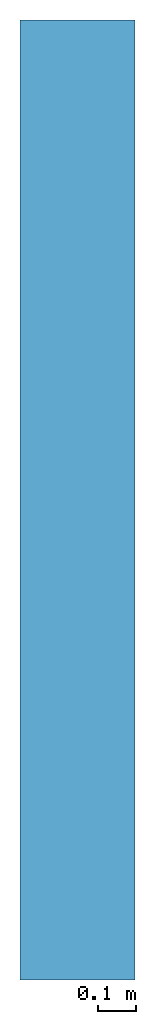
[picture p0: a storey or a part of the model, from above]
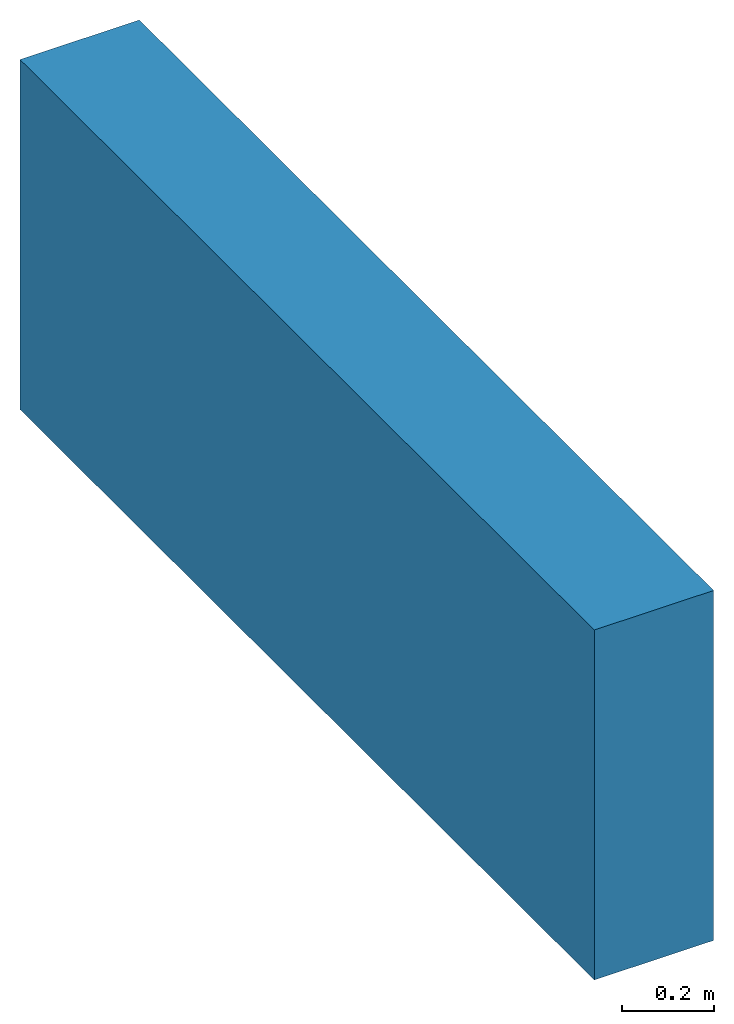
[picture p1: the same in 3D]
Properties of the parts of a building model (IFC2X3), part 1 of 4

# File
Description: ViewDefinition [CoordinationView]
File name: GM.TO-350-202.1 (EDITED).ifc (Edited by Naviate Simple BIM 2022 version 6)
Time: 2026-03-17T17:04:53+01:00
Written by: ODA SDAI 24.12
Made in: Autodesk Revit 25.4.20.11 (ENU) - IFC 25.4.0.27

# IfcProject, A181143
LongName: T2; Phase: Detaljprosjekt

# IfcSite (9)
Name | RefLatitude | RefLongitude | RefElevation (mm) | Reference latitude | Reference elevation | Reference longitude
ENGM | 33, 12, 51, 119999 | -97, -7, -51, -239999 | -4.85124e-10
 | 33, 12, 51, 119999 | -97, -7, -51, -239999 | 0
 | 33, 12, 51, 119999 | -97, -7, -51, -239999 | 0 | 33, 12, 51, 119999 | 0 | -97, -7, -51, -239999
4 x ENGM | 59, 54, 49, 759826 | 10, 44, 19, 467315 | 0 | 59, 54, 49, 759826 | 0 | 10, 44, 19, 467315 | MagiCAD Pset_Site - Name: ENGM
Gardermoen
Default | 59, 54, 49, 759826 | 10, 44, 19, 467315 | 0

# IfcBuilding (9)
Name
TS | LongName: TS; Pset_BuildingCommon - NumberOfStoreys: 16
2 x mc-building
4 x TS | MagiCAD Pset_Building - Building name: TS
TS
 | Pset_BuildingCommon - NumberOfStoreys: 13

# IfcBuildingStorey (15)
Name | In | Elevation (mm) | Name
Nivå E | mc-building | 207370
Nivå D | mc-building | 204000
Nivå F -0,7m | mc-building | 210200
Nivå F | mc-building | 210900
Nivå E | mc-building | 207370 | Nivå E
Nivå F | mc-building | 210900 | Nivå F
4 x Nivå F | TS | 210900 | Nivå F
2 x Nivå E | TS | 207370 | Nivå E
F | TS | 0
D | TS | 0
Nivå F - 0,7 m | TS | 210200 | Nivå F - 0,7 m

# IfcBuildingStorey: Level:8mm Head, Nivå F
LongName: Nivå F; Elevation: 210900 mm
Pset_ProductRequirements - Name: Nivå F; sets with these values: 2

# IfcBuildingStorey: Level:T2 - Kote (4)
In: TS
Name | LongName | Elevation (mm) | Pset_AirSideSystemInformation, Name | Pset_AirSideSystemInformation, sets with these values
Nivå E | Nivå E | 207370 | Nivå E | 2
Nivå F - 0,7 m | Nivå F - 0,7 m | 210200 | Nivå F - 0,7 m | 2
Nivå F | Nivå F | 210900 | Pset_ProductRequirements - Name: Nivå F; sets with these values: 2
Nivå G - 2,0m | Nivå G - 2,0m | 213700 | Nivå G - 2,0m | 2

# IfcBeam: B223 - Bjelke - HUP1:B223 - HUP 100 x 150 x 8 mm (8)
Type - PredefinedType: BEAM
Type - Pset_BeamCommon - LoadBearing: yes
Material: _NSW Stål
ePset_Simplebim - Assembly Level: Leaf
AVINOR - 08_Status: S4; 07_Fase: F90; 02_Prosjekt: A161568; 03_Ansvar: 182412; 04_Kontrakt: 182251; 06_Omrade: TS; 01_Lufthavnkode: ENGM
Pset_QuantityTakeOff - Reference: B223 - HUP 100 x 150 x 8 mm; sets with these values: 2
Pset_BeamCommon - IsExternal: no; Slope: 0 deg; Reference: B223 - HUP 100 x 150 x 8 mm
ePset_SimplebimBasicQuantities - Width (Simplebim): 100 mm; Height (Simplebim): 150 mm
ePset_LocationTool - Splitting: ORIGINAL
Name (B223 - Bjelke - HUP1:B223 - HUP 100 x 150 x 8 mm:...) | In | Span (mm) = Length (Simplebim) (mm) | Volume, net (Simplebim) (m3) | Weight, as steel (Simplebim) (kg) | Area, sides, net (Simplebim) (m2)
46579914 | Nivå F | 5590 | 0.020929 | 164.292 | 5.23973
46579916 | Nivå F | 5590 | 0.020929 | 164.292 | 5.23973
46579919 | Nivå F | 3808.67 | 0.0142596 | 111.938 | 3.5724
46579921 | Nivå F | 3808.67 | 0.0142596 | 111.938 | 3.5724
46580010 | Nivå F | 2480 | 0.00928512 | 72.8882 | 2.32877
46580027 | Nivå F | 3687.5 | 0.013806 | 108.377 | 3.45899
46580053 | Nivå G - 2,0m | 4445 | 0.0166421 | 130.64 | 4.16801
46580308 | Nivå G - 2,0m | 3687.5 | 0.013806 | 108.377 | 3.45899

# IfcBeam: DLB400*1500-800*700 (3)
In: F
Description: DLB400*1500-800*700
ePset_SimplebimBasicQuantities - Width (Simplebim): 400 mm; Height (Simplebim): 780 mm
Pset_BeamCommon - LoadBearing: no
ePset_Simplebim - Assembly Level: Leaf
ePset_LocationTool - Splitting: RESULT
AVINOR - 07_Fase: F90; 02_Prosjekt: T1; 03_Ansvar: FDV; 04_Kontrakt: FDV; 08_Status: S2; 06_Omrade: TS; 01_Lufthavnkode: ENGM
Tekla Common - Name: PREFABBJELKE; Bottom elevation: +209.180; Profile: DLB400*1500-800*700; Grade: C45/55; Top elevation: +210.680; Class: 130
Name | Area, sides, net (Simplebim) (m2) | Volume, net (Simplebim) (m3) | Length (Simplebim) (mm) | Weight, as steel (Simplebim) (kg) | Reference = Part mark | Assembly mark
PREFABBJELKE | 27.8 | 3.24111 | 11385 | 25442.7 | Concrete-4903(?) | PB-133(?)
PREFABBJELKE | 21.7946 | 2.50161 | 8970 | 19637.6 | Concrete-4901(?) | PB-131(?)
PREFABBJELKE | 2.29959 | 0.221519 | 710 | 1738.92 | Concrete-4901(?) | PB-131(?)

# IfcBuildingElementProxy (5)
ePset_Simplebim - Assembly Level: Leaf
ePset_LocationTool - Splitting: ORIGINAL
Name | In | Volume, net (Simplebim) (m3) | Area, largest surface, net (Simplebim) (m2) | Thickness (Simplebim) (mm) | Length (Simplebim) (mm) | Height (Simplebim) (mm)
hette 1100-2000-550_250x500 | Nivå F -0,7m | 1.50105 | 3 | 1500 | 2000 | 509.515 | Group: Mechanical +TU=360.032Avt 1; Mechanical +TU=360.032Avt 2
hette 1200-1200-400 ø315 2 | Nivå F -0,7m | 0.7216 | 1.44 | 1200 | 1200 | 510 | Group: +TQ=360.010 A
2 x MagiCAD_Sprinkler_Design_Area | Nivå F | 0.001 | 0.01 | 100 | 100 | 100 | Description: Sprinkler Design Area
Håndslukker | Nivå F | 0.0130382 | 0.261216 | 179.937 | 323.075 | 600.535

# IfcBuildingElementProxy: A234 - Gitter:A241 - Gitter 300 x 300_UK_2700_offset 51 (2)
In: Nivå F
Type - Material: <Unnamed>
ePset_Simplebim - Assembly Level: Leaf
Pset_QuantityTakeOff - Reference: A241 - Gitter 300 x 300_UK_2700_offset 51; sets with these values: 2
AVINOR - 08_Status: S4; 07_Fase: F90; 02_Prosjekt: A161568; 03_Ansvar: 182412; 04_Kontrakt: 182251; 06_Omrade: TS; 01_Lufthavnkode: ENGM
ePset_SimplebimBasicQuantities - Thickness (Simplebim): 300 mm; Height (Simplebim): 300 mm
ePset_LocationTool - Splitting: ORIGINAL
Name (A234 - Gitter:A241 - Gitter 300 x 300_UK_2700_offset 51:...) | Volume, net (Simplebim) (m3) | Length (Simplebim) (mm) | Area, largest surface, net (Simplebim) (m2)
46579913 | 0.5022 | 5580 | 1.674
46579918 | 0.352619 | 3917.99 | 1.1754

# IfcBuildingElementProxy: A275 - Pylon - venstrehengslet:Pylon med topp brakett, A275 - Pylon - venstrehengslet:Pylon med topp brakett:43108020
In: Nivå F
Type - Material: <Unnamed>
ePset_SimplebimBasicQuantities - Area, largest surface, net (Simplebim): 1.78713 m2; Volume, net (Simplebim): 0.0408924 m3; Thickness (Simplebim): 195 mm; Length (Simplebim): 752 mm; Height (Simplebim): 2500 mm
Pset_QuantityTakeOff - Reference: Pylon med topp brakett; sets with these values: 2
AVINOR - 08_Status: S1; 07_Fase: F50; 04_Kontrakt: 72587; 02_Prosjekt: 72101; 03_Ansvar: AE1; 06_Omrade: TS; 01_Lufthavnkode: ENGM
ePset_Simplebim - Assembly Level: Leaf
ePset_LocationTool - Splitting: ORIGINAL

# IfcBuildingElementProxy: ProvisionForVoid (3)
In: Nivå F
ePset_LocationTool - Splitting: ORIGINAL
ePset_SimplebimBasicQuantities - Height (Simplebim): 340 mm
ePset_Simplebim - Assembly Level: Leaf
Name | Volume, net (Simplebim) (m3) | Thickness (Simplebim) (mm) = Length (Simplebim) (mm) | Area, largest surface, net (Simplebim) (m2)
Round Vertical | 0.00170036 | 80 | 0.0853429
2 x Round Vertical | 0.000664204 | 50 | 0.0533393

# IfcColumn: A243 - Rullegardinskinner1:A243 - Portskinne Trav Val Innl (6)
Type - PredefinedType: COLUMN; Material: _NSW Stål
Type - Pset_ColumnCommon - LoadBearing: yes
ePset_LocationTool - Splitting: ORIGINAL
ePset_SimplebimBasicQuantities - Width (Simplebim): 60 mm; Depth (Simplebim): 100 mm
ePset_Simplebim - Assembly Level: Leaf
AVINOR - 08_Status: S4; 07_Fase: F90; 02_Prosjekt: A161568; 03_Ansvar: 182412; 04_Kontrakt: 182251; 06_Omrade: TS; 01_Lufthavnkode: ENGM
Pset_ColumnCommon - IsExternal: no; Reference: A243 - Portskinne Trav Val Innl
Pset_QuantityTakeOff - Reference: A243 - Portskinne Trav Val Innl; sets with these values: 2
Name (A243 - Rullegardinskinner1:A243 - Portskinne Trav Val Innl:...) | In | Volume, net (Simplebim) (m3) | Weight, as steel (Simplebim) (kg) | Area, sides, net (Simplebim) (m2) | Height (Simplebim) (mm)
46579901 | Nivå F | 0.0027552 | 21.6283 | 1.7584 | 2800
46579901 | Nivå G - 2,0m | 0.0001968 | 1.54488 | 0.1256 | 200
46579903 | Nivå F | 0.0025092 | 19.6972 | 1.6014 | 2550
46579905 | Nivå F | 0.0025092 | 19.6972 | 1.6014 | 2550
46579907 | Nivå F | 0.0027552 | 21.6283 | 1.7584 | 2800
46579907 | Nivå G - 2,0m | 0.0001968 | 1.54488 | 0.1256 | 200

# IfcColumn: B222 - HUP (Oppsveiset)1:B222 - HUP oppsveiset - 100 x 100 x 8 mm (2)
Type - PredefinedType: COLUMN; Material: _NSW Stål
Type - Pset_ColumnCommon - LoadBearing: yes
Pset_ColumnCommon - IsExternal: no; Reference: B222 - HUP oppsveiset - 100 x 100 x 8 mm
Pset_QuantityTakeOff - Reference: B222 - HUP oppsveiset - 100 x 100 x 8 mm; sets with these values: 2
ePset_SimplebimBasicQuantities - Width (Simplebim): 100 mm; Depth (Simplebim): 100 mm
ePset_Simplebim - Assembly Level: Leaf
AVINOR - 08_Status: S4; 07_Fase: F90; 02_Prosjekt: A161568; 03_Ansvar: 182412; 04_Kontrakt: 182251; 06_Omrade: TS; 01_Lufthavnkode: ENGM
ePset_LocationTool - Splitting: ORIGINAL
Name (B222 - HUP (Oppsveiset)1:B222 - HUP oppsveiset - 100 x 100 x 8 mm:...) | In | Volume, net (Simplebim) (m3) | Area, sides, net (Simplebim) (m2) | Height (Simplebim) (mm) | Weight, as steel (Simplebim) (kg)
46580008 | Nivå F | 0.0164864 | 4.1216 | 2800 | 129.418
46580008 | Nivå G - 2,0m | 0.0011776 | 0.2944 | 200 | 9.24416

# IfcColumn: B222 - HUP (Oppsveiset)1:B222 - HUP oppsveiset - 150 x 150 x 6 mm 2 (6)
Type - PredefinedType: COLUMN; Material: _NSW Stål
Type - Pset_ColumnCommon - LoadBearing: yes
Pset_ColumnCommon - IsExternal: no; Reference: B222 - HUP oppsveiset - 150 x 150 x 6 mm 2
Pset_QuantityTakeOff - Reference: B222 - HUP oppsveiset - 150 x 150 x 6 mm 2; sets with these values: 2
ePset_Simplebim - Assembly Level: Leaf
ePset_SimplebimBasicQuantities - Width (Simplebim): 150 mm; Depth (Simplebim): 150 mm
AVINOR - 08_Status: S4; 07_Fase: F90; 02_Prosjekt: A161568; 03_Ansvar: 182412; 04_Kontrakt: 182251; 06_Omrade: TS; 01_Lufthavnkode: ENGM
ePset_LocationTool - Splitting: ORIGINAL
Name (B222 - HUP (Oppsveiset)1:B222 - HUP oppsveiset - 150 x 150 x 6 mm 2:...) | In | Weight, as steel (Simplebim) (kg) | Area, sides, net (Simplebim) (m2) | Volume, net (Simplebim) (m3) | Height (Simplebim) (mm)
46579899 | Nivå F | 151.926 | 6.4512 | 0.0193536 | 2800
46579899 | Nivå G - 2,0m | 10.8518 | 0.4608 | 0.0013824 | 200
46579909 | Nivå F | 151.926 | 6.4512 | 0.0193536 | 2800
46579909 | Nivå G - 2,0m | 10.8518 | 0.4608 | 0.0013824 | 200
46579942 | Nivå F | 151.926 | 6.4512 | 0.0193536 | 2800
46579942 | Nivå G - 2,0m | 10.8518 | 0.4608 | 0.0013824 | 200

# IfcCovering (29)
PredefinedType: INSULATION
ePset_Simplebim - Assembly Level: Leaf
ePset_LocationTool - Splitting: ORIGINAL
Name | In | Description | Area, largest surface, net (Simplebim) (m2) | Volume, net (Simplebim) (m3) | Width (Simplebim) (mm) | Height (Simplebim) (mm) | Length (Simplebim) (mm)
EI30-30 | Nivå D | EI30 Brannisolasjon 30 mm | 0.7788 | 0.067968 | 360 | 660 | 1180
B=EI60 80 | Nivå D | EI60 Brannisolasjon 80mm | 0.3496 | 0.036708 | 105 | 460 | 760
EI30-30 | Nivå D | EI30 Brannisolasjon 30 mm | 0.2376 | 0.013068 | 55 | 360 | 660
EI30-30 | Nivå D | EI30 Brannisolasjon 30 mm | 0.26273 | 0.0212628 | 360 | 305.5 | 860
B=EI60 80 | Nivå D | EI60 Brannisolasjon 80mm | 0.4416 | 0.048576 | 460 | 110 | 960
EI30-30 | Nivå D | EI30 Brannisolasjon 30 mm | 0.3096 | 0.0266553 | 360 | 86.096 | 860
EI30-30 | Nivå D | EI30 Brannisolasjon 30 mm | 1.25672 | 0.101706 | 360 | 860 | 1461.3
EI30-30 | Nivå F -0,7m | EI30 Brannisolasjon 30 mm | 0.13639 | 0.0113856 | 296.5 | 240 | 460
EI30-30 | Nivå F -0,7m | EI30 Brannisolasjon 30 mm | 0.202078 | 0.0168691 | 439.3 | 240 | 460
EI30-30 | Nivå F -0,7m | EI30 Brannisolasjon 30 mm | 0.1104 | 0.009505 | 86.096 | 240 | 460
EI30-30 | Nivå F -0,7m | EI30 Brannisolasjon 30 mm | 0.5911 | 0.049344 | 460 | 240 | 1285
3 x EI30-30 | Nivå F -0,7m | EI30 Brannisolasjon 30 mm | 0.379852 | 0.0291658 | 405 | 310 | 405
EI30-30 | Nivå F -0,7m | EI30 Brannisolasjon 30 mm | 0.266022 | 0.00718091 | 310 | 310 | 273.5
EI30-30 | Nivå F -0,7m | EI30 Brannisolasjon 30 mm | 0.873739 | 0.0235854 | 310 | 310 | 898.3
EI30-30 | Nivå F -0,7m | EI30 Brannisolasjon 30 mm | 0.0277208 | 0.000748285 | 310 | 310 | 28.5
EI30-30 | Nivå F -0,7m | EI30 Brannisolasjon 30 mm | 0.0978494 | 0.00264131 | 310 | 100.6 | 310
B=EI60 80 | Nivå F -0,7m | EI60 Brannisolasjon 80mm | 0.340618 | 0.0346938 | 410 | 265 | 410
EI30-30 | Nivå F -0,7m | EI30 Brannisolasjon 30 mm | 0.995418 | 0.02687 | 310 | 310 | 1023.4
EI30-30 | Nivå F -0,7m | EI30 Brannisolasjon 30 mm | 0.126342 | 0.00968982 | 202.5 | 310 | 322.728
EI30-30 | Nivå F -0,7m | EI30 Brannisolasjon 30 mm | 0.343348 | 0.00926823 | 310 | 310 | 353
EI30-30 | Nivå F -0,7m | EI30 Brannisolasjon 30 mm | 0.109619 | 0.00295901 | 310 | 310 | 112.7
B=EI60 80 | Nivå F -0,7m | EI60 Brannisolasjon 80mm | 0.13092 | 0.00720061 | 410 | 410 | 55
EI30-30 | Nivå F -0,7m | EI30 Brannisolasjon 30 mm | 0.137954 | 0.0115162 | 299.9 | 240 | 460
EI30-30 | Nivå F -0,7m | EI30 Brannisolasjon 30 mm | 0.0746175 | 0.00232031 | 31.096 | 310 | 310
2 x EI30-30 | Nivå F -0,7m | EI30 Brannisolasjon 30 mm | 0.110414 | 0.0231983 | 341.972 | 240 | 466.958
EI30-30 | Nivå F -0,7m | EI30 Brannisolasjon 30 mm | 0.1104 | 0.006745 | 61.096 | 240 | 460

# IfcCovering: Compound Ceiling:A255 - HI-G03, Compound Ceiling:A255 - HI-G03:46580038
In: Nivå F
Type - PredefinedType: CEILING
Type - Pset_CoveringCommon - TotalThickness: 30 mm
AVINOR - 08_Status: S4; 07_Fase: F90; 02_Prosjekt: A161568; 03_Ansvar: 182412; 04_Kontrakt: 182251; 06_Omrade: TS; 01_Lufthavnkode: ENGM
ePset_SimplebimBasicQuantities - Volume, net (Simplebim): 3.30073 m3; Area, largest surface, net (Simplebim): 110.024 m2; Height (Simplebim): 30 mm; Width (Simplebim): 7139 mm; Length (Simplebim): 15575 mm
ePset_Simplebim - Assembly Level: Leaf
ePset_LocationTool - Splitting: RESULT
Pset_CoveringCommon - Reference: A255 - HI-G03; sets with these values: 2

# IfcCovering: Compound Ceiling:A255 - eksisterende finerte himlingsplater (4)
In: Nivå F
Type - PredefinedType: CEILING
Type - Pset_CoveringCommon - TotalThickness: 30 mm
ePset_LocationTool - Splitting: RESULT
ePset_Simplebim - Assembly Level: Leaf
ePset_SimplebimBasicQuantities - Height (Simplebim): 30 mm
Pset_CoveringCommon - Reference: A255 - eksisterende finerte himlingsplater; sets with these values: 2
AVINOR - 08_Status: S4; 07_Fase: F90; 03_Ansvar: FDV; 06_Omrade: TS; 01_Lufthavnkode: ENGM
Name (Compound Ceiling:A255 - eksisterende finerte himlingsplater:...) | Area, largest surface, net (Simplebim) (m2) | Width (Simplebim) (mm) | Length (Simplebim) (mm) | Volume, net (Simplebim) (m3)
30392710 | 16.5644 | 1093 | 15155 | 0.496933
30394236 | 4.96815 | 330 | 15055 | 0.149045
30394383 | 4.96815 | 330 | 15055 | 0.149045
30394414 | 13.8062 | 911 | 15155 | 0.414186

# IfcCovering: Compound Ceiling:A255 - eksisterende himling perfo. metall paneler 200, Compound Ceiling:A255 - eksisterende himling perfo. metall paneler 200:30393361
In: Nivå F
Type - PredefinedType: CEILING
Type - Pset_CoveringCommon - TotalThickness: 30 mm
ePset_LocationTool - Splitting: RESULT
ePset_Simplebim - Assembly Level: Leaf
Pset_QuantityTakeOff - Reference: A255 - eksisterende himling perfo. metall paneler 200; sets with these values: 2
ePset_SimplebimBasicQuantities - Area, largest surface, net (Simplebim): 6.64992 m2; Height (Simplebim): 30 mm; Width (Simplebim): 1270 mm; Length (Simplebim): 5235 mm; Volume, net (Simplebim): 0.199501 m3
AVINOR - 08_Status: S4; 07_Fase: F90; 03_Ansvar: FDV; 06_Omrade: TS; 01_Lufthavnkode: ENGM

# IfcCurtainWall: Curtain Wall:A242 - IGV - Glass - 10 mm (2)
In: Nivå F
AVINOR - 08_Status: S4; 07_Fase: F90; 03_Ansvar: 182412; 02_Prosjekt: A173790; 06_Omrade: TS; 01_Lufthavnkode: ENGM
ePset_SimplebimBasicQuantities - Height: 2500 mm
Pset_QuantityTakeOff - Reference: A242 - IGV - Glass - 10 mm
Pset_CurtainWallCommon - IsExternal: no; Reference: A242 - IGV - Glass - 10 mm
ePset_Simplebim - Assembly Level: Topmost
Name (Curtain Wall:A242 - IGV - Glass - 10 mm:...) | 05_ID-nummer | Volume, net (Simplebim) (m3) | Width (mm) | Length (mm)
47507136 | +TS=243.001-IG0058 | 0.136829 | 100 | 3950
47507151 | +TS=243.001-IG0059 | 0.157984 | 105 | 4325

# IfcCurtainWall: Curtain Wall:A242 - IGV - Glass - 20mm (2)
In: Nivå F
Pset_QuantityTakeOff - Reference: A242 - IGV - Glass - 20mm
ePset_SimplebimBasicQuantities - Width: 20 mm; Height: 440 mm
ePset_Simplebim - Assembly Level: Topmost
Pset_CurtainWallCommon - IsExternal: no; Reference: A242 - IGV - Glass - 20mm
AVINOR - 03_Ansvar: FDV
Name (Curtain Wall:A242 - IGV - Glass - 20mm:...) | Volume, net (Simplebim) (m3) | Length (mm)
46514074 | 0.0076472 | 869
46514077 | 0.0170192 | 1934

# IfcCurtainWall: Curtain Wall:A242 - IGV 50 x 60mm (Glass 10mm) (2)
In: Nivå F
Pset_CurtainWallCommon - IsExternal: no; Reference: A242 - IGV 50 x 60mm (Glass 10mm)
AVINOR - 07_Fase: F90; 06_Omrade: TS; 01_Lufthavnkode: ENGM
Pset_QuantityTakeOff - Reference: A242 - IGV 50 x 60mm (Glass 10mm)
ePset_Simplebim - Assembly Level: Topmost
ePset_SimplebimBasicQuantities - Length: 1274.01 mm; Volume, net (Simplebim): 0.0839612 m3; Width: 100 mm; Height: 2890 mm
Name (Curtain Wall:A242 - IGV 50 x 60mm (Glass 10mm):...) | 03_Ansvar | 08_Status
30360349 | FDV | S2
46579949 | 182412 | S4 | AVINOR - 02_Prosjekt: A161568; 04_Kontrakt: 182251

# IfcCurtainWall: Curtain Wall:A245 - BIM av T1 - IMK 20mm - Offset 30mm (2)
In: Nivå F
ePset_SimplebimBasicQuantities - Width: 110 mm; Height: 4490 mm
Pset_QuantityTakeOff - Reference: A245 - BIM av T1 - IMK 20mm - Offset 30mm
AVINOR - 07_Fase: F90; 03_Ansvar: FDV; 08_Status: S2; 06_Omrade: TS; 01_Lufthavnkode: ENGM
Pset_CurtainWallCommon - Reference: A245 - BIM av T1 - IMK 20mm - Offset 30mm; IsExternal: no
ePset_Simplebim - Assembly Level: Topmost
Name (Curtain Wall:A245 - BIM av T1 - IMK 20mm - Offset 30mm:...) | Volume, net (Simplebim) (m3) | Length (mm)
30365162 | 0.745048 | 8299.79
30365222 | 0.286525 | 3500.46

# IfcCurtainWall: Curtain Wall:A245 - IMK (Innvendig Metall Kledning) 20mm - Offset 30mm, Curtain Wall:A245 - IMK (Innvendig Metall Kledning) 20mm - Offset 30mm:40491772
In: Nivå F
Pset_CurtainWallCommon - IsExternal: no; Reference: A245 - IMK (Innvendig Metall Kledning) 20mm - Offset 30mm
Pset_QuantityTakeOff - Reference: A245 - IMK (Innvendig Metall Kledning) 20mm - Offset 30mm
ePset_SimplebimBasicQuantities - Volume, net (Simplebim): 0.234757 m3; Height: 2240 mm; Length: 6591.02 mm; Width: 195.091 mm
ePset_Simplebim - Assembly Level: Topmost
AVINOR - 07_Fase: F90; 08_Status: S1; 03_Ansvar: FDV; 06_Omrade: TS; 01_Lufthavnkode: ENGM

# IfcCurtainWall: Curtain Wall:A245 - IMK - Metal Kledning (5)
In: Nivå F
Pset_QuantityTakeOff - Reference: A245 - IMK - Metal Kledning
AVINOR - 08_Status: S4; 07_Fase: F90; 02_Prosjekt: A161568; 03_Ansvar: 182412; 04_Kontrakt: 182251; 06_Omrade: TS; 01_Lufthavnkode: ENGM
ePset_SimplebimBasicQuantities - Width: 20 mm
Pset_CurtainWallCommon - IsExternal: no; Reference: A245 - IMK - Metal Kledning
ePset_Simplebim - Assembly Level: Topmost
Name (Curtain Wall:A245 - IMK - Metal Kledning:...) | Volume, net (Simplebim) (m3) | Height (mm) | Length (mm)
46579930 | 0.0962 | 500 | 9620
46579940 | 0.00924 | 2310 | 200
46580012 | 0.0434658 | 490 | 4435.28
46580016 | 0.0419 | 500 | 4190
46580018 | 0.038122 | 490 | 3890

# IfcCurtainWall: Curtain Wall:A245 - IMK - Metal Kledning 3mm (12)
In: Nivå F
Pset_CurtainWallCommon - IsExternal: no; Reference: A245 - IMK - Metal Kledning 3mm
AVINOR - 08_Status: S4; 07_Fase: F90; 02_Prosjekt: A161568; 03_Ansvar: 182412; 04_Kontrakt: 182251; 06_Omrade: TS; 01_Lufthavnkode: ENGM
ePset_Simplebim - Assembly Level: Topmost
ePset_SimplebimBasicQuantities - Width: 3 mm
Pset_QuantityTakeOff - Reference: A245 - IMK - Metal Kledning 3mm
Name (Curtain Wall:A245 - IMK - Metal Kledning 3mm:...) | Volume, net (Simplebim) (m3) | Length (mm) | Height (mm)
46580055 | 0.0051678 | 1914 | 900
46580112 | 0.0013125 | 175 | 2500
46580250 | 0.0013125 | 175 | 2500
46580254 | 0.0013125 | 175 | 2500
46580258 | 0.0013125 | 175 | 2500
46580260 | 0.0013125 | 175 | 2500
46580262 | 0.0013125 | 175 | 2500
46580316 | 0.0013125 | 175 | 2500
46580318 | 0.0013125 | 175 | 2500
46580322 | 0.0013125 | 175 | 2500
46580324 | 0.0013125 | 175 | 2500
46580328 | 0.0013125 | 175 | 2500

# IfcCurtainWall: Curtain Wall:A245 - IMK - Metal Kledning KL-S01 (4)
In: Nivå F
AVINOR - 08_Status: S4; 07_Fase: F90; 09_Arbeidspakke: SELV ARBEIDER; 01_Lufthavnkode: ENGM
ePset_SimplebimBasicQuantities - Width: 10 mm; Height: 100 mm
Pset_QuantityTakeOff - Reference: A245 - IMK - Metal Kledning KL-S01
ePset_Simplebim - Assembly Level: Topmost
Pset_CurtainWallCommon - IsExternal: no; Reference: A245 - IMK - Metal Kledning KL-S01
Name (Curtain Wall:A245 - IMK - Metal Kledning KL-S01:...) | Length (mm) | Volume, net (Simplebim) (m3)
67054707 | 673 | 0.000673
67054709 | 120 | 0.00012
67054711 | 673 | 0.000673
67072278 | 3575.42 | 0.00357542

# IfcCurtainWall: Curtain Wall:KL - K05 Spilevegg 40x20 WHS (15)
In: Nivå F
Pset_QuantityTakeOff - Reference: KL - K05 Spilevegg 40x20 WHS
AVINOR - 08_Status: S4; 07_Fase: F90; 03_Ansvar: 188110; 02_Prosjekt: 10004394; 06_Omrade: TS; 09_Arbeidspakke: SELV ARBEIDER; 01_Lufthavnkode: ENGM
Pset_CurtainWallCommon - Reference: KL - K05 Spilevegg 40x20 WHS; IsExternal: no
ePset_Simplebim - Assembly Level: Topmost
ePset_SimplebimBasicQuantities - Width: 32 mm
Name (Curtain Wall:KL - K05 Spilevegg 40x20 WHS:...) | Volume, net (Simplebim) (m3) | Length (mm) | Height (mm)
66815049 | 0.0587328 | 840 | 2760
66815982 | 0.0205504 | 3120 | 260
66821902 | 0.0377568 | 540 | 2760
66823302 | 0.007728 | 100 | 2760
66824036 | 0.0461472 | 660 | 2760
66835721 | 0.0106704 | 1620 | 260
66838884 | 0.0461472 | 652.5 | 2760
66839107 | 0.0461472 | 650 | 2760
66864434 | 0.0461472 | 660 | 2760
66864448 | 0.0370944 | 520 | 2760
66866073 | 0.0335616 | 480 | 2760
66866487 | 0.007728 | 100 | 2760
66866842 | 0.0335616 | 480 | 2760
66867979 | 0.0341152 | 1191.67 | 2760
66872022 | 0.007728 | 100 | 2760

# IfcDistributionControlElement: Brann Spjeld 2 (4)
In: Nivå F
Type - Description: BrannSpjeld
Classification: XN1.31 Not defined (NS3420); Group: Brannspjeld
ePset_LocationTool - Splitting: ORIGINAL
ePset_Simplebim - Assembly Level: Leaf
MagiCAD Pset_Device - User code: -DI; Circuit order no: <unnamed>; System code: 542-DI; Length [mm]: 0 mm; Width [mm]: 0 mm; Height [mm]: 0 mm; Manufacturer: General; National code: XN1.31

# IfcDistributionControlElement: Brannalarm Multikriteriedetektor OT Blue
In: Nivå F
Type - Description: Brannalarm Multikriteriedetektor OT Blue
MagiCAD Pset_Device - System code: 542; User code: -TY; Length [mm]: 0 mm; Width [mm]: 0 mm; Height [mm]: 0 mm; Installation Code: 2
ePset_Simplebim - Assembly Level: Leaf
ePset_LocationTool - Splitting: ORIGINAL
Group: Brannalarm

# IfcDistributionControlElement: FIRE-FAD-FIRE-DUMMY
In: Nivå F
Type - Description: Brannalarm Dørholdemagnet
Classification: XJ4.1 Not defined (NS3420); Group: Brannalarm
ePset_LocationTool - Splitting: ORIGINAL
MagiCAD Pset_Device - System code: 542; Product code: Fire-Dummy-FD; P1: -QZ; Circuit order no: <unnamed>; Length [mm]: 0 mm; Manufacturer: Generic; Width [mm]: 10 mm; Height [mm]: 10 mm; National code: XJ4.1
ePset_Simplebim - Assembly Level: Leaf

# IfcDistributionControlElement: Nødåpner (2)
In: Nivå F
Type - Description: Nødåpner KAC
ePset_LocationTool - Splitting: ORIGINAL
ePset_Simplebim - Assembly Level: Leaf
AVINOR - 08_Status: S4; 07_Fase: F90; 05_ID-nummer: +TS=277.063-IK0101; 04_Kontrakt: 188899; 02_Prosjekt: 10003733; 03_Ansvar: 187259; 01_Lufthavnkode: ENGM
MagiCAD Pset_Device - System code: 543; User code: -IK; IP_Code: IP20; P1: -XS; Length [mm]: 0 mm; Width [mm]: 0 mm; Height [mm]: 0 mm; Manufacturer: General
Pset_ElectricalDeviceCommon - IP_Code: IP20
Group: Adgangskontroll, Innbruddsalarm

# IfcDistributionControlElement: SECURITY ALARM 3 (2)
In: Nivå F
Type - Description: Kortleser med tastatur
Pset_ElectricalDeviceCommon - IP_Code: IP44
ePset_Simplebim - Assembly Level: Leaf
MagiCAD Pset_Device - System code: 543; Product code: Security alarm 3; P1: -QP; Length [mm]: 0 mm; Manufacturer: General; Width [mm]: 25 mm; Height [mm]: 140 mm; IP_Code: IP44
ePset_LocationTool - Splitting: ORIGINAL
AVINOR - 03_Ansvar: T20100; 04_Kontrakt: 72561; 02_Prosjekt: 72101; 01_Lufthavnkode: ENGM
Group: Adgangskontroll, Innbruddsalarm
Name | 05_ID-nummer
SECURITY ALARM 3 | +TS=543.060-QP0021
SECURITY ALARM 3 | +TS=543.063-QP0012

# IfcDistributionControlElement: Standard (18)
In: Nivå F
Type - Description: Brannalarm Røykdetektor
MagiCAD Pset_Device - Length [mm]: 0 mm; Width [mm]: 0 mm; Height [mm]: 0 mm
ePset_LocationTool - Splitting: ORIGINAL
ePset_Simplebim - Assembly Level: Leaf
Name | Classification | System code | User code | Host | National code | MagiCAD Pset_Device, IP_Code = Pset_ElectricalDeviceCommon, IP_Code | P1 | Installation Code | Circuit order no | Manufacturer | Group
8 x Standard | XJ1.1115 Not defined (NS3420) | 542 | -TY | +TS=542.003 | XJ1.1115 | IP20 | -RY | 2 | 1 | General | Brannalarm
2 x Standard | XJ1.1199 Not defined (NS3420) | 542 | -TV | +TS=542.003 | XJ1.1199 | IP44 | -TV | 2 | 1 | General | Description: Brannalarm Manuell melder
Standard | XJ1.1115 Not defined (NS3420) | 542 | -TY |  | XJ1.1115 | IP20 | -RY | 2 |  | General | Brannalarm
Standard |  | 542 | -TY | +TS=542.003 |  |  |  | 2 | 1 |  | Brannalarm | Description: Brannalarm Røykdetektor over himling
Standard | XJ1.1117 Not defined (NS3420) | 542 | -TW |  | XJ1.1117 |  | -RY | 2 |  | General | Brannalarm | Description: Brannalarm Varmedetektor
Standard | XJ1.1115 Not defined (NS3420) | 542 | -TY |  | XJ1.1115 |  | -TY | 2 |  | General | Brannalarm | Description: Brannalarm Multikriteriedetektor
Standard |  | 542 | -TY |  |  |  |  | 2 |  |  | Brannalarm | Description: Brannalarm Røykdetektor over himling
Standard |  | 542 |  |  |  |  | -OS | 2 |  |  | Brannalarm | Description: Brannalarm Parallell lampe
Standard | XJ4.1 Not defined (NS3420) |  |  |  | XJ4.1 | IP54 | -QZ |  | <unnamed> | General | Description: Brannalarm Dørholdemagnet
Standard | XJ4.1 Not defined (NS3420) |  |  |  | XJ4.1 | IP54 | -QZ |  |  | General | Description: Brannalarm Dørholdemagnet

# IfcDistributionPort (46)
Description: Flow; FlowDirection: SOURCEANDSINK
ePset_Simplebim - Assembly Level: Leaf
Name
Port_12930314_1
3 x Port_17435364_1
3 x Port_12930327_1
3 x Port_17504446_1
2 x Port_12930333_1
2 x Port_17435365_1
2 x Port_14258463_1
2 x Port_17435373_1
2 x Port_18742834_1
3 x Port_17504448_1
2 x Port_17435366_1
2 x Port_17435375_1
2 x Port_17435367_1
Port_17504449_1
3 x Port_18741943_1
3 x Port_18645512_1
Port_22217789_1
Port_23095620_1
2 x Port_24785312_1
2 x Port_24806115_1
3 x Port_24789200_1
Port_24797950_1

# IfcDoor: A20 - Slagdør - Dobbel ulik - Glassfelt:A233 - DI_SSG - 1290 x 2090 mm, A20 - Slagdør - Dobbel ulik - Glassfelt:A233 - DI_SSG - 1290 x 2090 mm:47507117
In: Nivå F
Type - OperationType: DOUBLE_DOOR_SINGLE_SWING; ParameterTakesPrecedence: no; Sizeable: no; Material: _NSW Stål, Glass(Avinor), _NSW Stål - rustfritt
Type - IfcDoorPanelProperties - PanelOperation: SWINGING
OverallHeight: 2110 mm; OverallWidth: 1310 mm
ePset_Simplebim - Assembly Level: Leaf
Pset_QuantityTakeOff - Reference: A233 - DI_SSG - 1290 x 2090 mm
ePset_LocationTool - Splitting: ORIGINAL
AVINOR - 08_Status: S4; 07_Fase: F90; 05_ID-nummer: +TS=243.001-IP0196; 03_Ansvar: 182412; 02_Prosjekt: A173790; 06_Omrade: TS; 01_Lufthavnkode: ENGM
Pset_DoorCommon - IsExternal: no; Reference: A233 - DI_SSG - 1290 x 2090 mm
ePset_SimplebimBasicQuantities - Area (Simplebim): 2.6961 m2; Height, opening (Simplebim): 2110 mm; Area, opening (Simplebim): 2.7641 m2; Width (Simplebim): 1290 mm; Width, opening (Simplebim): 1310 mm; Height (Simplebim): 2090 mm; Length, frame (Simplebim): 5470 mm

# IfcDoor: A20 - Slagdør - Enkel2:A243 - DI_LTO - 0890 x 2090 mm, A20 - Slagdør - Enkel2:A243 - DI_LTO - 0890 x 2090 mm:47507115
In: Nivå F
Type - OperationType: SINGLE_SWING_RIGHT; ParameterTakesPrecedence: no; Sizeable: no; Material: N_Door - Handle, _NSW Stål - rustfritt, _NSW Dør - karm, hvit, N_Door - Threshold, N_Door - Panel
Type - IfcDoorPanelProperties - PanelOperation: SWINGING
OverallHeight: 2110 mm; OverallWidth: 910 mm
ePset_LocationTool - Splitting: ORIGINAL
AVINOR - 05_ID-nummer: TS=243.001-IP0198; 08_Status: S4; 07_Fase: F90; 03_Ansvar: 182412; 02_Prosjekt: A173790; 06_Omrade: TS; 01_Lufthavnkode: ENGM
ePset_Simplebim - Assembly Level: Leaf
Pset_QuantityTakeOff - Reference: A243 - DI_LTO - 0890 x 2090 mm
Pset_DoorCommon - Reference: A243 - DI_LTO - 0890 x 2090 mm; IsExternal: no
ePset_SimplebimBasicQuantities - Height, opening (Simplebim): 2110 mm; Area, opening (Simplebim): 1.9201 m2; Area (Simplebim): 1.8601 m2; Width, opening (Simplebim): 910 mm; Width (Simplebim): 890 mm; Height (Simplebim): 2090 mm; Length, frame (Simplebim): 5070 mm

# IfcDoor: A20 - Slagdør - Enkel2:A243 - DI_LTO - 0990 x 2090 mm, A20 - Slagdør - Enkel2:A243 - DI_LTO - 0990 x 2090 mm:67393519
In: Nivå F
Type - OperationType: SINGLE_SWING_RIGHT; ParameterTakesPrecedence: no; Sizeable: no; Material: N_Door - Handle, _NSW Stål - rustfritt, _NSW Dør - karm, hvit, N_Door - Threshold, N_Door - Panel
Type - IfcDoorPanelProperties - PanelOperation: SWINGING
OverallHeight: 2110 mm; OverallWidth: 1010 mm
Pset_DoorCommon - Reference: A243 - DI_LTO - 0990 x 2090 mm; IsExternal: no
ePset_Simplebim - Assembly Level: Leaf
AVINOR - 08_Status: S4; 07_Fase: F90; 03_Ansvar: 05.214; 02_Prosjekt: A173790; 06_Omrade: TS; 01_Lufthavnkode: ENGM
ePset_SimplebimBasicQuantities - Height, opening (Simplebim): 2110 mm; Area (Simplebim): 2.0691 m2; Width (Simplebim): 990 mm; Width, opening (Simplebim): 1010 mm; Height (Simplebim): 2090 mm; Length, frame (Simplebim): 5170 mm; Area, opening (Simplebim): 2.1311 m2
ePset_LocationTool - Splitting: ORIGINAL
Pset_QuantityTakeOff - Reference: A243 - DI_LTO - 0990 x 2090 mm

# IfcDoor: A20 - Slagdør - Enkel3:A243 - DI_LTO - 0690 x 2240 mm, A20 - Slagdør - Enkel3:A243 - DI_LTO - 0690 x 2240 mm:40491763
In: Nivå F
Type - OperationType: SINGLE_SWING_RIGHT; ParameterTakesPrecedence: no; Sizeable: no; Material: N_Door - Handle, _NSW Stål - rustfritt, _NSW Dør - karm, hvit, N_Door - Threshold, N_Door - Panel
Type - IfcDoorPanelProperties - PanelOperation: SWINGING
OverallHeight: 2260 mm; OverallWidth: 710 mm
Pset_DoorCommon - IsExternal: no; Reference: A243 - DI_LTO - 0690 x 2240 mm
ePset_SimplebimBasicQuantities - Height, opening (Simplebim): 2260 mm; Area (Simplebim): 1.5456 m2; Area, opening (Simplebim): 1.6046 m2; Width, opening (Simplebim): 710 mm; Width (Simplebim): 690 mm; Height (Simplebim): 2240 mm; Length, frame (Simplebim): 5170 mm
ePset_Simplebim - Assembly Level: Leaf
Pset_QuantityTakeOff - Reference: A243 - DI_LTO - 0690 x 2240 mm
AVINOR - 07_Fase: F90; 03_Ansvar: FDV; 08_Status: S2; 06_Omrade: TS; 01_Lufthavnkode: ENGM
ePset_LocationTool - Splitting: ORIGINAL

# IfcDoor: A20 - Slagdør - Enkel:A243 - DI_LTO - 0590 x 0590 mm, A20 - Slagdør - Enkel:A243 - DI_LTO - 0590 x 0590 mm:67391519
In: Nivå F
Type - OperationType: SINGLE_SWING_RIGHT; ParameterTakesPrecedence: no; Sizeable: no; Material: N_Door - Handle, _NSW Stål - rustfritt, _NSW Dør - karm, hvit, N_Door - Threshold, N_Door - Panel
Type - IfcDoorPanelProperties - PanelOperation: SWINGING
OverallHeight: 610 mm; OverallWidth: 610 mm
ePset_LocationTool - Splitting: ORIGINAL
Pset_DoorCommon - Reference: A243 - DI_LTO - 0590 x 0590 mm; IsExternal: no
AVINOR - 08_Status: S4; 07_Fase: F90; 03_Ansvar: 188110; 02_Prosjekt: 10004394; 05_ID-nummer: +TS=243.001-IM2783; 06_Omrade: TS; 01_Lufthavnkode: ENGM
ePset_SimplebimBasicQuantities - Width (Simplebim): 590 mm; Height (Simplebim): 1015 mm; Length, frame (Simplebim): 2620 mm; Area (Simplebim): 0.59885 m2
Pset_QuantityTakeOff - Reference: A243 - DI_LTO - 0590 x 0590 mm
ePset_Simplebim - Assembly Level: Leaf

# IfcDoor: A20 - Slagdør - Enkel:A243 - DI_LTO - 0990 x 2090mm (3)
In: Nivå F
Type - OperationType: SINGLE_SWING_RIGHT; ParameterTakesPrecedence: no; Sizeable: no; Material: N_Door - Handle, _NSW Stål - rustfritt, _NSW Dør - karm, hvit, N_Door - Threshold, N_Door - Panel
Type - IfcDoorPanelProperties - PanelOperation: SWINGING
OverallHeight: 2110 mm; OverallWidth: 1010 mm
AVINOR - 08_Status: S4; 07_Fase: F90; 03_Ansvar: 188110; 02_Prosjekt: 10004394; 06_Omrade: TS; 01_Lufthavnkode: ENGM
ePset_LocationTool - Splitting: ORIGINAL
Pset_DoorCommon - Reference: A243 - DI_LTO - 0990 x 2090mm; IsExternal: no
ePset_Simplebim - Assembly Level: Leaf
ePset_SimplebimBasicQuantities - Height, opening (Simplebim): 2110 mm; Area (Simplebim): 2.0691 m2; Width (Simplebim): 990 mm; Width, opening (Simplebim): 1010 mm; Height (Simplebim): 2090 mm; Length, frame (Simplebim): 5170 mm; Area, opening (Simplebim): 2.1311 m2
Pset_QuantityTakeOff - Reference: A243 - DI_LTO - 0990 x 2090mm
Name (A20 - Slagdør - Enkel:A243 - DI_LTO - 0990 x 2090mm:...) | CQFireRequirement | 04_Kontrakt | 05_ID-nummer
66805201 | EI30 | 187110 | +TS=243.001-IO2801
66805203 | EI30 | 187110 | +TS=243.001-IO2800
66860376

# IfcDoor: A20 - Slagdør - Enkel:A243 - DI_LTO - 0990 x 2240 mm, A20 - Slagdør - Enkel:A243 - DI_LTO - 0990 x 2240 mm:46514059
In: Nivå F
Type - OperationType: SINGLE_SWING_RIGHT; ParameterTakesPrecedence: no; Sizeable: no; Material: N_Door - Handle, _NSW Stål - rustfritt, _NSW Dør - karm, hvit, N_Door - Threshold, N_Door - Panel
Type - IfcDoorPanelProperties - PanelOperation: SWINGING
OverallHeight: 2260 mm; OverallWidth: 1010 mm
Pset_DoorCommon - Reference: A243 - DI_LTO - 0990 x 2240 mm; IsExternal: no
ePset_LocationTool - Splitting: ORIGINAL
ePset_SimplebimBasicQuantities - Area, opening (Simplebim): 2.2826 m2; Height, opening (Simplebim): 2260 mm; Width (Simplebim): 990 mm; Width, opening (Simplebim): 1010 mm; Height (Simplebim): 2240 mm; Length, frame (Simplebim): 5470 mm; Area (Simplebim): 2.2176 m2
AVINOR - 08_Status: S4; 07_Fase: F90; 06_Omrade: TS; 03_Ansvar: OSL; 05_ID-nummer: +TS=243.001-IP0309; 01_Lufthavnkode: ENGM; 02_Prosjekt: AO205066
Pset_QuantityTakeOff - Reference: A243 - DI_LTO - 0990 x 2240 mm
ePset_Simplebim - Assembly Level: Leaf

# IfcDoor: A20 - Slagdør - Enkel:A243 - DI_LTO - 1190 x 2085mm, A20 - Slagdør - Enkel:A243 - DI_LTO - 1190 x 2085mm:67079654
In: Nivå F
Type - OperationType: SINGLE_SWING_RIGHT; ParameterTakesPrecedence: no; Sizeable: no; Material: N_Door - Handle, _NSW Stål - rustfritt, _NSW Dør - karm, hvit, N_Door - Threshold, N_Door - Panel
Type - IfcDoorPanelProperties - PanelOperation: SWINGING
OverallHeight: 2105 mm; OverallWidth: 1210 mm
ePset_Simplebim - Assembly Level: Leaf
ePset_LocationTool - Splitting: ORIGINAL
ePset_SimplebimBasicQuantities - Width (Simplebim): 1190 mm; Height (Simplebim): 2085 mm; Length, frame (Simplebim): 5360 mm; Area (Simplebim): 2.48115 m2
Pset_QuantityTakeOff - Reference: A243 - DI_LTO - 1190 x 2085mm
AVINOR - 08_Status: S4; 07_Fase: F90; 04_Kontrakt: 187110; 03_Ansvar: 188110; 02_Prosjekt: 10004394; 05_ID-nummer: +TS=243.001-IO2802; 06_Omrade: TS; 01_Lufthavnkode: ENGM
Pset_DoorCommon - Reference: A243 - DI_LTO - 1190 x 2085mm; IsExternal: no

# IfcDoor: A20 - Slagdør - Enkel:A243 - DI_SSO - 0890 x 2240 mm, A20 - Slagdør - Enkel:A243 - DI_SSO - 0890 x 2240 mm:3924681
In: Nivå F
Type - OperationType: SINGLE_SWING_RIGHT; ParameterTakesPrecedence: no; Sizeable: no; Material: N_Door - Handle, _NSW Stål - rustfritt, _NSW Stål, N_Door - Threshold, N_Door - Panel
Type - IfcDoorPanelProperties - PanelOperation: SWINGING
OverallHeight: 2260 mm; OverallWidth: 910 mm
ePset_SimplebimBasicQuantities - Height, opening (Simplebim): 2260 mm; Area, opening (Simplebim): 2.0566 m2; Area (Simplebim): 1.9936 m2; Width, opening (Simplebim): 910 mm; Width (Simplebim): 890 mm; Height (Simplebim): 2240 mm; Length, frame (Simplebim): 5370 mm
ePset_LocationTool - Splitting: ORIGINAL
Identity Data - CQFireRequirement: EI 60Sa
Pset_QuantityTakeOff - Reference: A243 - DI_SSO - 0890 x 2240 mm
ePset_Simplebim - Assembly Level: Leaf
AVINOR - 07_Fase: F90; 03_Ansvar: FDV; 08_Status: S2; 06_Omrade: TS; 01_Lufthavnkode: ENGM
Pset_DoorCommon - Reference: A243 - DI_SSO - 0890 x 2240 mm; IsExternal: no

# IfcElectricalCircuit, Bæresystem generelt
Description: 410

# IfcFlowController: ABC-CU-LT 400 400 Belimo 24V
In: Nivå F
Type - Description: Rectangular fire damper with actuator. Classification EI60S-EI120S. Installation in wall, floor & remote from wall. Close installation possible. Dimensions 200x100 - 800x600. VVS AMA QJC.2.; PredefinedType: FIREDAMPER
ePset_LocationTool - Splitting: ORIGINAL
ePset_Simplebim - Assembly Level: Leaf
Group: +TQ=360.010 T

# IfcFlowController: FDT/R-300-800
In: Nivå D
Type - Description: Fire damper for Rectangular and Circular Ducts; PredefinedType: FIREDAMPER
ePset_LocationTool - Splitting: ORIGINAL
ePset_Simplebim - Assembly Level: Leaf
Group: +TQ=360.010 A

# IfcFlowController: IGNIS-C-EI30-250
In: Nivå F -0,7m
Type - Description: CIRCULAR FIRE DAMPER CLASS EI30; PredefinedType: FIREDAMPER
ePset_LocationTool - Splitting: ORIGINAL
ePset_Simplebim - Assembly Level: Leaf
Group: +TQ=360.010 A

# IfcFlowController: IGNIS-C-EI60-200
In: Nivå F -0,7m
Type - Description: CIRCULAR FIRE DAMPER CLASS EI60; PredefinedType: FIREDAMPER
ePset_LocationTool - Splitting: ORIGINAL
ePset_Simplebim - Assembly Level: Leaf
Group: +TQ=360.010 T

# IfcFlowController: IRIS-031 (4)
In: Nivå F
Type - Description: Balancing damper; PredefinedType: BALANCINGDAMPER
Classification: VE5.142012 Not defined (NS3420); Group: +TQ=360.010 T
ePset_LocationTool - Splitting: ORIGINAL
ePset_Simplebim - Assembly Level: Leaf

# IfcFlowController: IRIS-250 (2)
Type - Description: Balancing damper; PredefinedType: BALANCINGDAMPER
ePset_LocationTool - Splitting: ORIGINAL
ePset_Simplebim - Assembly Level: Leaf
Name | In | Group
IRIS-250 | Nivå F -0,7m | +TQ=360.010 A
IRIS-250 | Nivå F | +TQ=360.010 T

# IfcFlowController: IRIS-315 (2)
In: Nivå F
Type - PredefinedType: BALANCINGDAMPER
ePset_Simplebim - Assembly Level: Leaf
ePset_LocationTool - Splitting: ORIGINAL
Group: +TQ=360.010 T

# IfcFlowController: REGO-T-300-800
In: Nivå D
Type - Description: Damper; PredefinedType: BALANCINGDAMPER
Classification: VE5.142012 Not defined (NS3420); Group: +TQ=360.010 A
ePset_Simplebim - Assembly Level: Leaf
ePset_LocationTool - Splitting: ORIGINAL

# IfcFlowController: Åpneknapp (3)
In: Nivå F
Type - Description: Åpneknapp trykknapp
AVINOR - 03_Ansvar: T20100; 04_Kontrakt: 72561; 02_Prosjekt: 72101; 01_Lufthavnkode: ENGM
ePset_Simplebim - Assembly Level: Leaf
ePset_LocationTool - Splitting: ORIGINAL
Group: Adgangskontroll, Innbruddsalarm
Name | 05_ID-nummer
Åpneknapp | +TS=543.060-QGXXX
Åpneknapp | +TS=543.063-QG0012
Åpneknapp | +TS=543.060-QG0021

# IfcFlowFitting: 10mm Radius (6)
In: Nivå F
Type - PredefinedType: TEE
ePset_LocationTool - Splitting: ORIGINAL
MagiCAD Pset_Cabletray - Width [mm]: 0 mm; Height [mm]: 0 mm; Length [mm]: 0 mm
ePset_Simplebim - Assembly Level: Leaf
Name | System code | Group
2 x 10mm Radius | 4111 | Bæresystem for elkraft
10mm Radius | 5111 | Bæresytem for tele- og automasjon
3 x 10mm Radius | 410 | Bæresystem generelt

# IfcFlowFitting: LEPR (20)
Type - PredefinedType: OBSTRUCTION
ePset_Simplebim - Assembly Level: Leaf
ePset_LocationTool - Splitting: ORIGINAL
Name | In | Group
LEPR | Nivå E | +TQ=360.010 A
2 x LEPR | Nivå E | 36= Tilluft 48
2 x LEPR | Nivå E | 36= Tilluft 363
2 x LEPR | Nivå E | 36= Tilluft 405
2 x LEPR | Nivå E | 36= Tilluft 406
2 x LEPR | Nivå E | 36= Tilluft 407
2 x LEPR | Nivå E | 36= Tilluft 408
2 x LEPR | Nivå E | 36= Tilluft 410
2 x LEPR | Nivå E | 36= Tilluft 411
2 x LEPR | Nivå F | +TQ=360.010 T
LEPR | Nivå F | +TQ=360.020 T

# IfcFlowFitting: Lindab TCPU
In: Nivå F
Type - PredefinedType: JUNCTION
ePset_LocationTool - Splitting: ORIGINAL
ePset_Simplebim - Assembly Level: Leaf
Group: +TS=652.001 2

# IfcFlowFitting: NedføringsStaver 300mm
In: Nivå F
ePset_Simplebim - Assembly Level: Leaf
ePset_LocationTool - Splitting: ORIGINAL
Group: Bæresystem generelt

# IfcFlowFitting: Standard (6)
In: Nivå F
Type - PredefinedType: BEND
ePset_Simplebim - Assembly Level: Leaf
ePset_LocationTool - Splitting: ORIGINAL
MagiCAD Pset_Cabletray - System code: 410; Width [mm]: 0 mm; Height [mm]: 0 mm; Length [mm]: 0 mm
Group: Bæresystem generelt

# IfcFlowFitting: Standard (2)
In: Nivå F
Type - PredefinedType: REDUCER
ePset_Simplebim - Assembly Level: Leaf
MagiCAD Pset_Cabletray - System code: 410; Width [mm]: 0 mm; Height [mm]: 0 mm; Length [mm]: 0 mm
ePset_LocationTool - Splitting: ORIGINAL
Group: Bæresystem generelt

# IfcFlowFitting: Standard 10mm (11)
Type - PredefinedType: BEND
ePset_LocationTool - Splitting: ORIGINAL
MagiCAD Pset_Cabletray - Width [mm]: 0 mm; Height [mm]: 0 mm; Length [mm]: 0 mm
ePset_Simplebim - Assembly Level: Leaf
Name | In | System code | Group
Standard 10mm | Nivå E | 4111 | Bæresystem for elkraft
5 x Standard 10mm | Nivå F | 4119 | Bæresystem generelt
5 x Standard 10mm | Nivå F | 410 | Bæresystem generelt

# IfcFlowFitting: TCPU
In: Nivå F
Type - Description: Small Roundings; PredefinedType: JUNCTION
ePset_LocationTool - Splitting: ORIGINAL
ePset_Simplebim - Assembly Level: Leaf
Group: +TQ=360.010 T

# IfcFlowFitting: WA (2)
In: Nivå F -0,7m
Type - PredefinedType: BEND
ePset_LocationTool - Splitting: ORIGINAL
ePset_Simplebim - Assembly Level: Leaf
Group: +TQ=360.010 A

# IfcFlowFitting: magi_pipe_cu_elbow_short_001
In: Nivå F
Type - PredefinedType: BEND
MagiCAD Pset_Elbow - Insulation_thickness_mm: 0 mm; qv_SizingFlow_ls: 0 m3/s; pTot_SizingFlow_Pa: 0 Pa; dpTot_SizingFlow_Pa: 0 Pa; v_SizingFlow_ms: 0 m/s; ConnectionSize_mm: 0 mm
ePset_Simplebim - Assembly Level: Leaf
ePset_LocationTool - Splitting: ORIGINAL

# IfcFlowFitting: magi_pipe_fe_cross_centric_90_001
In: Nivå F
Type - PredefinedType: JUNCTION
MagiCAD Pset_XBranch - Insulation_thickness_mm: 0 mm; qv_SizingFlow_ls: 0 m3/s; pTot_SizingFlow_Pa: 0 Pa; dpTot_SizingFlow_Pa: 0 Pa; v_SizingFlow_ms: 0 m/s; ConnectionSize_mm: 0 mm
ePset_LocationTool - Splitting: ORIGINAL
ePset_Simplebim - Assembly Level: Leaf
Group: +TQ=332.001

# IfcFlowFitting: magi_pipe_fe_elbow_short_001 (115)
In: Nivå F
Type - PredefinedType: BEND
MagiCAD Pset_Elbow - Insulation_thickness_mm: 0 mm; qv_SizingFlow_ls: 0 m3/s; pTot_SizingFlow_Pa: 0 Pa; dpTot_SizingFlow_Pa: 0 Pa; v_SizingFlow_ms: 0 m/s; ConnectionSize_mm: 0 mm
ePset_LocationTool - Splitting: ORIGINAL
ePset_Simplebim - Assembly Level: Leaf
Name | Group
54 x magi_pipe_fe_elbow_short_001 | 33= Våt Kopi 1
56 x magi_pipe_fe_elbow_short_001 | +TQ=332.001
5 x magi_pipe_fe_elbow_short_001 | +TS=332.007 - 1 (1)

# IfcFlowFitting: magi_pipe_fe_reducer_centric_short_001 (5)
In: Nivå F
Type - PredefinedType: TRANSITION
MagiCAD Pset_Reduction - Insulation_thickness_mm: 0 mm; qv_SizingFlow_ls: 0 m3/s; pTot_SizingFlow_Pa: 0 Pa; dpTot_SizingFlow_Pa: 0 Pa; v_SizingFlow_ms: 0 m/s; ConnectionSize_mm: 0 mm
ePset_Simplebim - Assembly Level: Leaf
ePset_LocationTool - Splitting: ORIGINAL
Group: 33= Våt Kopi 1

# IfcFlowFitting: magi_pipe_fe_reducer_centric_short_NOR (76)
Type - PredefinedType: TRANSITION
MagiCAD Pset_Reduction - Insulation_thickness_mm: 0 mm; qv_SizingFlow_ls: 0 m3/s; pTot_SizingFlow_Pa: 0 Pa; dpTot_SizingFlow_Pa: 0 Pa; v_SizingFlow_ms: 0 m/s; ConnectionSize_mm: 0 mm
ePset_LocationTool - Splitting: ORIGINAL
ePset_Simplebim - Assembly Level: Leaf
Name | In | Group
magi_pipe_fe_reducer_centric_short_NOR | Nivå E | 33= Våt Kopi 32
17 x magi_pipe_fe_reducer_centric_short_NOR | Nivå E | +TS=332.007 - 1 (1)
26 x magi_pipe_fe_reducer_centric_short_NOR | Nivå F | 33= Våt Kopi 1
28 x magi_pipe_fe_reducer_centric_short_NOR | Nivå F | +TQ=332.001
4 x magi_pipe_fe_reducer_centric_short_NOR | Nivå F | +TS=332.007 - 1 (1)

# IfcFlowFitting: magi_pipe_fe_tee_centric_90_NOR (66)
In: Nivå F
Type - PredefinedType: JUNCTION
ePset_LocationTool - Splitting: ORIGINAL
MagiCAD Pset_TBranch - Insulation_thickness_mm: 0 mm; qv_SizingFlow_ls: 0 m3/s; pTot_SizingFlow_Pa: 0 Pa; dpTot_SizingFlow_Pa: 0 Pa; v_SizingFlow_ms: 0 m/s; ConnectionSize_mm: 0 mm
ePset_Simplebim - Assembly Level: Leaf
Name | Group
27 x magi_pipe_fe_tee_centric_90_NOR | 33= Våt Kopi 1
38 x magi_pipe_fe_tee_centric_90_NOR | +TQ=332.001
magi_pipe_fe_tee_centric_90_NOR | +TS=332.007 - 1 (1)

# IfcFlowFitting: magicirc_elbow_full_radius_001 (42)
Type - Description: Circular, smooth,R=D; PredefinedType: BEND
ePset_LocationTool - Splitting: ORIGINAL
ePset_Simplebim - Assembly Level: Leaf
Name | In | Group
2 x magicirc_elbow_full_radius_001 | Nivå E | +TQ=360.020 A
magicirc_elbow_full_radius_001 | Nivå E | +TQ=360.010 A
magicirc_elbow_full_radius_001 | Nivå F -0,7m | +TQ=360.010 T
4 x magicirc_elbow_full_radius_001 | Nivå F -0,7m | +TQ=360.010 A
10 x magicirc_elbow_full_radius_001 | Nivå F | +TQ=360.010 A
14 x magicirc_elbow_full_radius_001 | Nivå F | +TS=652.001 2
10 x magicirc_elbow_full_radius_001 | Nivå F | +TQ=360.010 T

# IfcFlowFitting: magicirc_elbow_short_001 (56)
Type - PredefinedType: BEND
ePset_Simplebim - Assembly Level: Leaf
ePset_LocationTool - Splitting: ORIGINAL
Name | In | Group
2 x magicirc_elbow_short_001 | Nivå F -0,7m | +TQ=360.010 T
52 x magicirc_elbow_short_001 | Nivå F | +TQ=360.010 T
2 x magicirc_elbow_short_001 | Nivå F | +TS=652.001 2

# IfcFlowFitting: magicirc_plug_001 (16)
In: Nivå F
Type - Description: Circular; PredefinedType: OBSTRUCTION
ePset_Simplebim - Assembly Level: Leaf
ePset_LocationTool - Splitting: ORIGINAL
Name | Group
magicirc_plug_001 | +TQ=360.020 A
12 x magicirc_plug_001 | +TQ=360.010 A
3 x magicirc_plug_001 | +TQ=360.010 T

# IfcFlowFitting: magicirc_reduction_001 (11)
In: Nivå F
Type - Description: Circular, concentric and eccentric, 60 deg (short); PredefinedType: TRANSITION
ePset_LocationTool - Splitting: ORIGINAL
ePset_Simplebim - Assembly Level: Leaf
Group: +TQ=360.010 T

# IfcFlowFitting: magicirc_tapoutlet_001 (42)
Type - Description: Rectangular/circular; PredefinedType: CONNECTOR
ePset_Simplebim - Assembly Level: Leaf
ePset_LocationTool - Splitting: ORIGINAL
Name | In | Group | Description
magicirc_tapoutlet_001 | Nivå E | +TQ=360.010 A
magicirc_tapoutlet_001 | Nivå F -0,7m | +TQ=360.010 T | Påstikk
magicirc_tapoutlet_001 | Nivå F -0,7m | +TQ=360.010 A | Påstikk
2 x magicirc_tapoutlet_001 | Nivå F | +TQ=360.020 A | Påstikk
13 x magicirc_tapoutlet_001 | Nivå F | +TQ=360.010 A | Påstikk
21 x magicirc_tapoutlet_001 | Nivå F | +TQ=360.010 T | Påstikk
2 x magicirc_tapoutlet_001 | Nivå F | +TS=652.001 2
magicirc_tapoutlet_001 | Nivå F | +TQ=360.010 T

# IfcFlowFitting: magicirc_tee_centric_90_001 (4)
In: Nivå F
Type - PredefinedType: JUNCTION
ePset_Simplebim - Assembly Level: Leaf
ePset_LocationTool - Splitting: ORIGINAL
Group: +TQ=360.010 T

# IfcFlowFitting: magirect_outlet1_001
In: Nivå F -0,7m
Type - PredefinedType: CONNECTOR
ePset_Simplebim - Assembly Level: Leaf
ePset_LocationTool - Splitting: ORIGINAL
Group: +TQ=360.010 A

# IfcFlowFitting: magirect_outlet1_001 2 (5)
Type - PredefinedType: CONNECTOR
ePset_Simplebim - Assembly Level: Leaf
ePset_LocationTool - Splitting: ORIGINAL
Name | In | Group
magirect_outlet1_001 2 | Nivå E | +TQ=360.010 T
2 x magirect_outlet1_001 2 | Nivå E | +TQ=360.020 T
magirect_outlet1_001 2 | Nivå D | +TQ=360.010 A
magirect_outlet1_001 2 | Nivå F -0,7m | +TQ=360.010 A

# IfcFlowFitting: magirect_plug1_001 (4)
Type - PredefinedType: OBSTRUCTION
ePset_Simplebim - Assembly Level: Leaf
ePset_LocationTool - Splitting: ORIGINAL
Name | In | Group
2 x magirect_plug1_001 | Nivå D | +TQ=360.010 A
magirect_plug1_001 | Nivå F -0,7m | Mechanical +TU=360.032Avt 1
magirect_plug1_001 | Nivå F -0,7m | Mechanical +TU=360.032Avt 2

# IfcFlowSegment: Conduit (6)
In: Nivå F
Type - PredefinedType: CONDUITSEGMENT
ePset_LocationTool - Splitting: RESULT
ePset_Simplebim - Assembly Level: Leaf
ePset_SimplebimBasicQuantities - Height (Simplebim): 124 mm; Width (Simplebim): 124 mm
Name | Length (Simplebim) (mm) | System code | Group
Conduit | 8649 | 4114 | Trekkerør for elkraft
Conduit | 8667 | 4114 | Trekkerør for elkraft
2 x Conduit | 8667 | 5113 | Trekkerør for tele- og automasjon
2 x Conduit | 8651 | 5113 | Trekkerør for tele- og automasjon

# IfcFlowSegment: KK001T - Spiro kanaler, Forsinket stål (42)
Type - Description: Spiro kanaler, Forsinket stål; PredefinedType: RIGIDSEGMENT
Classification: VB2.121212 Not defined (NS3420)
ePset_LocationTool - Splitting: ORIGINAL
ePset_Simplebim - Assembly Level: Leaf
Name | In | Height (Simplebim) (mm) | Width (Simplebim) (mm) | Length (Simplebim) (mm) | Group
2 x KK001T - Spiro kanaler, Forsinket stål | Nivå E | 125 | 125 | 3243 | +TQ=360.020 A
6 x KK001T - Spiro kanaler, Forsinket stål | Nivå E | 125 | 125 | 3173 | +TQ=360.010 A
KK001T - Spiro kanaler, Forsinket stål | Nivå F -0,7m | 250 | 250 | 274.3 | +TQ=360.010 A
KK001T - Spiro kanaler, Forsinket stål | Nivå F -0,7m | 250 | 250 | 898.3 | +TQ=360.010 A
KK001T - Spiro kanaler, Forsinket stål | Nivå F -0,7m | 250 | 250 | 27.7 | +TQ=360.010 A
KK001T - Spiro kanaler, Forsinket stål | Nivå F -0,7m | 100.6 | 250 | 250 | +TQ=360.010 A
KK001T - Spiro kanaler, Forsinket stål | Nivå F -0,7m | 250 | 250 | 1023.4 | +TQ=360.010 A
KK001T - Spiro kanaler, Forsinket stål | Nivå F -0,7m | 250 | 250 | 353 | +TQ=360.010 A
KK001T - Spiro kanaler, Forsinket stål | Nivå F -0,7m | 250 | 250 | 112.6 | +TQ=360.010 A
KK001T - Spiro kanaler, Forsinket stål | Nivå F | 125 | 125 | 475.2 | +TQ=360.020 A
KK001T - Spiro kanaler, Forsinket stål | Nivå F | 125 | 125 | 65 | +TQ=360.020 A
KK001T - Spiro kanaler, Forsinket stål | Nivå F | 60 | 125 | 125 | +TQ=360.020 A
2 x KK001T - Spiro kanaler, Forsinket stål | Nivå F | 125 | 125 | 323.1 | +TQ=360.010 A
10 x KK001T - Spiro kanaler, Forsinket stål | Nivå F | 125 | 125 | 52.8 | +TQ=360.010 A
KK001T - Spiro kanaler, Forsinket stål | Nivå F | 125 | 125 | 321.7 | +TQ=360.010 A
KK001T - Spiro kanaler, Forsinket stål | Nivå F | 125 | 125 | 448.2 | +TQ=360.010 A
KK001T - Spiro kanaler, Forsinket stål | Nivå F | 125 | 125 | 321.1 | +TQ=360.010 A
KK001T - Spiro kanaler, Forsinket stål | Nivå F | 125 | 125 | 325 | +TQ=360.010 A
3 x KK001T - Spiro kanaler, Forsinket stål | Nivå F | 125 | 125 | 323.7 | +TQ=360.010 A
KK001T - Spiro kanaler, Forsinket stål | Nivå F | 125 | 125 | 81.9 | +TQ=360.010 A
KK001T - Spiro kanaler, Forsinket stål | Nivå F | 60 | 125 | 125 | +TQ=360.010 A
KK001T - Spiro kanaler, Forsinket stål | Nivå F | 125 | 125 | 43.1 | +TQ=360.010 A
KK001T - Spiro kanaler, Forsinket stål | Nivå F | 125 | 125 | 1260 | +TQ=360.010 A
KK001T - Spiro kanaler, Forsinket stål | Nivå F | 125 | 125 | 331.1 | +TQ=360.010 A

# IfcFlowSegment: KK002T - Rektangulære, Forsinket stål (18)
Type - Description: Rektangulære, Forsinket stål; PredefinedType: RIGIDSEGMENT
Classification: VB2.111212 Not defined (NS3420)
ePset_Simplebim - Assembly Level: Leaf
Name | In | Width (Simplebim) (mm) | Height (Simplebim) (mm) | Length (Simplebim) (mm) | Splitting | Group
KK002T - Rektangulære, Forsinket stål | Nivå E | 250 | 620 | 1800 | ORIGINAL | 36= Tilluft 48
KK002T - Rektangulære, Forsinket stål | Nivå E | 250 | 620 | 1800 | ORIGINAL | 36= Tilluft 363
KK002T - Rektangulære, Forsinket stål | Nivå E | 250 | 620 | 1800 | ORIGINAL | 36= Tilluft 405
KK002T - Rektangulære, Forsinket stål | Nivå E | 250 | 620 | 1800 | ORIGINAL | 36= Tilluft 406
KK002T - Rektangulære, Forsinket stål | Nivå E | 250 | 620 | 1800 | ORIGINAL | 36= Tilluft 407
KK002T - Rektangulære, Forsinket stål | Nivå E | 250 | 620 | 1800 | ORIGINAL | 36= Tilluft 408
KK002T - Rektangulære, Forsinket stål | Nivå E | 250 | 620 | 1800 | ORIGINAL | 36= Tilluft 410
KK002T - Rektangulære, Forsinket stål | Nivå E | 250 | 620 | 1800 | ORIGINAL | 36= Tilluft 411
KK002T - Rektangulære, Forsinket stål | Nivå E | 70 | 270 | 3026.5 | ORIGINAL | +TQ=360.010 T
2 x KK002T - Rektangulære, Forsinket stål | Nivå E | 70 | 250 | 1313.5 | ORIGINAL | +TQ=360.020 T
KK002T - Rektangulære, Forsinket stål | Nivå F -0,7m | 400 | 180 | 439.3 | ORIGINAL | +TQ=360.010 A
KK002T - Rektangulære, Forsinket stål | Nivå F | 300 | 300 | 115 | ORIGINAL | +TQ=360.010 T
KK002T - Rektangulære, Forsinket stål | Nivå F | 600 | 400 | 10580.1 | ORIGINAL | +TQ=360.010 T
KK002T - Rektangulære, Forsinket stål | Nivå F | 125 | 600 | 900 | ORIGINAL | +TQ=360.020 T
KK002T - Rektangulære, Forsinket stål | Nivå F | 400 | 143.6 | 400 | ORIGINAL | +TQ=360.010 T
KK002T - Rektangulære, Forsinket stål | Nivå F | 400 | 150.2 | 400 | ORIGINAL | +TQ=360.010 T
KK002T - Rektangulære, Forsinket stål | Nivå E | 50 | 98 | 3371 | RESULT | +TQ=360.010 A

# IfcFlowSegment: KK002T - Spiro kanaler, Forsinket stål, korte bend (96)
Type - Description: Spiro kanaler, Forsinket stål; PredefinedType: RIGIDSEGMENT
Classification: VB2.121212 Not defined (NS3420); Group: +TQ=360.010 T
ePset_LocationTool - Splitting: ORIGINAL
ePset_Simplebim - Assembly Level: Leaf
Name | In | Length (Simplebim) (mm) | Height (Simplebim) (mm) | Width (Simplebim) (mm)
KK002T - Spiro kanaler, Forsinket stål, korte bend | Nivå F -0,7m | 390.1 | 200 | 200
KK002T - Spiro kanaler, Forsinket stål, korte bend | Nivå F -0,7m | 1008.9 | 200 | 200
KK002T - Spiro kanaler, Forsinket stål, korte bend | Nivå F -0,7m | 87.8 | 200 | 200
KK002T - Spiro kanaler, Forsinket stål, korte bend | Nivå F -0,7m | 136 | 200 | 200
13 x KK002T - Spiro kanaler, Forsinket stål, korte bend | Nivå F | 250 | 76 | 250
14 x KK002T - Spiro kanaler, Forsinket stål, korte bend | Nivå F | 215 | 250 | 250
4 x KK002T - Spiro kanaler, Forsinket stål, korte bend | Nivå F | 1334.8 | 250 | 250
3 x KK002T - Spiro kanaler, Forsinket stål, korte bend | Nivå F | 1337.6 | 250 | 250
3 x KK002T - Spiro kanaler, Forsinket stål, korte bend | Nivå F | 1894.5 | 250 | 250
4 x KK002T - Spiro kanaler, Forsinket stål, korte bend | Nivå F | 1811 | 315 | 315
4 x KK002T - Spiro kanaler, Forsinket stål, korte bend | Nivå F | 74.5 | 315 | 315
2 x KK002T - Spiro kanaler, Forsinket stål, korte bend | Nivå F | 156 | 315 | 315
KK002T - Spiro kanaler, Forsinket stål, korte bend | Nivå F | 1367.9 | 250 | 250
2 x KK002T - Spiro kanaler, Forsinket stål, korte bend | Nivå F | 315 | 201 | 315
2 x KK002T - Spiro kanaler, Forsinket stål, korte bend | Nivå F | 1480 | 250 | 250
KK002T - Spiro kanaler, Forsinket stål, korte bend | Nivå F | 750 | 250 | 250
2 x KK002T - Spiro kanaler, Forsinket stål, korte bend | Nivå F | 2002.9 | 250 | 250
2 x KK002T - Spiro kanaler, Forsinket stål, korte bend | Nivå F | 793.6 | 250 | 250
KK002T - Spiro kanaler, Forsinket stål, korte bend | Nivå F | 1338.9 | 250 | 250
KK002T - Spiro kanaler, Forsinket stål, korte bend | Nivå F | 2001.2 | 250 | 250
KK002T - Spiro kanaler, Forsinket stål, korte bend | Nivå F | 2535 | 125 | 125
KK002T - Spiro kanaler, Forsinket stål, korte bend | Nivå F | 445 | 125 | 125
KK002T - Spiro kanaler, Forsinket stål, korte bend | Nivå F | 1435 | 125 | 125
KK002T - Spiro kanaler, Forsinket stål, korte bend | Nivå F | 443.5 | 125 | 125
KK002T - Spiro kanaler, Forsinket stål, korte bend | Nivå F | 505.2 | 125 | 125
KK002T - Spiro kanaler, Forsinket stål, korte bend | Nivå F | 485 | 200 | 200
4 x KK002T - Spiro kanaler, Forsinket stål, korte bend | Nivå F | 373.9 | 200 | 200
KK002T - Spiro kanaler, Forsinket stål, korte bend | Nivå F | 3165.4 | 250 | 250
KK002T - Spiro kanaler, Forsinket stål, korte bend | Nivå F | 961.3 | 200 | 200
KK002T - Spiro kanaler, Forsinket stål, korte bend | Nivå F | 519.2 | 200 | 200
KK002T - Spiro kanaler, Forsinket stål, korte bend | Nivå F | 352.9 | 200 | 200
KK002T - Spiro kanaler, Forsinket stål, korte bend | Nivå F | 893.6 | 200 | 200
KK002T - Spiro kanaler, Forsinket stål, korte bend | Nivå F | 91.3 | 200 | 200
KK002T - Spiro kanaler, Forsinket stål, korte bend | Nivå F | 161.7 | 200 | 200
4 x KK002T - Spiro kanaler, Forsinket stål, korte bend | Nivå F | 178.1 | 200 | 200
KK002T - Spiro kanaler, Forsinket stål, korte bend | Nivå F | 3220 | 250 | 250
3 x KK002T - Spiro kanaler, Forsinket stål, korte bend | Nivå F | 92.8 | 200 | 200
KK002T - Spiro kanaler, Forsinket stål, korte bend | Nivå F | 777.6 | 200 | 200
KK002T - Spiro kanaler, Forsinket stål, korte bend | Nivå F | 2057 | 200 | 200
KK002T - Spiro kanaler, Forsinket stål, korte bend | Nivå F | 1435.7 | 315 | 315
KK002T - Spiro kanaler, Forsinket stål, korte bend | Nivå F | 263.4 | 200 | 200
KK002T - Spiro kanaler, Forsinket stål, korte bend | Nivå F | 919.7 | 315 | 315
KK002T - Spiro kanaler, Forsinket stål, korte bend | Nivå F | 845.6 | 200 | 200
KK002T - Spiro kanaler, Forsinket stål, korte bend | Nivå F | 1289.1 | 250 | 250
KK002T - Spiro kanaler, Forsinket stål, korte bend | Nivå F | 550 | 250 | 250

# IfcFlowSegment: Kabelbane (23)
In: Nivå F
Type - PredefinedType: CABLETRAYSEGMENT
ePset_SimplebimBasicQuantities - Height (Simplebim): 50 mm; Width (Simplebim): 350 mm
ePset_Simplebim - Assembly Level: Leaf
MagiCAD Pset_Cabletray - System code: 410
Group: Bæresystem generelt
Name | Length (Simplebim) (mm) | Splitting | NominalLength (mm) = Length [mm] (mm) | NominalHeight (mm) = Height [mm] (mm) | NominalWidth (mm) = Width [mm] (mm)
Kabelbane | 1625.79 | ORIGINAL | 1625.79 | 50 | 350
2 x Kabelbane | 2614.56 | ORIGINAL | 2614.56 | 50 | 350
Kabelbane | 2622.38 | ORIGINAL | 2622.38 | 50 | 350
Kabelbane | 2620 | ORIGINAL | 2620 | 50 | 350
Kabelbane | 2608.97 | ORIGINAL | 2608.97 | 50 | 350
Kabelbane | 2592.86 | ORIGINAL | 2592.86 | 50 | 350
2 x Kabelbane | 11584.7 | ORIGINAL | 11584.7 | 50 | 350
Kabelbane | 1600 | ORIGINAL | 1600 | 50 | 350
Kabelbane | 2155 | ORIGINAL | 2155 | 50 | 350
Kabelbane | 2179.54 | ORIGINAL | 2179.54 | 50 | 350
Kabelbane | 12784 | RESULT
3 x Kabelbane | 12750 | RESULT
Kabelbane | 12749 | RESULT
2 x Kabelbane | 2636 | RESULT
2 x Kabelbane | 774 | RESULT
Kabelbane | 14761 | RESULT
Kabelbane | 2484 | RESULT

# IfcFlowSegment: Kabelbro (37)
Type - PredefinedType: CABLELADDERSEGMENT
ePset_Simplebim - Assembly Level: Leaf
Name | In | Splitting | NominalLength (mm) = Length [mm] (mm) | NominalHeight (mm) = Height [mm] (mm) | NominalWidth (mm) = Width [mm] (mm) | Length (Simplebim) (mm) | Height (Simplebim) (mm) | Width (Simplebim) (mm) | System code | Group
Kabelbro | Nivå F | ORIGINAL | 8199.26 | 60 | 300 | 8199.26 | 60 | 300 | 4111 | Bæresystem for elkraft
Kabelbro | Nivå F | ORIGINAL | 8321.04 | 60 | 300 | 8321.04 | 60 | 300 | 4111 | Bæresystem for elkraft
Kabelbro | Nivå F | ORIGINAL | 1472.8 | 60 | 600 | 1472.8 | 60 | 600 | 4111 | Bæresystem for elkraft
Kabelbro | Nivå F | ORIGINAL | 2580.25 | 60 | 600 | 2580.25 | 60 | 600 | 5111 | Bæresytem for tele- og automasjon
Kabelbro | Nivå F | ORIGINAL | 36.171 | 60 | 600 | 600 | 60 | 36.1709 | 5111 | Bæresytem for tele- og automasjon
Kabelbro | Nivå F | ORIGINAL | 2461.4 | 60 | 600 | 2461.4 | 60 | 600 | 4111 | Bæresystem for elkraft
Kabelbro | Nivå F | ORIGINAL | 2260 | 60 | 300 | 2260 | 60 | 300 | 410 | Bæresystem for elkraft
Kabelbro | Nivå F | ORIGINAL | 4923.27 | 60 | 400 | 4923.27 | 60 | 400 | 410 | Bæresystem generelt
Kabelbro | Nivå F | ORIGINAL | 8429.43 | 60 | 300 | 8429.43 | 60 | 300 | 410 | Bæresystem generelt
Kabelbro | Nivå F | ORIGINAL | 236.706 | 60 | 400 | 400 | 60 | 236.706 | 410 | Bæresystem generelt
Kabelbro | Nivå F | ORIGINAL | 1917.28 | 60 | 400 | 1917.28 | 60 | 400 | 410 | Bæresystem generelt
4 x Kabelbro | Nivå F | ORIGINAL | 236.706 | 60 | 300 | 300 | 60 | 236.706 | 410 | Bæresystem generelt
Kabelbro | Nivå F | ORIGINAL | 1451.42 | 60 | 300 | 1451.42 | 60 | 300 | 410 | Bæresystem generelt
Kabelbro | Nivå F | ORIGINAL | 3174.79 | 60 | 300 | 3174.79 | 60 | 300 | 410 | Bæresystem generelt
Kabelbro | Nivå F | ORIGINAL | 4989 | 60 | 300 | 4989 | 60 | 300 | 410 | Bæresystem for elkraft
Kabelbro | Nivå F | ORIGINAL | 1849.43 | 60 | 300 | 1849.43 | 60 | 300 | 410 | Bæresystem generelt
Kabelbro | Nivå F | ORIGINAL | 1138 | 60 | 300 | 1138 | 60 | 300 | 410 | Bæresystem generelt
Kabelbro | Nivå F | ORIGINAL | 4438.35 | 60 | 300 | 4438.35 | 60 | 300 | 410 | Bæresystem generelt
Kabelbro | Nivå F | ORIGINAL | 3869 | 60 | 300 | 3869 | 60 | 300 | 410 | Bæresystem for elkraft
Kabelbro | Nivå F | ORIGINAL | 1469 | 60 | 300 | 1469 | 60 | 300 | 410 | Bæresystem generelt
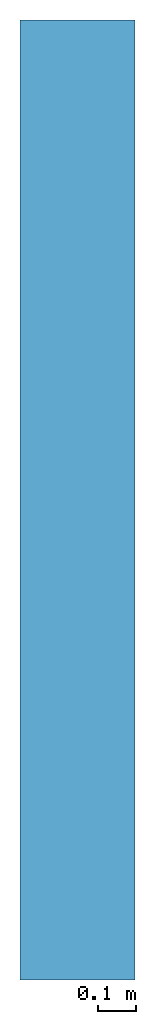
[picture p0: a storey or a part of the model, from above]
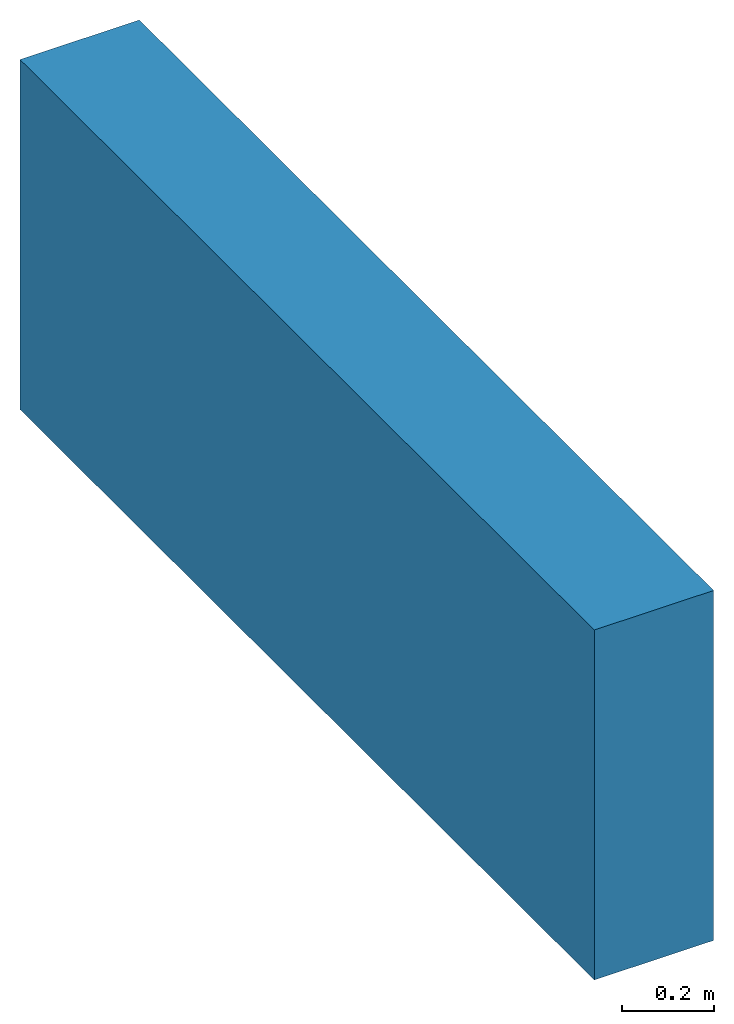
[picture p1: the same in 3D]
Properties of the parts of a building model (IFC2X3), part 2 of 4

# IfcFlowSegment: Kabelbro (37)
Name | In | Splitting | NominalLength (mm) = Length [mm] (mm) | NominalHeight (mm) = Height [mm] (mm) | NominalWidth (mm) = Width [mm] (mm) | Length (Simplebim) (mm) | Height (Simplebim) (mm) | Width (Simplebim) (mm) | System code | Group
Kabelbro | Nivå F | ORIGINAL | 2077.95 | 60 | 300 | 2077.95 | 60 | 300 | 410 | Bæresystem generelt
Kabelbro | Nivå F | ORIGINAL | 5106.79 | 60 | 300 | 5106.79 | 60 | 300 | 410 | Bæresystem generelt
Kabelbro | Nivå F | ORIGINAL | 338.095 | 60 | 300 | 338.095 | 60 | 300 | 410 | Bæresystem generelt
Kabelbro | Nivå F | ORIGINAL | 351.454 | 60 | 300 | 351.454 | 60 | 300 | 410 | Bæresystem generelt
Kabelbro | Nivå F | ORIGINAL | 455.431 | 60 | 300 | 455.431 | 60 | 300 | 410 | Bæresystem generelt
Kabelbro | Nivå F | ORIGINAL | 695.144 | 60 | 400 | 695.144 | 60 | 400 | 4110 | Bæresystem generelt
Kabelbro | Nivå F | ORIGINAL | 767.165 | 60 | 400 | 767.165 | 60 | 400 | 410 | Bæresystem generelt
Kabelbro | Nivå F | ORIGINAL | 1780 | 100 | 400 | 1780 | 400 | 100 | 410 | Bæresystem generelt
Kabelbro | Nivå F - 0,7 m | ORIGINAL | 1320 | 60 | 400 | 1320 | 400 | 60 | 4110 | Bæresystem generelt
Kabelbro | Nivå E | RESULT |  |  |  | 600 | 365 | 60 | 4111 | Bæresystem for elkraft
Kabelbro | Nivå F | RESULT |  |  |  | 6837 | 60 | 300 | 4111 | Bæresystem for elkraft
Kabelbro | Nivå F | RESULT |  |  |  | 14504 | 60 | 300 | 410 | Bæresystem generelt
2 x Kabelbro | Nivå F | RESULT |  |  |  | 732 | 60 | 300 | 4111 | Bæresystem for elkraft

# IfcFlowSegment: Rectangular duct (8)
Type - Description: Rectangular duct; PredefinedType: RIGIDSEGMENT
ePset_Simplebim - Assembly Level: Leaf
Name | In | Splitting | Length (Simplebim) (mm) | Width (Simplebim) (mm) | Height (Simplebim) (mm) | Group
Rectangular duct | Nivå D | ORIGINAL | 884.7 | 300 | 800 | +TQ=360.010 A
Rectangular duct | Nivå D | ORIGINAL | 1180 | 300 | 600 | +TQ=360.010 A
Rectangular duct | Nivå D | ORIGINAL | 800 | 300 | 305.5 | +TQ=360.010 A
Rectangular duct | Nivå D | ORIGINAL | 1461.3 | 300 | 800 | +TQ=360.010 A
Rectangular duct | Nivå F -0,7m | ORIGINAL | 400 | 296.5 | 180 | +TQ=360.010 A
Rectangular duct | Nivå F -0,7m | ORIGINAL | 1285 | 400 | 180 | +TQ=360.010 A
Rectangular duct | Nivå F -0,7m | ORIGINAL | 400 | 299.9 | 180 | +TQ=360.010 A
Rectangular duct | Nivå F | RESULT | 1394 | 1000 | 400 | +TQ=360.010 T

# IfcFlowSegment: Rektangulær kanal (2)
In: Nivå F -0,7m
Type - Description: Rektangulær kanal, forsinket stål; PredefinedType: RIGIDSEGMENT
ePset_SimplebimBasicQuantities - Width (Simplebim): 250 mm; Length (Simplebim): 500 mm
ePset_Simplebim - Assembly Level: Leaf
ePset_LocationTool - Splitting: ORIGINAL
Name | Height (Simplebim) (mm) | Group
Rektangulær kanal | 240 | Mechanical +TU=360.032Avt 1
Rektangulær kanal | 260 | Mechanical +TU=360.032Avt 2

# IfcFlowSegment: SSt (6)
In: Nivå F
Type - PredefinedType: RIGIDSEGMENT
MagiCAD Pset_Pipe - SystemType: 33 Brannslokking våt; SystemClass: Fire Protection Wet; SystemName: 33= Våt Kopi 1; Material: Rustfritt stål - systemrør; Insulation_thickness_mm: 0 mm; qv_SizingFlow_ls: 0 m3/s; User Code: SSt
MagiCAD Pset_Water - dpTot_SizingFlow_kPa: 0 Pa; pTot_SizingFlow_kPa: 0 Pa; v_SizingFlow_ms: 0 m/s
MagiCAD Pset_Heating - v_SizingFlow_ms: 0 m/s; pTot_SizingFlow_kPa: 0 Pa; dpTot_SizingFlow_kPa: 0 Pa
ePset_Simplebim - Assembly Level: Leaf
ePset_LocationTool - Splitting: ORIGINAL
Group: 33= Våt Kopi 1
Name | ConnectionSize_mm (mm) = Height (Simplebim) (mm) = Width (Simplebim) (mm) | Length_mm (mm) | Length (Simplebim) (mm)
SSt | 54 | 1918 | 1918
SSt | 28 | 365.017 | 365
2 x SSt | 28 | 352.517 | 352.5
SSt | 54 | 1944 | 1944
SSt | 54 | 488 | 488

# IfcFlowSegment: Sirkulær kanal (39)
Type - Description: Sirkulær kanal, forsinket stål; PredefinedType: RIGIDSEGMENT
ePset_Simplebim - Assembly Level: Leaf
Name | In | Height (Simplebim) (mm) | Width (Simplebim) (mm) | Length (Simplebim) (mm) | Splitting | Group
Sirkulær kanal | Nivå E | 125 | 125 | 3173 | ORIGINAL | +TQ=360.010 A
Sirkulær kanal | Nivå E | 125 | 125 | 3192.5 | ORIGINAL | +TQ=360.010 A
Sirkulær kanal | Nivå F -0,7m | 200 | 200 | 140 | ORIGINAL | +TQ=360.010 T
Sirkulær kanal | Nivå F | 50 | 50 | 113 | ORIGINAL | +TS=652.001 2
Sirkulær kanal | Nivå F | 50 | 50 | 1408.6 | ORIGINAL | +TS=652.001 2
Sirkulær kanal | Nivå F | 50 | 50 | 125 | ORIGINAL | +TS=652.001 2
Sirkulær kanal | Nivå F | 50 | 50 | 160 | ORIGINAL | +TS=652.001 2
Sirkulær kanal | Nivå F | 50 | 50 | 213.6 | ORIGINAL | +TS=652.001 2
Sirkulær kanal | Nivå F | 50 | 50 | 558.6 | ORIGINAL | +TS=652.001 2
Sirkulær kanal | Nivå F | 50 | 50 | 175.4 | ORIGINAL | +TS=652.001 2
Sirkulær kanal | Nivå F | 50 | 50 | 90 | ORIGINAL | +TS=652.001 2
Sirkulær kanal | Nivå F | 50 | 50 | 325.9 | ORIGINAL | +TS=652.001 2
Sirkulær kanal | Nivå F | 50 | 50 | 36.4 | ORIGINAL | +TS=652.001 2
Sirkulær kanal | Nivå F | 50 | 50 | 9309.3 | ORIGINAL | +TS=652.001 2
Sirkulær kanal | Nivå F | 50 | 50 | 8755.7 | ORIGINAL | +TS=652.001 2
Sirkulær kanal | Nivå F | 50 | 50 | 114.8 | ORIGINAL | +TS=652.001 2
Sirkulær kanal | Nivå F | 400 | 400 | 3626.8 | ORIGINAL | +TQ=360.010 T
Sirkulær kanal | Nivå F | 315 | 315 | 341 | ORIGINAL | +TQ=360.010 T
Sirkulær kanal | Nivå F | 315 | 315 | 3102.2 | ORIGINAL | +TQ=360.010 T
Sirkulær kanal | Nivå F | 315 | 315 | 393.9 | ORIGINAL | +TQ=360.010 T
Sirkulær kanal | Nivå F | 315 | 315 | 183.5 | ORIGINAL | +TQ=360.010 T
Sirkulær kanal | Nivå F | 315 | 315 | 1630.1 | ORIGINAL | +TQ=360.010 T
Sirkulær kanal | Nivå F | 315 | 315 | 760.1 | ORIGINAL | +TQ=360.010 T
Sirkulær kanal | Nivå F | 315 | 315 | 470 | ORIGINAL | +TQ=360.010 T
Sirkulær kanal | Nivå F | 315 | 315 | 98 | ORIGINAL | +TQ=360.010 T
Sirkulær kanal | Nivå F | 315 | 315 | 862.5 | ORIGINAL | +TQ=360.010 T
Sirkulær kanal | Nivå F | 315 | 315 | 182.9 | ORIGINAL | +TQ=360.010 T
Sirkulær kanal | Nivå F | 315 | 315 | 497.1 | ORIGINAL | +TQ=360.010 T
Sirkulær kanal | Nivå F | 315 | 315 | 130.6 | ORIGINAL | +TQ=360.010 T
Sirkulær kanal | Nivå F | 315 | 315 | 396.2 | ORIGINAL | +TQ=360.010 T
Sirkulær kanal | Nivå F | 315 | 315 | 50 | ORIGINAL | +TQ=360.010 T
Sirkulær kanal | Nivå F | 315 | 315 | 14.5 | ORIGINAL | +TQ=360.010 T
Sirkulær kanal | Nivå F | 50 | 50 | 1735 | RESULT | +TS=652.001 2
Sirkulær kanal | Nivå F | 45 | 50 | 1410 | RESULT | +TS=652.001 2
Sirkulær kanal | Nivå F | 50 | 50 | 1595 | RESULT | +TS=652.001 2
4 x Sirkulær kanal | Nivå E | 124 | 124 | 3038 | RESULT | +TQ=360.010 A

# IfcFlowSegment: Stålrør normaltykke (269)
Type - PredefinedType: RIGIDSEGMENT
Classification: UB3.144613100 Not defined (NS3420)
ePset_Simplebim - Assembly Level: Leaf
MagiCAD Pset_Pipe - SystemClass: Fire Protection Wet; NationalCode: UB3.144613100; Product variable 1: DN; User Code: DN; Material: Stålrør normaltykke
Name | In | MagiCAD Pset_Water, dpTot_SizingFlow_kPa (Pa) = MagiCAD Pset_Water, pTot_SizingFlow_kPa (Pa) = MagiCAD Pset_Water, v_SizingFlow_ms (m/s) = MagiCAD Pset_Heating, pTot_SizingFlow_kPa (Pa) = MagiCAD Pset_Heating, dpTot_SizingFlow_kPa (Pa) = Insulation_thickness_mm (mm) = qv_SizingFlow_ls (m3/s) | MagiCAD Pset_Heating, v_SizingFlow_ms (m/s) | Width (Simplebim) (mm) | Height (Simplebim) (mm) | Length (Simplebim) (mm) | SystemType | SystemName = Group | ConnectionSize_mm (mm) | Length_mm (mm) | Splitting
Stålrør normaltykke | Nivå F | 0 | 0 | 60.2 | 60.2 | 2271.6 | 33 Brannslokking våt | 33= Våt Kopi 1 | 50 | 2271.64 | ORIGINAL
Stålrør normaltykke | Nivå F | 0 | 0 | 60.2 | 60.2 | 75.5 | 33 Brannslokking våt | 33= Våt Kopi 1 | 50 | 76.118 | ORIGINAL
Stålrør normaltykke | Nivå F | 0 | 0 | 76 | 76 | 1585.7 | 33 Brannslokking våt | 33= Våt Kopi 1 | 65 | 1585.67 | ORIGINAL
Stålrør normaltykke | Nivå F | 0 | 0 | 76 | 76 | 13.4 | 33 Brannslokking våt | 33= Våt Kopi 1 | 65 | 12.755 | ORIGINAL
Stålrør normaltykke | Nivå F | 0 | 0 | 60.2 | 60.2 | 7.1 | 33 Brannslokking våt | 33= Våt Kopi 1 | 50 | 6.977 | ORIGINAL
Stålrør normaltykke | Nivå F | 0 | 0 | 76 | 76 | 1061.2 | 33 Brannslokking våt | 33= Våt Kopi 1 | 65 | 1061.23 | ORIGINAL
Stålrør normaltykke | Nivå F | 0 | 0 | 60.2 | 4.4 | 60.2 | 33 Brannslokking våt | 33= Våt Kopi 1 | 50 | 4.355 | ORIGINAL
Stålrør normaltykke | Nivå F | 0 | 0 | 76 | 76 | 1359.7 | SPRINKEL | +TQ=332.001 | 65 | 1359.74 | ORIGINAL
Stålrør normaltykke | Nivå F | 0 | 0 | 60.2 | 60.2 | 63.1 | SPRINKEL | +TQ=332.001 | 50 | 63.1 | ORIGINAL
Stålrør normaltykke | Nivå F | 0 | 0 | 76 | 76 | 1796.3 | SPRINKEL | +TQ=332.001 | 65 | 1796.28 | ORIGINAL
Stålrør normaltykke | Nivå F | 0 | 0 | 76 | 76 | 6.1 | SPRINKEL | +TQ=332.001 | 65 | 6.382 | ORIGINAL
Stålrør normaltykke | Nivå F | 0 | 0 | 76 | 76 | 49.6 | SPRINKEL | +TQ=332.001 | 65 | 50.011 | ORIGINAL
Stålrør normaltykke | Nivå F | 0 | 0 | 76 | 76 | 4472.2 | SPRINKEL | +TQ=332.001 | 65 | 4472.19 | ORIGINAL
Stålrør normaltykke | Nivå F | 0 | 0 | 76 | 76 | 2535.1 | SPRINKEL | +TQ=332.001 | 65 | 2535.11 | ORIGINAL
Stålrør normaltykke | Nivå F | 0 | 0 | 76 | 76 | 269.8 | SPRINKEL | +TQ=332.001 | 65 | 270.266 | ORIGINAL
Stålrør normaltykke | Nivå F | 0 | 0 | 33.8 | 33.8 | 455.8 | SPRINKEL | +TQ=332.001 | 25 | 455.6 | ORIGINAL
Stålrør normaltykke | Nivå F | 0 | 0 | 42.4 | 42.4 | 555.1 | SPRINKEL | +TQ=332.001 | 32 | 555.259 | ORIGINAL
Stålrør normaltykke | Nivå F | 0 | 0 | 48.2 | 48.2 | 1128.7 | SPRINKEL | +TQ=332.001 | 40 | 1128.74 | ORIGINAL
Stålrør normaltykke | Nivå F | 0 | 0 | 76 | 76 | 1781.5 | SPRINKEL | +TQ=332.001 | 65 | 1781.5 | ORIGINAL
Stålrør normaltykke | Nivå F | 0 | 0 | 33.8 | 33.8 | 1011.7 | SPRINKEL | +TQ=332.001 | 25 | 1012.4 | ORIGINAL
Stålrør normaltykke | Nivå F | 0 | 0 | 76 | 76 | 859.3 | SPRINKEL | +TQ=332.001 | 65 | 859.123 | ORIGINAL
3 x Stålrør normaltykke | Nivå F | 0 | 0 | 33.8 | 33.8 | 2335.1 | SPRINKEL | +TQ=332.001 | 25 | 2335.14 | ORIGINAL
8 x Stålrør normaltykke | Nivå F | 0 | 0 | 33.8 | 33.8 | 427.4 | SPRINKEL | +TQ=332.001 | 25 | 427.207 | ORIGINAL
8 x Stålrør normaltykke | Nivå F | 0 | 0 | 33.8 | 33.8 | 297.1 | SPRINKEL | +TQ=332.001 | 25 | 296.948 | ORIGINAL
Stålrør normaltykke | Nivå F | 0 | 0 | 76 | 76 | 1465.9 | SPRINKEL | +TQ=332.001 | 65 | 1465.94 | ORIGINAL
Stålrør normaltykke | Nivå F | 0 | 0 | 60.2 | 60.2 | 1129.9 | 33 Brannslokking våt | 33= Våt Kopi 1 | 50 | 1130.16 | ORIGINAL
Stålrør normaltykke | Nivå F | 0 | 0 | 76 | 76 | 2925.3 | SPRINKEL | +TQ=332.001 | 65 | 2925.3 | ORIGINAL
Stålrør normaltykke | Nivå F | 0 | 0 | 76 | 76 | 558.4 | 33 Brannslokking våt | 33= Våt Kopi 1 | 65 | 558.438 | ORIGINAL
2 x Stålrør normaltykke | Nivå F | 0 | 0 | 33.8 | 33.8 | 2927.4 | 33 Brannslokking våt | 33= Våt Kopi 1 | 25 | 2927.14 | ORIGINAL
Stålrør normaltykke | Nivå F | 0 | 0 | 60.2 | 60.2 | 819.9 | 33 Brannslokking våt | 33= Våt Kopi 1 | 50 | 819.884 | ORIGINAL
Stålrør normaltykke | Nivå F | 0 | 0 | 33.8 | 33.8 | 52.3 | 33 Brannslokking våt | 33= Våt Kopi 1 | 25 | 52.4 | ORIGINAL
Stålrør normaltykke | Nivå F | 0 | 0 | 33.8 | 33.8 | 435.6 | 33 Brannslokking våt | 33= Våt Kopi 1 | 25 | 436.24 | ORIGINAL
3 x Stålrør normaltykke | Nivå F | 0 | 0 | 33.8 | 33.8 | 1151.1 | 33 Brannslokking våt | 33= Våt Kopi 1 | 25 | 1151.05 | ORIGINAL
Stålrør normaltykke | Nivå F | 0 | 0 | 60.2 | 60.2 | 1330.9 | 33 Brannslokking våt | 33= Våt Kopi 1 | 50 | 1330.93 | ORIGINAL
Stålrør normaltykke | Nivå F | 0 | 0 | 33.8 | 33.8 | 325.4 | 33 Brannslokking våt | 33= Våt Kopi 1 | 25 | 324.848 | ORIGINAL
Stålrør normaltykke | Nivå F | 0 | 0 | 60.2 | 60.2 | 815.1 | 33 Brannslokking våt | 33= Våt Kopi 1 | 50 | 815.045 | ORIGINAL
Stålrør normaltykke | Nivå F | 0 | 0 | 33.8 | 33.8 | 712.5 | 33 Brannslokking våt | 33= Våt Kopi 1 | 25 | 712.4 | ORIGINAL
Stålrør normaltykke | Nivå F | 0 | 0 | 60.2 | 60.2 | 632.1 | 33 Brannslokking våt | 33= Våt Kopi 1 | 50 | 632.427 | ORIGINAL
Stålrør normaltykke | Nivå F | 0 | 0 | 33.8 | 33.8 | 432.4 | 33 Brannslokking våt | 33= Våt Kopi 1 | 25 | 432.045 | ORIGINAL
Stålrør normaltykke | Nivå F | 0 | 0 | 33.8 | 33.8 | 440 | 33 Brannslokking våt | 33= Våt Kopi 1 | 25 | 440.495 | ORIGINAL
Stålrør normaltykke | Nivå F | 0 | 0 | 33.8 | 33.8 | 1162.8 | 33 Brannslokking våt | 33= Våt Kopi 1 | 25 | 1162.55 | ORIGINAL
Stålrør normaltykke | Nivå F | 0 | 0 | 60.2 | 60.2 | 2732.4 | 33 Brannslokking våt | 33= Våt Kopi 1 | 50 | 2732.21 | ORIGINAL
Stålrør normaltykke | Nivå F | 0 | 0 | 33.8 | 33.8 | 131.4 | 33 Brannslokking våt | 33= Våt Kopi 1 | 25 | 131.083 | ORIGINAL
2 x Stålrør normaltykke | Nivå F | 0 | 0 | 76 | 76 | 817 | SPRINKEL | +TQ=332.001 | 65 | 816.96 | ORIGINAL
3 x Stålrør normaltykke | Nivå F | 0 | 0 | 33.8 | 33.8 | 141.7 | SPRINKEL | +TQ=332.001 | 25 | 142.4 | ORIGINAL
3 x Stålrør normaltykke | Nivå F | 0 | 0 | 33.8 | 33.8 | 151.4 | SPRINKEL | +TQ=332.001 | 25 | 150.85 | ORIGINAL
3 x Stålrør normaltykke | Nivå F | 0 | 0 | 33.8 | 33.8 | 682.6 | SPRINKEL | +TQ=332.001 | 25 | 682.591 | ORIGINAL
2 x Stålrør normaltykke | Nivå F | 0 | 0 | 76 | 76 | 2745.1 | SPRINKEL | +TQ=332.001 | 65 | 2745.07 | ORIGINAL
Stålrør normaltykke | Nivå F | 0 | 0 | 76 | 76 | 2334.6 | SPRINKEL | +TQ=332.001 | 65 | 2335.14 | ORIGINAL
2 x Stålrør normaltykke | Nivå F | 0 | 0 | 33.8 | 33.8 | 119.4 | SPRINKEL | +TQ=332.001 | 25 | 119.05 | ORIGINAL
Stålrør normaltykke | Nivå F | 0 | 0 | 76 | 76 | 682.6 | SPRINKEL | +TQ=332.001 | 65 | 682.591 | ORIGINAL
Stålrør normaltykke | Nivå F | 0 | 0 | 76 | 76 | 2547.3 | SPRINKEL | +TQ=332.001 | 65 | 2547.26 | ORIGINAL
Stålrør normaltykke | Nivå F | 0 | 0 | 76 | 76 | 793 | SPRINKEL | +TQ=332.001 | 65 | 792.788 | ORIGINAL
Stålrør normaltykke | Nivå F | 0 | 0 | 33.8 | 33.8 | 416.2 | SPRINKEL | +TQ=332.001 | 25 | 416.177 | ORIGINAL
Stålrør normaltykke | Nivå F | 0 | 0 | 76 | 76 | 2932.4 | SPRINKEL | +TQ=332.001 | 65 | 2932.4 | ORIGINAL
Stålrør normaltykke | Nivå F | 0 | 0 | 76 | 76 | 820.3 | SPRINKEL | +TQ=332.001 | 65 | 820.3 | ORIGINAL
Stålrør normaltykke | Nivå F | 0 | 0 | 33.8 | 33.8 | 297.1 | SPRINKEL | +TS=332.007 - 1 (1) | 25 | 296.948 | ORIGINAL
Stålrør normaltykke | Nivå F | 0 | 0 | 33.8 | 33.8 | 934.7 | SPRINKEL | +TS=332.007 - 1 (1) | 25 | 934.837 | ORIGINAL
7 x Stålrør normaltykke | Nivå F | 0 | 0 | 33.8 | 33.8 | 512.4 | 33 Brannslokking våt | 33= Våt Kopi 1 | 25 | 511.948 | ORIGINAL
2 x Stålrør normaltykke | Nivå F | 0 | 0 | 33.8 | 33.8 | 507.4 | SPRINKEL | +TQ=332.001 | 25 | 506.948 | ORIGINAL
Stålrør normaltykke | Nivå F | 0 | 0 | 33.8 | 33.8 | 252.4 | SPRINKEL | +TS=332.007 - 1 (1) | 25 | 252.4 | ORIGINAL
Stålrør normaltykke | Nivå F | 0 | 0 | 33.8 | 33.8 | 260.8 | SPRINKEL | +TS=332.007 - 1 (1) | 25 | 261.071 | ORIGINAL
Stålrør normaltykke | Nivå F | 0 | 0 | 33.8 | 33.8 | 926.3 | SPRINKEL | +TS=332.007 - 1 (1) | 25 | 925.708 | ORIGINAL
Stålrør normaltykke | Nivå F | 0 | 0 | 33.8 | 33.8 | 428.5 | SPRINKEL | +TQ=332.001 | 25 | 428.231 | ORIGINAL
Stålrør normaltykke | Nivå F | 0 | 0 | 42.4 | 42.4 | 556.2 | SPRINKEL | +TQ=332.001 | 32 | 556.202 | ORIGINAL
Stålrør normaltykke | Nivå F | 0 | 0 | 33.8 | 33.8 | 422.7 | SPRINKEL | +TQ=332.001 | 25 | 422.981 | ORIGINAL
Stålrør normaltykke | Nivå F | 0 | 0 | 42.4 | 42.4 | 555.1 | SPRINKEL | +TQ=332.001 | 32 | 555.13 | ORIGINAL
Stålrør normaltykke | Nivå F | 0 | 0 | 33.8 | 33.8 | 406.9 | SPRINKEL | +TQ=332.001 | 25 | 407.1 | ORIGINAL
Stålrør normaltykke | Nivå F | 0 | 0 | 33.8 | 33.8 | 587.2 | SPRINKEL | +TQ=332.001 | 25 | 586.948 | ORIGINAL
Stålrør normaltykke | Nivå F | 0 | 0 | 76 | 76 | 406.8 | SPRINKEL | +TQ=332.001 | 65 | 406.803 | ORIGINAL
Stålrør normaltykke | Nivå F | 0 | 0 | 33.8 | 33.8 | 134 | SPRINKEL | +TS=332.007 - 1 (1) | 25 | 133.95 | ORIGINAL
3 x Stålrør normaltykke | Nivå F | 0 | 0 | 33.8 | 33.8 | 507.4 | SPRINKEL | +TQ=332.001 | 25 | 506.848 | ORIGINAL
Stålrør normaltykke | Nivå F | 0 | 0 | 33.8 | 33.8 | 267.3 | SPRINKEL | +TQ=332.001 | 25 | 266.848 | ORIGINAL
2 x Stålrør normaltykke | Nivå F | 0 | 0 | 33.8 | 33.8 | 137.4 | SPRINKEL | +TS=332.007 - 1 (1) | 25 | 136.998 | ORIGINAL
Stålrør normaltykke | Nivå F | 0 | 0 | 42.4 | 42.4 | 1829.1 | 33 Brannslokking våt | 33= Våt Kopi 1 | 32 | 1829.08 | ORIGINAL
Stålrør normaltykke | Nivå F | 0 | 0 | 60.2 | 60.2 | 347.8 | 33 Brannslokking våt | 33= Våt Kopi 1 | 50 | 347.829 | ORIGINAL
Stålrør normaltykke | Nivå F | 0 | 0 | 33.8 | 33.8 | 332.4 | 33 Brannslokking våt | 33= Våt Kopi 1 | 25 | 332.4 | ORIGINAL
Stålrør normaltykke | Nivå F | 0 | 0 | 33.8 | 33.8 | 1157.6 | 33 Brannslokking våt | 33= Våt Kopi 1 | 25 | 1158.06 | ORIGINAL
Stålrør normaltykke | Nivå F | 0 | 0 | 60.2 | 60.2 | 811.6 | 33 Brannslokking våt | 33= Våt Kopi 1 | 50 | 812.027 | ORIGINAL
5 x Stålrør normaltykke | Nivå F | 0 | 0 | 33.8 | 33.8 | 507.4 | 33 Brannslokking våt | 33= Våt Kopi 1 | 25 | 506.948 | ORIGINAL
Stålrør normaltykke | Nivå F | 0 | 0 | 33.8 | 33.8 | 427.4 | 33 Brannslokking våt | 33= Våt Kopi 1 | 25 | 426.759 | ORIGINAL
Stålrør normaltykke | Nivå F | 0 | 0 | 33.8 | 33.8 | 2930.7 | 33 Brannslokking våt | 33= Våt Kopi 1 | 25 | 2931.37 | ORIGINAL
Stålrør normaltykke | Nivå F | 0 | 0 | 60.2 | 60.2 | 828.5 | 33 Brannslokking våt | 33= Våt Kopi 1 | 50 | 828.517 | ORIGINAL
Stålrør normaltykke | Nivå F | 0 | 0 | 33.8 | 33.8 | 3486.2 | 33 Brannslokking våt | 33= Våt Kopi 1 | 25 | 3486.22 | ORIGINAL
Stålrør normaltykke | Nivå F | 0 | 0 | 33.8 | 33.8 | 435.2 | 33 Brannslokking våt | 33= Våt Kopi 1 | 25 | 435.209 | ORIGINAL
Stålrør normaltykke | Nivå F | 0 | 0 | 42.4 | 42.4 | 235.3 | 33 Brannslokking våt | 33= Våt Kopi 1 | 32 | 234.773 | ORIGINAL
Stålrør normaltykke | Nivå F | 0 | 0 | 33.8 | 33.8 | 1686.1 | 33 Brannslokking våt | 33= Våt Kopi 1 | 25 | 1686.42 | ORIGINAL
2 x Stålrør normaltykke | Nivå F | 0 | 0 | 33.8 | 33.8 | 1686.1 | 33 Brannslokking våt | 33= Våt Kopi 1 | 25 | 1686.16 | ORIGINAL
Stålrør normaltykke | Nivå F | 0 | 0 | 60.2 | 60.2 | 1346.6 | 33 Brannslokking våt | 33= Våt Kopi 1 | 50 | 1346.6 | ORIGINAL
Stålrør normaltykke | Nivå F | 0 | 0 | 33.8 | 33.8 | 413.5 | SPRINKEL | +TQ=332.001 | 25 | 413.997 | ORIGINAL
Stålrør normaltykke | Nivå F | 0 | 0 | 76 | 76 | 1672.9 | 33 Brannslokking våt | 33= Våt Kopi 1 | 65 | 1672.92 | ORIGINAL
Stålrør normaltykke | Nivå F | 0 | 0 | 48.2 | 48.2 | 134.4 | SPRINKEL | +TQ=332.001 | 40 | 134.45 | ORIGINAL
Stålrør normaltykke | Nivå F | 0 | 0 | 76 | 76 | 2646.6 | SPRINKEL | +TQ=332.001 | 65 | 2647.27 | ORIGINAL
Stålrør normaltykke | Nivå F | 0 | 0 | 76 | 76 | 1838.4 | SPRINKEL | +TQ=332.001 | 65 | 1838.35 | ORIGINAL
Stålrør normaltykke | Nivå F | 0 | 0 | 76 | 76 | 324.7 | SPRINKEL | +TQ=332.001 | 65 | 324.787 | ORIGINAL
Stålrør normaltykke | Nivå F | 0 | 0 | 33.8 | 33.8 | 146.2 | SPRINKEL | +TQ=332.001 | 25 | 146.457 | ORIGINAL
Stålrør normaltykke | Nivå F | 0 | 0 | 76 | 76 | 1843.3 | SPRINKEL | +TQ=332.001 | 65 | 1843.34 | ORIGINAL
Stålrør normaltykke | Nivå F | 0 | 0 | 33.8 | 33.8 | 146.2 | SPRINKEL | +TQ=332.001 | 25 | 146.499 | ORIGINAL
Stålrør normaltykke | Nivå F | 0 | 0 | 76 | 76 | 1956 | SPRINKEL | +TQ=332.001 | 65 | 1955.97 | ORIGINAL
Stålrør normaltykke | Nivå F | 0 | 1.882 | 33.8 | 33.8 | 385.7 | SPRINKEL | +TQ=332.001 | 25 | 385.6 | ORIGINAL
4 x Stålrør normaltykke | Nivå F | 0 | 1.882 | 33.8 | 33.8 | 656 | SPRINKEL | +TQ=332.001 | 25 | 656.507 | ORIGINAL
Stålrør normaltykke | Nivå F | 0 | 1.869 | 33.8 | 33.8 | 391.1 | SPRINKEL | +TQ=332.001 | 25 | 390.6 | ORIGINAL
4 x Stålrør normaltykke | Nivå F | 0 | 1.869 | 33.8 | 33.8 | 2207.9 | SPRINKEL | +TQ=332.001 | 25 | 2208.29 | ORIGINAL
Stålrør normaltykke | Nivå F | 0 | 3.385 | 33.8 | 33.8 | 396.9 | SPRINKEL | +TQ=332.001 | 25 | 396.669 | ORIGINAL
Stålrør normaltykke | Nivå F | 0 | 3.385 | 33.8 | 33.8 | 545.9 | SPRINKEL | +TQ=332.001 | 25 | 546.095 | ORIGINAL
Stålrør normaltykke | Nivå F | 0 | 0 | 60.2 | 60.2 | 20 | 33 Brannslokking våt | 33= Våt Kopi 1 | 50 | 19.675 | ORIGINAL
Stålrør normaltykke | Nivå F | 0 | 0 | 60.2 | 60.2 | 1020.5 | 33 Brannslokking våt | 33= Våt Kopi 1 | 50 | 1019.6 | ORIGINAL
Stålrør normaltykke | Nivå F | 0 | 0 | 60.2 | 60.2 | 25.4 | 33 Brannslokking våt | 33= Våt Kopi 1 | 50 | 24.675 | ORIGINAL
Stålrør normaltykke | Nivå F | 0 | 0 | 60.2 | 60.2 | 102.4 | 33 Brannslokking våt | 33= Våt Kopi 1 | 50 | 101.618 | ORIGINAL
Stålrør normaltykke | Nivå F | 0 | 1.882 | 33.8 | 33.8 | 416.2 | SPRINKEL | +TQ=332.001 | 25 | 416.08 | ORIGINAL
Stålrør normaltykke | Nivå F | 0 | 1.869 | 33.8 | 33.8 | 420.8 | SPRINKEL | +TQ=332.001 | 25 | 421.08 | ORIGINAL
Stålrør normaltykke | Nivå F | 0 | 1.882 | 33.8 | 33.8 | 203.8 | SPRINKEL | +TQ=332.001 | 25 | 204.462 | ORIGINAL
Stålrør normaltykke | Nivå F | 0 | 1.869 | 33.8 | 33.8 | 209.5 | SPRINKEL | +TQ=332.001 | 25 | 209.462 | ORIGINAL
Stålrør normaltykke | Nivå F | 0 | 1.882 | 33.8 | 33.8 | 211.1 | SPRINKEL | +TQ=332.001 | 25 | 210.865 | ORIGINAL
Stålrør normaltykke | Nivå F | 0 | 1.869 | 33.8 | 33.8 | 215.8 | SPRINKEL | +TQ=332.001 | 25 | 215.865 | ORIGINAL
Stålrør normaltykke | Nivå F | 0 | 0 | 33.8 | 33.8 | 322.3 | SPRINKEL | +TQ=332.001 | 25 | 321.851 | ORIGINAL
Stålrør normaltykke | Nivå F | 0 | 0 | 33.8 | 33.8 | 363.5 | SPRINKEL | +TQ=332.001 | 25 | 364.181 | ORIGINAL
Stålrør normaltykke | Nivå F | 0 | 0 | 33.8 | 33.8 | 166.5 | SPRINKEL | +TQ=332.001 | 25 | 166.064 | ORIGINAL
Stålrør normaltykke | Nivå F | 0 | 0 | 33.8 | 33.8 | 178.6 | SPRINKEL | +TQ=332.001 | 25 | 178.917 | ORIGINAL
Stålrør normaltykke | Nivå F | 0 | 0 | 76 | 76 | 80.4 | SPRINKEL | +TQ=332.001 | 65 | 80 | ORIGINAL
Stålrør normaltykke | Nivå F | 0 | 0 | 76 | 76 | 22.2 | SPRINKEL | +TQ=332.001 | 65 | 22.151 | ORIGINAL
Stålrør normaltykke | Nivå F | 0 | 0 | 76 | 76 | 74 | SPRINKEL | +TQ=332.001 | 65 | 73.467 | ORIGINAL
Stålrør normaltykke | Nivå F | 0 | 0 | 76 | 76 | 203.3 | SPRINKEL | +TQ=332.001 | 65 | 203.252 | ORIGINAL
Stålrør normaltykke | Nivå F | 0 | 0 | 76 | 76 | 150.2 | SPRINKEL | +TQ=332.001 | 65 | 150.338 | ORIGINAL
Stålrør normaltykke | Nivå F | 0 | 0 | 76 | 76 | 940.9 | SPRINKEL | +TQ=332.001 | 65 | 940.624 | ORIGINAL
Stålrør normaltykke | Nivå F | 0 | 0 | 76 | 76 | 807.3 | SPRINKEL | +TQ=332.001 | 65 | 807.323 | ORIGINAL
10 x Stålrør normaltykke | Nivå F | 0 | 0 | 33.8 | 33.8 | 498.9 | SPRINKEL | +TQ=332.001 | 25 | 499.118 | ORIGINAL
5 x Stålrør normaltykke | Nivå F | 0 | 0 | 33.8 | 33.8 | 948.3 | SPRINKEL | +TQ=332.001 | 25 | 948.474 | ORIGINAL
5 x Stålrør normaltykke | Nivå F | 0 | 0 | 33.8 | 33.8 | 1915.8 | SPRINKEL | +TQ=332.001 | 25 | 1916.33 | ORIGINAL
Stålrør normaltykke | Nivå F | 0 | 0 | 33.8 | 33.8 | 152.1 | SPRINKEL | +TQ=332.001 | 25 | 152.183 | ORIGINAL
Stålrør normaltykke | Nivå F | 0 | 0 | 33.8 | 33.8 | 159 | SPRINKEL | +TQ=332.001 | 25 | 158.633 | ORIGINAL
Stålrør normaltykke | Nivå F | 0 | 0 | 33.8 | 33.8 | 138.8 | SPRINKEL | +TQ=332.001 | 25 | 138.683 | ORIGINAL
Stålrør normaltykke | Nivå F | 0 | 0 | 33.8 | 33.8 | 127.4 | SPRINKEL | +TQ=332.001 | 25 | 126.833 | ORIGINAL
Stålrør normaltykke | Nivå F | 0 | 0 | 33.8 | 33.8 | 66.1 | 33 Brannslokking våt | 33= Våt Kopi 1 | 25 | 66.375 | ORIGINAL
Stålrør normaltykke | Nivå F | 0 | 0 | 60.2 | 60.2 | 492.1 | 33 Brannslokking våt | 33= Våt Kopi 1 | 50 | 492 | ORIGINAL
Stålrør normaltykke | Nivå F | 0 | 0 | 33.8 | 33.8 | 150.5 | SPRINKEL | +TQ=332.001 | 25 | 150.183 | ORIGINAL
Stålrør normaltykke | Nivå F | 0 | 0 | 60.2 | 59.2 | 60.2 | 33 Brannslokking våt | 33= Våt Kopi 1 | 50 | 58.899 | ORIGINAL
Stålrør normaltykke | Nivå F | 0 | 0 | 42.4 | 42.4 | 3043.8 | 33 Brannslokking våt | 33= Våt Kopi 1 | 32 | 3043.81 | ORIGINAL
Stålrør normaltykke | Nivå F | 0 | 0 | 42.4 | 42.4 | 1983.8 | 33 Brannslokking våt | 33= Våt Kopi 1 | 32 | 1983.8 | ORIGINAL
3 x Stålrør normaltykke | Nivå F | 0 | 0 | 33.8 | 33.8 | 156.8 | 33 Brannslokking våt | 33= Våt Kopi 1 | 25 | 156.848 | ORIGINAL
Stålrør normaltykke | Nivå F | 0 | 0 | 33.8 | 33.8 | 159 | 33 Brannslokking våt | 33= Våt Kopi 1 | 25 | 158.848 | ORIGINAL
Stålrør normaltykke | Nivå F | 0 | 0 | 42.4 | 42.4 | 804.3 | 33 Brannslokking våt | 33= Våt Kopi 1 | 32 | 804.068 | ORIGINAL
Stålrør normaltykke | Nivå F | 0 | 0 | 60.2 | 60.2 | 133.6 | 33 Brannslokking våt | 33= Våt Kopi 1 | 50 | 134.52 | ORIGINAL
Stålrør normaltykke | Nivå F | 0 | 0 | 76 | 76 | 285.8 | 33 Brannslokking våt | 33= Våt Kopi 1 | 65 | 285.606 | ORIGINAL
Stålrør normaltykke | Nivå F | 0 | 0 | 48.2 | 48.2 | 72 | 33 Brannslokking våt | 33= Våt Kopi 1 | 40 | 72.5 | ORIGINAL
Stålrør normaltykke | Nivå F | 0 | 0 | 48.2 | 48.2 | 342.6 | 33 Brannslokking våt | 33= Våt Kopi 1 | 40 | 343.2 | ORIGINAL
Stålrør normaltykke | Nivå F | 0 | 0 | 48.2 | 48.2 | 298.8 | 33 Brannslokking våt | 33= Våt Kopi 1 | 40 | 298.843 | ORIGINAL
Stålrør normaltykke | Nivå F | 0 | 0 | 48.2 | 48.2 | 364.7 | 33 Brannslokking våt | 33= Våt Kopi 1 | 40 | 364.67 | ORIGINAL
Stålrør normaltykke | Nivå F | 0 | 0 | 33.8 | 33.8 | 110.7 | 33 Brannslokking våt | 33= Våt Kopi 1 | 25 | 111.191 | ORIGINAL
2 x Stålrør normaltykke | Nivå F | 0 | 0 | 33.8 | 33.8 | 267.3 | 33 Brannslokking våt | 33= Våt Kopi 1 | 25 | 266.981 | ORIGINAL
Stålrør normaltykke | Nivå F | 0 | 0 | 48.2 | 48.2 | 1976.5 | 33 Brannslokking våt | 33= Våt Kopi 1 | 40 | 1976.54 | ORIGINAL
Stålrør normaltykke | Nivå F | 0 | 0 | 33.8 | 33.8 | 288.8 | 33 Brannslokking våt | 33= Våt Kopi 1 | 25 | 289.381 | ORIGINAL
Stålrør normaltykke | Nivå F | 0 | 0 | 33.8 | 33.8 | 363.5 | 33 Brannslokking våt | 33= Våt Kopi 1 | 25 | 363.977 | ORIGINAL
Stålrør normaltykke | Nivå F | 0 | 0 | 33.8 | 33.8 | 700 | 33 Brannslokking våt | 33= Våt Kopi 1 | 25 | 700.242 | ORIGINAL
Stålrør normaltykke | Nivå F | 0 | 0 | 33.8 | 33.8 | 271.5 | 33 Brannslokking våt | 33= Våt Kopi 1 | 25 | 272.4 | ORIGINAL
Stålrør normaltykke | Nivå F | 0 | 0 | 33.8 | 33.8 | 3730.4 | 33 Brannslokking våt | 33= Våt Kopi 1 | 25 | 3729.9 | ORIGINAL
Stålrør normaltykke | Nivå F | 0 | 0 | 48.2 | 48.2 | 705.5 | 33 Brannslokking våt | 33= Våt Kopi 1 | 40 | 705.775 | ORIGINAL
Stålrør normaltykke | Nivå F | 0 | 0 | 33.8 | 33.8 | 1567.1 | 33 Brannslokking våt | 33= Våt Kopi 1 | 25 | 1567.4 | ORIGINAL
Stålrør normaltykke | Nivå F | 0 | 0 | 33.8 | 33.8 | 672.4 | 33 Brannslokking våt | 33= Våt Kopi 1 | 25 | 672.4 | ORIGINAL
Stålrør normaltykke | Nivå F | 0 | 0 | 33.8 | 33.8 | 186.3 | 33 Brannslokking våt | 33= Våt Kopi 1 | 25 | 185.53 | ORIGINAL
Stålrør normaltykke | Nivå F | 0 | 0 | 33.8 | 33.8 | 922.5 | 33 Brannslokking våt | 33= Våt Kopi 1 | 25 | 922.143 | ORIGINAL
Stålrør normaltykke | Nivå F | 0 | 0 | 33.8 | 33.8 | 93 | 33 Brannslokking våt | 33= Våt Kopi 1 | 25 | 92.813 | ORIGINAL
Stålrør normaltykke | Nivå F | 0 | 0 | 33.8 | 33.8 | 297.1 | 33 Brannslokking våt | 33= Våt Kopi 1 | 25 | 296.7 | ORIGINAL
Stålrør normaltykke | Nivå F | 0 | 0 | 33.8 | 33.8 | 1077.8 | 33 Brannslokking våt | 33= Våt Kopi 1 | 25 | 1078.09 | ORIGINAL
3 x Stålrør normaltykke | Nivå F | 0 | 0 | 33.8 | 25.8 | 33.8 | 33 Brannslokking våt | 33= Våt Kopi 1 | 25 | 26.483 | ORIGINAL
3 x Stålrør normaltykke | Nivå F | 0 | 0 | 33.8 | 17.3 | 33.8 | 33 Brannslokking våt | 33= Våt Kopi 1 | 25 | 16.981 | ORIGINAL
3 x Stålrør normaltykke | Nivå F | 0 | 0 | 21.4 | 6.9 | 21.4 | 33 Brannslokking våt | 33= Våt Kopi 1 | 15 | 6.867 | ORIGINAL
Stålrør normaltykke | Nivå F | 0 | 0 | 33.8 | 33.8 | 1079.9 | 33 Brannslokking våt | 33= Våt Kopi 1 | 25 | 1080.09 | ORIGINAL
Stålrør normaltykke | Nivå F | 0 | 0 | 33.8 | 33.8 | 189.3 | 33 Brannslokking våt | 33= Våt Kopi 1 | 25 | 189.219 | ORIGINAL
Stålrør normaltykke | Nivå F |  |  | 76 | 76 | 1642 | SPRINKEL | +TQ=332.001 |  |  | RESULT
17 x Stålrør normaltykke | Nivå E |  |  | 34 | 34 | 498 | SPRINKEL | +TS=332.007 - 1 (1) |  |  | RESULT
Stålrør normaltykke | Nivå F |  |  | 34 | 34 | 476 | SPRINKEL | +TQ=332.001 |  |  | RESULT
2 x Stålrør normaltykke | Nivå F |  |  | 42 | 42 | 406 | SPRINKEL | +TQ=332.001 |  |  | RESULT
Stålrør normaltykke | Nivå F |  |  | 42 | 42 | 405 | SPRINKEL | +TQ=332.001 |  |  | RESULT
Stålrør normaltykke | Nivå F |  |  | 34 | 34 | 1511 | SPRINKEL | +TS=332.007 - 1 (1) |  |  | RESULT
Stålrør normaltykke | Nivå F |  |  | 34 | 34 | 709 | SPRINKEL | +TS=332.007 - 1 (1) |  |  | RESULT
Stålrør normaltykke | Nivå F |  |  | 76 | 76 | 405 | SPRINKEL | +TQ=332.001 |  |  | RESULT

# IfcFlowSegment: Støvsuger (3)
In: Nivå F
Type - Description: støvsuger; PredefinedType: RIGIDSEGMENT
ePset_Simplebim - Assembly Level: Leaf
Group: +TS=652.001 2
Name | Length (Simplebim) (mm) | Height (Simplebim) (mm) = Width (Simplebim) (mm) | Splitting
Støvsuger | 7333.8 | 65 | ORIGINAL
2 x Støvsuger | 792 | 64 | RESULT

# IfcFlowTerminal (3)
In: Nivå F -0,7m
ePset_Simplebim - Assembly Level: Leaf
ePset_LocationTool - Splitting: ORIGINAL
Group: +TQ=360.010 A
Name
2 x MC_ConnectionNode_Return_Air_Rectangular
MC_ConnectionNode_Return_Air_Round

# IfcFlowTerminal: 315_Toalett_HC_montert på vegg:540 x 850, 315_Toalett_HC_montert på vegg:540 x 850:46513986
In: Nivå F
Type - Material: Porselen1
ePset_LocationTool - Splitting: ORIGINAL
Pset_QuantityTakeOff - Reference: 540 x 850; sets with these values: 2
ePset_Simplebim - Assembly Level: Leaf
AVINOR - 08_Status: S4; 07_Fase: F90; 06_Omrade: TS; 03_Ansvar: OSL; 01_Lufthavnkode: ENGM; 02_Prosjekt: AO205066

# IfcFlowTerminal: 540 x 850
In: Nivå F
MagiCAD Pset_DrainageDevices - ConnectionSize_mm: 0 mm
ePset_Simplebim - Assembly Level: Leaf
ePset_LocationTool - Splitting: ORIGINAL

# IfcFlowTerminal: 68DGR-STD-SKJULT I HIMLING (22)
In: Nivå F
Type - Description: Consealed sprinkler, STD, K=80
MagiCAD Pset_Sprinkler - Description: Consealed sprinkler, STD, K=80; Manufacturer: General; KFactor: 80; Nominal Release Temperature [°C]: 68
ePset_Simplebim - Assembly Level: Leaf
ePset_LocationTool - Splitting: ORIGINAL
Group: +TQ=332.001

# IfcFlowTerminal: 68DGR-STD-STÅENDE (20)
Type - Description: Spray, Upright installation, STD, K=80
ePset_LocationTool - Splitting: ORIGINAL
ePset_Simplebim - Assembly Level: Leaf
MagiCAD Pset_Sprinkler - Manufacturer: General; KFactor: 80; Nominal Release Temperature [°C]: 68; Description: Spray, Upright installation, STD, K=80
Name | In | Group
17 x 68DGR-STD-STÅENDE | Nivå E | +TS=332.007 - 1 (1)
3 x 68DGR-STD-STÅENDE | Nivå F | +TQ=332.001

# IfcFlowTerminal: A313 - HC Vask - 560 x 600 mm
In: Nivå F
MagiCAD Pset_DrainageDevices - ConnectionSize_mm: 0 mm
ePset_LocationTool - Splitting: ORIGINAL
ePset_Simplebim - Assembly Level: Leaf

# IfcFlowTerminal: A313 - HC Vask 3D:A313 - HC Vask - 560 x 600 mm, A313 - HC Vask 3D:A313 - HC Vask - 560 x 600 mm:46514054
In: Nivå F
Type - Material: NSW - white våtrom
Pset_QuantityTakeOff - Reference: A313 - HC Vask - 560 x 600 mm; sets with these values: 2
ePset_Simplebim - Assembly Level: Leaf
ePset_LocationTool - Splitting: ORIGINAL
AVINOR - 08_Status: S4; 07_Fase: F90; 06_Omrade: TS; 03_Ansvar: OSL; 01_Lufthavnkode: ENGM; 02_Prosjekt: AO205066

# IfcFlowTerminal: A313 - Vask - 560 x 600 mm
In: Nivå F
ePset_LocationTool - Splitting: ORIGINAL
MagiCAD Pset_DrainageDevices - ConnectionSize_mm: 0 mm
ePset_Simplebim - Assembly Level: Leaf

# IfcFlowTerminal: A313 - Vaskgruppe x1:A313 - Vaskgruppe - 800 x 600mm (2)
In: Nivå F
Type - Material: NSW - våtrom silver
ePset_LocationTool - Splitting: ORIGINAL
ePset_Simplebim - Assembly Level: Leaf
AVINOR - 07_Fase: F90; 08_Status: S2; 03_Ansvar: AV1; 02_Prosjekt: 72101; 06_Omrade: TS; 01_Lufthavnkode: ENGM
Pset_DistributionFlowElementCommon - Reference: A313 - Vaskgruppe - 800 x 600mm; sets with these values: 2
Name (A313 - Vaskgruppe x1:A313 - Vaskgruppe - 800 x 600mm:...)
40491835
40491837

# IfcFlowTerminal: A313 - WC vegghengt kompakt - 375 x 570 mm (2)
In: Nivå F
MagiCAD Pset_DrainageDevices - ConnectionSize_mm: 0 mm
ePset_Simplebim - Assembly Level: Leaf
ePset_LocationTool - Splitting: ORIGINAL

# IfcFlowTerminal: Armstøtte HWC 2 (2)
In: Nivå F
MagiCAD Pset_DrainageDevices - ConnectionSize_mm: 0 mm
ePset_LocationTool - Splitting: ORIGINAL
ePset_Simplebim - Assembly Level: Leaf

# IfcFlowTerminal: BLP-K115-141C-STD
In: Nivå F
Type - Description: Standard Response bulb thermal element, K=115
MagiCAD Pset_Sprinkler - KFactor: 115; Nominal Release Temperature [°C]: 141; Product code: BLP-K115-141C-STD; Description: Standard Response bulb thermal element, K=115; Manufacturer: Generic China
ePset_LocationTool - Splitting: ORIGINAL
ePset_Simplebim - Assembly Level: Leaf
Group: 33= Våt Kopi 1

# IfcFlowTerminal: BRTR-300-300
In: Nivå F
Type - Description: Wire mesh grilles, rectangular
ePset_LocationTool - Splitting: ORIGINAL
ePset_Simplebim - Assembly Level: Leaf
Group: +TQ=360.010 T

# IfcFlowTerminal: BRTR-400-400 (2)
In: Nivå F
Type - Description: Wire mesh grilles, rectangular
ePset_LocationTool - Splitting: ORIGINAL
ePset_Simplebim - Assembly Level: Leaf
Group: +TQ=360.010 T

# IfcFlowTerminal: BRTR-600-900
In: Nivå F
Type - Description: Wire mesh grilles, rectangular
ePset_Simplebim - Assembly Level: Leaf
ePset_LocationTool - Splitting: ORIGINAL
Group: +TQ=360.020 T

# IfcFlowTerminal: Data socket-2
In: Nivå F
Type - Description: Data uttak dobbel Vegg_TVO; PredefinedType: COMMUNICATIONSOUTLET
AVINOR - 08_Status: S4; 07_Fase: F90; 05_ID-nummer: +TQ=574.001-WD1118; 02_Prosjekt: A173790; 04_Kontrakt: A173790; 01_Lufthavnkode: ENGM
Pset_OutletTypeCommon - IsPluggableOutlet: yes
MagiCAD Pset_Device - IP_Code: IP20; System code: 574; Length [mm]: 0 mm; P2: 2; Manufacturer: General; Width [mm]: 22 mm; Height [mm]: 71 mm; P1: TVO; Product code: Data socket-2
ePset_Simplebim - Assembly Level: Leaf
ePset_LocationTool - Splitting: ORIGINAL
Pset_ElectricalDeviceCommon - IP_Code: IP20
Group: Spredenett

# IfcFlowTerminal: Datauttak dobbel Vegg - IKT (15)
In: Nivå F
Type - Description: Datauttak dobbel Vegg - IKT; PredefinedType: COMMUNICATIONSOUTLET
Pset_OutletTypeCommon - IsPluggableOutlet: yes
AVINOR - 08_Status: S4; 07_Fase: F90; 01_Lufthavnkode: ENGM
MagiCAD Pset_Device - System code: 574; User code: -WD; Length [mm]: 0 mm; Width [mm]: 0 mm; Height [mm]: 0 mm
ePset_LocationTool - Splitting: ORIGINAL
ePset_Simplebim - Assembly Level: Leaf
Name | 02_Prosjekt = 04_Kontrakt | 05_ID-nummer | Group
Datauttak dobbel Vegg - IKT | A173790 | +TQ=574.001-WD0729 | Spredenett | MagiCAD Pset_Device - O1: I KASSE
Datauttak dobbel Vegg - IKT | A173790 | +TQ=574.001-WD0727 | Spredenett | MagiCAD Pset_Device - O1: I KASSE
Datauttak dobbel Vegg - IKT | A173790 | +TQ=574.001-WD1116 | Spredenett
Datauttak dobbel Vegg - IKT | A173790 | +TQ=574.001-WD1114 | Spredenett
Datauttak dobbel Vegg - IKT | A173790 | +TQ=574.001-WD1121 | Spredenett
Datauttak dobbel Vegg - IKT | A173790 | +TQ=574.001-WD1132 | Spredenett | MagiCAD Pset_Device - O1: I KASSE
Datauttak dobbel Vegg - IKT | A173790 | +TQ=574.001-WD1129 | Spredenett | MagiCAD Pset_Device - O1: I KASSE
Datauttak dobbel Vegg - IKT | A173790 | +TQ=574.001-WD1123 | Spredenett
Datauttak dobbel Vegg - IKT | A173790 | +TQ=574.001-WD1125 | Spredenett
Datauttak dobbel Vegg - IKT | A173790 | +TQ=574.001-WD1127 | Spredenett
Datauttak dobbel Vegg - IKT |  | +TQ=574.001-WD0060 | -
Datauttak dobbel Vegg - IKT |  | +TQ=574.001-WD0059 | -
Datauttak dobbel Vegg - IKT |  | +TQ=574.001-WD0055 | -
Datauttak dobbel Vegg - IKT |  | +TQ=574.001-WD0050 | -
Datauttak dobbel Vegg - IKT |  | +TQ=574.001-WD1123 | Spredenett

# IfcFlowTerminal: Datauttak enkelt Vegg - IKT (6)
In: Nivå F
Type - Description: Datauttak enkelt Vegg - IKT; PredefinedType: COMMUNICATIONSOUTLET
ePset_LocationTool - Splitting: ORIGINAL
Pset_OutletTypeCommon - IsPluggableOutlet: yes
MagiCAD Pset_Device - System code: 574; User code: -WD; Length [mm]: 0 mm; Width [mm]: 0 mm; Height [mm]: 0 mm
ePset_Simplebim - Assembly Level: Leaf
AVINOR - 08_Status: S4; 07_Fase: F90; 01_Lufthavnkode: ENGM
Name | 05_ID-nummer | Group
Datauttak enkelt Vegg - IKT | +TQ=574.001-WD0733 | Spredenett | MagiCAD Pset_Device - O1: I KASSE; AVINOR - 02_Prosjekt: A173790; 04_Kontrakt: A173790
Datauttak enkelt Vegg - IKT |  | Spredenett | MagiCAD Pset_Device - O1: I KASSE; AVINOR - 02_Prosjekt: A173790; 04_Kontrakt: A173790
Datauttak enkelt Vegg - IKT | +TQ=574.001-WD0057 | -
Datauttak enkelt Vegg - IKT | +TQ=574.001-WD0052 | -
Datauttak enkelt Vegg - IKT | +TQ=574.001-WD0053 | -
Datauttak enkelt Vegg - IKT | +TQ=574.001-WD0054 | -

# IfcFlowTerminal: Gulvboks UZD370x370 H=100mm (37)
In: Nivå F
Type - Description: Gulvboks 35x35x165
MagiCAD Pset_Device - System code: 410; Length [mm]: 0 mm; Width [mm]: 0 mm; Height [mm]: 0 mm; Voltage: 0; Number of Poles: 1; Active Power: 0 W; Manufacturer: General; Power Factor: 1
Pset_ElectricalDeviceCommon - NominalVoltage: 0; ElectricalDeviceNominalPower: 0 W; NumberOfPoles: 1
ePset_Simplebim - Assembly Level: Leaf
ePset_LocationTool - Splitting: ORIGINAL
Group: Bæresystem generelt

# IfcFlowTerminal: Høyttaler innfelt (20)
Type - Description: Høyttaler innfelt
MagiCAD Pset_Device - User code: -RM; Length [mm]: 0 mm; Width [mm]: 0 mm; Height [mm]: 0 mm
ePset_Simplebim - Assembly Level: Leaf
ePset_LocationTool - Splitting: ORIGINAL
Name | In | 04_Kontrakt
7 x Høyttaler innfelt | Nivå F | FDV | AVINOR - 08_Status: S4; 07_Fase: F90; 05_ID-nummer: +TQ=555.XXX-RMXXXX; 02_Prosjekt: A181143; 01_Lufthavnkode: ENGM
2 x Høyttaler innfelt | Nivå F | 188962 | AVINOR - 08_Status: S4; 07_Fase: F90; 05_ID-nummer: +TQ=555.XXX-RMXXXX; 02_Prosjekt: A173802; 01_Lufthavnkode: ENGM; 03_Ansvar: 187259
11 x Høyttaler innfelt | Nivå E | FDV

# IfcFlowTerminal: IB7323 Markeringslys ensidig 32 meter leseavstand vegg:IB7323 Zumtobel Crossign 160 AB LED NDA, IB7323 Markeringslys ensidig 32 meter leseavstand vegg:IB7323 Zumtobel Crossign 160 AB LED NDA:17504448
In: Nivå F
Type - Material: Light Source Hvit, Light Source Grønn, <Unnamed>
Type - Pset_ManufacturerTypeInformation - Manufacturer: Zumtobel
ePset_Simplebim - Assembly Level: Leaf
AVINOR - 08_Status: S4; 07_Fase: F90; 05_ID-nummer: +TO=443.001-IB7323; 02_Prosjekt: A173790; 04_Kontrakt: A173790; 06_Omrade: TS; 01_Lufthavnkode: ENGM
Pset_QuantityTakeOff - Reference: IB7323 Zumtobel Crossign 160 AB LED NDA; sets with these values: 2
ePset_LocationTool - Splitting: ORIGINAL
Group: 7

# IfcFlowTerminal: IB7334 Markeringslys ensidig 30 meter leseavstand wire:IB7334 Zumtobel Puresign/Consign 150 ASI NDA (3)
In: Nivå F
Type - Material: Light Source Hvit, Light Source Grønn, <Unnamed>
Type - Pset_ManufacturerTypeInformation - Manufacturer: Zumtobel
ePset_LocationTool - Splitting: ORIGINAL
ePset_Simplebim - Assembly Level: Leaf
AVINOR - 05_ID-nummer: +TO=443.001-IB7334; 08_Status: S4; 07_Fase: F90; 06_Omrade: TS; 01_Lufthavnkode: ENGM
Pset_DistributionFlowElementCommon - Reference: IB7334 Zumtobel Puresign/Consign 150 ASI NDA; sets with these values: 2
Name (IB7334 Markeringslys ensidig 30 meter leseavstand wire:IB7334 Zumtobel Puresign/Consign 150 ASI NDA:...) | 02_Prosjekt | 04_Kontrakt | Group | 03_Ansvar
17504449 | A173790 | A173790 | 8
24797950 | 10004394 | 188899 | 7 | 187259
24806115 | 10004394 | 188899 | 7 | 187259

# IfcFlowTerminal: IB7404 Ledelys utenpåliggende:IB7404 Zumtobel Resclite C Antipanic AD NDA WH, IB7404 Ledelys utenpåliggende:IB7404 Zumtobel Resclite C Antipanic AD NDA WH:22217789
In: Nivå F
Type - Material: <Unnamed>
Type - Pset_ManufacturerTypeInformation - Manufacturer: ZUMTOBEL
ePset_LocationTool - Splitting: ORIGINAL
Pset_DistributionFlowElementCommon - Reference: IB7404 Zumtobel Resclite C Antipanic AD NDA WH; sets with these values: 2
ePset_Simplebim - Assembly Level: Leaf
AVINOR - 08_Status: S4; 02_Prosjekt: A172140; 07_Fase: F50; 03_Ansvar: 181608; 04_Kontrakt: 184990; 05_ID-nummer: +TO=443.001-IB7404; 06_Omrade: TS; 01_Lufthavnkode: ENGM
Group: 7

# IfcFlowTerminal: IB7405 Ledelys innfelt i himling:IB7105 (2)
In: Nivå F
Type - Material: <Unnamed>
Type - Pset_ManufacturerTypeInformation - Manufacturer: Zumtobel
ePset_LocationTool - Splitting: ORIGINAL
ePset_Simplebim - Assembly Level: Leaf
AVINOR - 08_Status: S4; 07_Fase: F90; 04_Kontrakt: 188899; 02_Prosjekt: 10004394; 05_ID-nummer: +OO=443.000-IB7105; 03_Ansvar: 187259; 06_Omrade: TS; 01_Lufthavnkode: ENGM
Pset_QuantityTakeOff - Reference: IB7105; sets with these values: 2
Name (IB7405 Ledelys innfelt i himling:IB7105:...)
24785312
24789200 | Group: 7

# IfcFlowTerminal: IB7405 Ledelys innfelt i himling:IB7405 Zumtobel Resclite C Antipanic ED NDA WH (10)
In: Nivå F
Type - Material: <Unnamed>
Type - Pset_ManufacturerTypeInformation - Manufacturer: Zumtobel
Pset_QuantityTakeOff - Reference: IB7405 Zumtobel Resclite C Antipanic ED NDA WH; sets with these values: 2
ePset_LocationTool - Splitting: ORIGINAL
ePset_Simplebim - Assembly Level: Leaf
AVINOR - 08_Status: S4; 05_ID-nummer: +TO=443.001-IB7405; 06_Omrade: TS; 01_Lufthavnkode: ENGM
Name (IB7405 Ledelys innfelt i himling:IB7405 Zumtobel Resclite C Antipanic ED NDA WH:...) | 07_Fase | 02_Prosjekt | 04_Kontrakt | Group
12930314 | F90 | A173790 | A173790 | 7
12930327 | F90 | A173790 | A173790 | 8
12930333 | F90 | 10004394 | A173790
17435364 | F90 | A173790 | A173790 | 7
17435365 | F90 | A173790 | A173790 | 8
17435366 | F90 | 10004394 | A173790
17435367 | F90 | A173790 | A173790 | 7
17435373 | F90 | A173790 | A173790 | 7
17435375 | F90 | A173790 | A173790 | 8
18645512 | F50 | A172140 | 184990 | 1 | AVINOR - 03_Ansvar: 181608

# IfcFlowTerminal: IB7407 Ledelys Spot innfelt i himling:IB7407 Zumtobel Resclite C Spot ED NDA WH, IB7407 Ledelys Spot innfelt i himling:IB7407 Zumtobel Resclite C Spot ED NDA WH:14258463
In: Nivå F
Type - Material: <Unnamed>
Type - Pset_ManufacturerTypeInformation - Manufacturer: Zumtobel
Pset_QuantityTakeOff - Reference: IB7407 Zumtobel Resclite C Spot ED NDA WH; sets with these values: 2
AVINOR - 08_Status: S4; 07_Fase: F90; 05_ID-nummer: +TO=443.001-IB7407; 02_Prosjekt: A173790; 04_Kontrakt: A173790; 06_Omrade: TS; 01_Lufthavnkode: ENGM
ePset_Simplebim - Assembly Level: Leaf
ePset_LocationTool - Splitting: ORIGINAL
Group: 7

# IfcFlowTerminal: IB7421 Ledelys Spot innfelt i himling:IB7421 Zumtobel MICROS-S D105 LED 6/2.3W LED830 700MA WFL WH (3)
In: Nivå F
Type - Material: <Unnamed>
Type - Pset_ManufacturerTypeInformation - Manufacturer: Zumtobel
ePset_LocationTool - Splitting: ORIGINAL
AVINOR - 03_Ansvar: 181608; 01_Lufthavnkode: ENGM; 05_ID-nummer: +TO=443.001-IB7421
ePset_Simplebim - Assembly Level: Leaf
Pset_QuantityTakeOff - Reference: IB7421 Zumtobel MICROS-S D105 LED 6/2.3W LED830 700MA WFL WH; sets with these values: 2
Name (IB7421 Ledelys Spot innfelt i himling:IB7421 Zumtobel MICROS-S D105 LED 6/2.3W LED830 700MA WFL WH:...) | 08_Status | 02_Prosjekt | 07_Fase | 04_Kontrakt | 06_Omrade | Group
18741943 | S4 | A172140 | F50 | 184990 | TS | 2
18742834 | S4 | A172140 | F50 | 184990 | TS | 7
23095620 |  |  |  |  |  | 8

# IfcFlowTerminal: KSO-125 (5)
In: Nivå F
Type - Description: Exhaust diffusor.
ePset_LocationTool - Splitting: ORIGINAL
ePset_Simplebim - Assembly Level: Leaf
Name | Group
2 x KSO-125 | +TQ=360.020 A
3 x KSO-125 | +TQ=360.010 A

# IfcFlowTerminal: Markeringslys ensidig 30 meter leseavstand wire:IB7218 Zumtobel PURESIGN/COMSIGN 150 P MSC-WF15 ECD SRE innfelt, Markeringslys ensidig 30 meter leseavstand wire:IB7218 Zumtobel PURESIGN/COMSIGN 150 P MSC-WF15 ECD SRE innfelt:17504446
In: Nivå F
Type - Material: Light Source Hvit, Light Source Grønn, <Unnamed>
Type - Pset_ManufacturerTypeInformation - Manufacturer: Zumtobel
AVINOR - 08_Status: S4; 07_Fase: F90; 02_Prosjekt: A173790; 04_Kontrakt: A173790; 06_Omrade: TS; 01_Lufthavnkode: ENGM; 05_ID-nummer: +OO=443.000-IB7218
ePset_Simplebim - Assembly Level: Leaf
Pset_QuantityTakeOff - Reference: IB7218 Zumtobel PURESIGN/COMSIGN 150 P MSC-WF15 ECD SRE innfelt; sets with these values: 2
ePset_LocationTool - Splitting: ORIGINAL
Group: 8

# IfcFlowTerminal: NETTING-125 (3)
In: Nivå F
Type - Description: Generell kanalavslutning med netting
Classification: VE1.11203 Not defined (NS3420); Group: +TQ=360.010 T
ePset_Simplebim - Assembly Level: Leaf
ePset_LocationTool - Splitting: ORIGINAL

# IfcFlowTerminal: NS19-H-S-2-200 - 4-way (8)
In: Nivå F
Type - Description: 4-way Versio
ePset_Simplebim - Assembly Level: Leaf
ePset_LocationTool - Splitting: ORIGINAL
Group: +TQ=360.010 T

# IfcFlowTerminal: NS19-H-S-2-250 - 4-way (14)
In: Nivå F
Type - Description: 4-way Versio
ePset_Simplebim - Assembly Level: Leaf
ePset_LocationTool - Splitting: ORIGINAL
Group: +TQ=360.010 T

# IfcFlowTerminal: NSW_Armstøtte HWC1:Armstøtte HWC 1 (2)
In: Nivå F
Type - Material: Hvit
Pset_QuantityTakeOff - Reference: Armstøtte HWC 1; sets with these values: 2
ePset_Simplebim - Assembly Level: Leaf
ePset_LocationTool - Splitting: ORIGINAL
Name (NSW_Armstøtte HWC1:Armstøtte HWC 1:...)
46513987
46513988

# IfcFlowTerminal: Orion-LOV-TA-250+Luna-200-250
In: Nivå F -0,7m
Type - Description: ATD for panneld ceiling
Classification: VE1.13332 Not defined (NS3420); Group: +TQ=360.010 T
ePset_Simplebim - Assembly Level: Leaf
ePset_LocationTool - Splitting: ORIGINAL

# IfcFlowTerminal: SP-15-K80-68DGR-STD (10)
In: Nivå F
Type - Description: Spray, pendent installation, STD, K=80
MagiCAD Pset_Sprinkler - User Code: HIMLING; Product code: SP-15-K80-68DGR-STD; Description: Spray, pendent installation, STD, K=80; Manufacturer: General; KFactor: 80; Nominal Release Temperature [°C]: 68
ePset_LocationTool - Splitting: ORIGINAL
ePset_Simplebim - Assembly Level: Leaf
Group: +TQ=332.001

# IfcFlowTerminal: SP-15-K80-68DGR-STD-HIMLING (15)
In: Nivå F
Type - Description: Spray, pendent installation, STD, K=80
ePset_Simplebim - Assembly Level: Leaf
ePset_LocationTool - Splitting: ORIGINAL
MagiCAD Pset_Sprinkler - Description: Spray, pendent installation, STD, K=80; Manufacturer: General; KFactor: 80; Nominal Release Temperature [°C]: 68
Name | Group
4 x SP-15-K80-68DGR-STD-HIMLING | +TS=332.007 - 1 (1)
10 x SP-15-K80-68DGR-STD-HIMLING | +TQ=332.001
SP-15-K80-68DGR-STD-HIMLING | 33= Våt Kopi 1

# IfcFlowTerminal: SP-15-K80-68DGR-STD-STÅENDE 2 (3)
In: Nivå F
Type - Description: Spray, pendent installation, STD, K=80
Classification: RS1.3000121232 Not defined (NS3420); Group: 33= Våt Kopi 1
ePset_LocationTool - Splitting: ORIGINAL
MagiCAD Pset_Sprinkler - User Code: UZ03T; NationalCode: RS1.3000121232; Product code: SP-15-K80-68DGR-STD; Description: Spray, pendent installation, STD, K=80; Manufacturer: General; KFactor: 80; Nominal Release Temperature [°C]: 68
ePset_Simplebim - Assembly Level: Leaf

# IfcFlowTerminal: V313 - WC vegghengt kompakt:A313 - WC vegghengt kompakt - 375 x 570 mm, V313 - WC vegghengt kompakt:A313 - WC vegghengt kompakt - 375 x 570 mm:40491829
In: Nivå F
Type - Material: <Unnamed>
ePset_Simplebim - Assembly Level: Leaf
AVINOR - 07_Fase: F90; 08_Status: S2; 03_Ansvar: AV1; 02_Prosjekt: 72101; 06_Omrade: TS; 01_Lufthavnkode: ENGM
Pset_DistributionFlowElementCommon - Reference: A313 - WC vegghengt kompakt - 375 x 570 mm; sets with these values: 2
ePset_LocationTool - Splitting: ORIGINAL

# IfcFlowTreatmentDevice: LKR-315-900 (4)
In: Nivå F
Type - Description: Circular sound attenuator.; PredefinedType: ROUND
Classification: VB2.143122 Not defined (NS3420); Group: +TQ=360.010 T
ePset_Simplebim - Assembly Level: Leaf
ePset_LocationTool - Splitting: ORIGINAL

# IfcFlowTreatmentDevice: SLCU 315 900 50 (2)
In: Nivå F
Type - Description: Circular straight silencer; PredefinedType: ROUND
Classification: VB2.143122 Not defined (NS3420); Group: +TQ=360.010 T
ePset_LocationTool - Splitting: ORIGINAL
ePset_Simplebim - Assembly Level: Leaf

# IfcFurnishingElement: A271 - Håndtorrer & Avfall & Såpedisp:A271 - Avfall - 330 x 170 x 510 - - H=250, A271 - Håndtorrer & Avfall & Såpedisp:A271 - Avfall - 330 x 170 x 510 - - H=250:46514057
In: Nivå F
Type - Material: NSW - våtrom silver
ePset_LocationTool - Splitting: ORIGINAL
Pset_QuantityTakeOff - Reference: A271 - Avfall - 330 x 170 x 510 - - H=250
ePset_Simplebim - Assembly Level: Leaf
AVINOR - 08_Status: S4; 07_Fase: F90; 06_Omrade: TS; 03_Ansvar: OSL; 01_Lufthavnkode: ENGM; 02_Prosjekt: AO205066

# IfcMember: L Corner Mullion:A233 - Sprosse - 20 x 100 mm (11)
In: Nivå F
Type - PredefinedType: MULLION; Material: Metal - Steel
Pset_QuantityTakeOff - Reference: A233 - Sprosse - 20 x 100 mm
ePset_LocationTool - Splitting: ORIGINAL
Pset_MemberCommon - Reference: A233 - Sprosse - 20 x 100 mm; IsExternal: no
ePset_Simplebim - Assembly Level: Leaf
AVINOR - 07_Fase: F90; 03_Ansvar: FDV; 06_Omrade: TS; 01_Lufthavnkode: ENGM
Name (L Corner Mullion:A233 - Sprosse - 20 x 100 mm:...) | Span (mm) = Height (Simplebim) (mm) | Volume, net (Simplebim) (m3) | Weight, as steel (Simplebim) (kg) | Area, sides, net (Simplebim) (m2) | Length (Simplebim) (mm) | Width (Simplebim) (mm) | 08_Status
30365586 | 750 | 0.003 | 23.55 | 0.338 | 110 | 110 | S2
30365587 | 150 | 0.0006 | 4.71 | 0.074 | 110 | 110 | S2
30365588 | 750 | 0.003 | 23.55 | 0.338 | 110 | 110 | S2
30365589 | 750 | 0.003 | 23.55 | 0.338 | 110 | 110 | S2
30365590 | 740 | 0.00296 | 23.236 | 0.3336 | 110 | 110 | S2
30365591 | 600 | 0.0024 | 18.84 | 0.272 | 110 | 110 | S2
30365592 | 750 | 0.003 | 23.55 | 0.338 | 110 | 110 | S2
40491784 | 740 | 0.00296 | 23.236 | 0.3336 | 150.708 | 105.091 | S1
40491785 | 150 | 0.0006 | 4.71 | 0.074 | 150.708 | 105.091 | S1
40491786 | 600 | 0.0024 | 18.84 | 0.272 | 150.708 | 105.091 | S1
40491787 | 750 | 0.003 | 23.55 | 0.338 | 150.708 | 105.091 | S1

# IfcMember: Rectangular Mullion:A233 - Fuge 10 mm (8)
In: Nivå F
Type - PredefinedType: MULLION; Material: Fuge l
ePset_SimplebimBasicQuantities - Length (Simplebim): 12 mm; Width (Simplebim): 10 mm
ePset_Simplebim - Assembly Level: Leaf
Pset_MemberCommon - IsExternal: no; Reference: A233 - Fuge 10 mm
ePset_LocationTool - Splitting: ORIGINAL
Pset_QuantityTakeOff - Reference: A233 - Fuge 10 mm
Name (Rectangular Mullion:A233 - Fuge 10 mm:...) | Weight, as steel (Simplebim) (kg) | Height (Simplebim) (mm) = Span (mm) | Area, sides, net (Simplebim) (m2) | Volume, net (Simplebim) (m3) | 08_Status | 07_Fase | 03_Ansvar | 02_Prosjekt | 06_Omrade | 01_Lufthavnkode
47507146 | 2.3079 | 2450 | 0.10804 | 0.000294 | S4 | F90 | 182412 | A173790 | TS | ENGM
47507150 | 2.33145 | 2475 | 0.10914 | 0.000297 | S4 | F90 | 182412 | A173790 | TS | ENGM
47507165 | 0.01884 | 20 | 0.00112 | 0.0000024
47507293 | 2.2608 | 2400 | 0.10584 | 0.000288 | S4 | F90 | 182412 | A173790 | TS | ENGM
47507294 | 2.2608 | 2400 | 0.10584 | 0.000288 | S4 | F90 | 182412 | A173790 | TS | ENGM
47507158 | 2.2608 | 2400 | 0.10584 | 0.000288 | S4 | F90 | 182412 | A173790 | TS | ENGM
47507286 | 2.2608 | 2400 | 0.10584 | 0.000288 | S4 | F90 | 182412 | A173790 | TS | ENGM
47507287 | 2.2608 | 2400 | 0.10584 | 0.000288 | S4 | F90 | 182412 | A173790 | TS | ENGM

# IfcMember: Rectangular Mullion:A233 - Sprosse - 00(post)+25(fuge inkl glass) x 30 mm (5)
In: Nivå F
Type - PredefinedType: MULLION; Material: T2 - Rubber
Pset_MemberCommon - Reference: A233 - Sprosse - 00(post)+25(fuge inkl glass) x 30 mm; IsExternal: no
Pset_QuantityTakeOff - Reference: A233 - Sprosse - 00(post)+25(fuge inkl glass) x 30 mm
ePset_SimplebimBasicQuantities - Height (Simplebim): 30 mm; Width (Simplebim): 25 mm
ePset_Simplebim - Assembly Level: Leaf
ePset_LocationTool - Splitting: ORIGINAL
Name (Rectangular Mullion:A233 - Sprosse - 00(post)+25(fuge inkl glass) x 30 mm:...) | Span (mm) = Length (Simplebim) (mm) | Area, sides, net (Simplebim) (m2) | Weight, as steel (Simplebim) (kg) | Volume, net (Simplebim) (m3)
47507288 | 25 | 0.00425 | 0.147188 | 0.00001875
47507289 | 1286.67 | 0.143033 | 7.57525 | 0.000965 | AVINOR - 08_Status: S4; 07_Fase: F90; 03_Ansvar: 182412; 02_Prosjekt: A173790; 06_Omrade: TS; 01_Lufthavnkode: ENGM
47507290 | 1286.67 | 0.143033 | 7.57525 | 0.000965
47507291 | 1286.67 | 0.143033 | 7.57525 | 0.000965
47507292 | 25 | 0.00425 | 0.147188 | 0.00001875

# IfcMember: Rectangular Mullion:A233 - Sprosse 50 mm - 060(post)+40(dekkprofil) (20)
In: Nivå F
Type - PredefinedType: MULLION; Material: T2_Metal_Aluminium
Pset_QuantityTakeOff - Reference: A233 - Sprosse 50 mm - 060(post)+40(dekkprofil)
ePset_Simplebim - Assembly Level: Leaf
Pset_MemberCommon - Reference: A233 - Sprosse 50 mm - 060(post)+40(dekkprofil); IsExternal: no
ePset_LocationTool - Splitting: ORIGINAL
Name (Rectangular Mullion:A233 - Sprosse 50 mm - 060(post)+40(dekkprofil):...) | Span (mm) | 03_Ansvar | Length (Simplebim) (mm) | Width (Simplebim) (mm) | Volume, net (Simplebim) (m3) | Area, sides, net (Simplebim) (m2) | Weight, as steel (Simplebim) (kg) | Height (Simplebim) (mm)
30360354 | 1224.01 | FDV | 1224.01 | 100 | 0.00612006 | 0.377204 | 48.0425 | 50 | AVINOR - 07_Fase: F90; 08_Status: S2; 06_Omrade: TS; 01_Lufthavnkode: ENGM
30360355 | 1224.01 | FDV | 1224.01 | 100 | 0.00612006 | 0.377204 | 48.0425 | 50 | AVINOR - 07_Fase: F90; 08_Status: S2; 06_Omrade: TS; 01_Lufthavnkode: ENGM
30360356 | 690 | FDV | 100 | 50 | 0.00345 | 0.217 | 27.0825 | 690 | AVINOR - 07_Fase: F90; 08_Status: S2; 06_Omrade: TS; 01_Lufthavnkode: ENGM
30360357 | 600 | FDV | 100 | 50 | 0.003 | 0.19 | 23.55 | 600 | AVINOR - 07_Fase: F90; 08_Status: S2; 06_Omrade: TS; 01_Lufthavnkode: ENGM
30366136 | 1500 | FDV | 100 | 50 | 0.0075 | 0.46 | 58.875 | 1500 | AVINOR - 07_Fase: F90; 08_Status: S2; 06_Omrade: TS; 01_Lufthavnkode: ENGM
30366137 | 740 | OSL | 100 | 50 | 0.0037 | 0.232 | 29.045 | 740 | AVINOR - 07_Fase: F90; 08_Status: S4; 06_Omrade: TS; 01_Lufthavnkode: ENGM; 02_Prosjekt: AO205066
30366138 | 1174.01 | FDV | 1174.01 | 100 | 0.00587006 | 0.362204 | 46.08 | 50 | AVINOR - 07_Fase: F90; 08_Status: S2; 06_Omrade: TS; 01_Lufthavnkode: ENGM
30366178 | 650 | FDV | 100 | 50 | 0.00325 | 0.205 | 25.5125 | 650 | AVINOR - 07_Fase: F90; 08_Status: S2; 06_Omrade: TS; 01_Lufthavnkode: ENGM
30366179 | 1500 | OSL | 100 | 50 | 0.0075 | 0.46 | 58.875 | 1500 | AVINOR - 07_Fase: F90; 08_Status: S4; 06_Omrade: TS; 01_Lufthavnkode: ENGM; 02_Prosjekt: AO205066
30366180 | 1174.01 | FDV | 1174.01 | 100 | 0.00587006 | 0.362204 | 46.08 | 50 | AVINOR - 07_Fase: F90; 08_Status: S2; 06_Omrade: TS; 01_Lufthavnkode: ENGM
46579951 | 1224.01 | FDV | 1224.01 | 100 | 0.00612006 | 0.377204 | 48.0425 | 50
46579952 | 1224.01 | FDV | 1224.01 | 100 | 0.00612006 | 0.377204 | 48.0425 | 50
46579953 | 690 | FDV | 100 | 50 | 0.00345 | 0.217 | 27.0825 | 690
46579954 | 600 | FDV | 100 | 50 | 0.003 | 0.19 | 23.55 | 600
46579957 | 1500 | FDV | 100 | 50 | 0.0075 | 0.46 | 58.875 | 1500
46579958 | 740 | FDV | 100 | 50 | 0.0037 | 0.232 | 29.045 | 740
46579959 | 1174.01 | FDV | 1174.01 | 100 | 0.00587006 | 0.362204 | 46.08 | 50
46579962 | 650 | FDV | 100 | 50 | 0.00325 | 0.205 | 25.5125 | 650
46579963 | 1500 | FDV | 100 | 50 | 0.0075 | 0.46 | 58.875 | 1500
46579964 | 1174.01 | FDV | 1174.01 | 100 | 0.00587006 | 0.362204 | 46.08 | 50

# IfcMember: Rectangular Mullion:A233 - Sprosse rektangulær - 50 x 100 mm (15)
In: Nivå F
Type - PredefinedType: MULLION; Material: Metal - Aluminium
Pset_QuantityTakeOff - Reference: A233 - Sprosse rektangulær - 50 x 100 mm
ePset_Simplebim - Assembly Level: Leaf
Pset_MemberCommon - Reference: A233 - Sprosse rektangulær - 50 x 100 mm; IsExternal: no
ePset_LocationTool - Splitting: ORIGINAL
Name (Rectangular Mullion:A233 - Sprosse rektangulær - 50 x 100 mm:...) | Volume, net (Simplebim) (m3) | Length (Simplebim) (mm) | Height (Simplebim) (mm) | Width (Simplebim) (mm) | Weight, as steel (Simplebim) (kg) | Area, sides, net (Simplebim) (m2) | 08_Status | 07_Fase | 03_Ansvar | 02_Prosjekt | 06_Omrade | 01_Lufthavnkode | Span (mm)
47507142 | 0.00648333 | 1296.67 | 50 | 100 | 50.8942 | 0.399 | S4 | F90 | 182412 | A173790 | TS | ENGM | 1296.67
47507143 | 0.00645833 | 1291.67 | 50 | 100 | 50.6979 | 0.3975 | S4 | F90 | 182412 | A173790 | TS | ENGM | 1291.67
47507149 | 0.00645833 | 1291.67 | 50 | 100 | 50.6979 | 0.3975 |  |  |  |  |  |  | 1291.67
47507166 | 0.00645833 | 1291.67 | 50 | 100 | 50.6979 | 0.3975 | S4 | F90 | 182412 | A173790 | TS | ENGM | 1291.67
47507167 | 0.00648333 | 1296.67 | 50 | 100 | 50.8942 | 0.399 | S4 | F90 | 182412 | A173790 | TS | ENGM | 1296.67
47507168 | 0.00650833 | 1301.67 | 50 | 100 | 51.0904 | 0.4005 | S4 | F90 | 182412 | A173790 | TS | ENGM | 1301.67
47507155 | 0.00728256 | 1456.51 | 50 | 100 | 57.1681 | 0.446953 | S4 | F90 | 182412 | A173790 | TS | ENGM | 1457.5
47507273 | 0.00691125 | 1382.25 | 50 | 100 | 54.2533 | 0.424675 | S4 | F90 | 182412 | A173790 | TS | ENGM | 1382.25
47507274 | 0.0070375 | 1407.5 | 50 | 100 | 55.2444 | 0.43225 | S4 | F90 | 182412 | A173790 | TS | ENGM | 1407.5
47507275 | 0.00013875 | 100 | 50 | 27.75 | 1.08919 | 0.018325 |  |  |  |  |  |  | 27.75
47507276 | 0.0125 | 100 | 2500 | 50 | 98.125 | 0.76 | S4 | F90 | 182412 | A173790 | TS | ENGM | 2500
47507277 | 0.00013875 | 100 | 50 | 27.75 | 1.08919 | 0.018325 |  |  |  |  |  |  | 27.75
47507278 | 0.0070375 | 1407.5 | 50 | 100 | 55.2444 | 0.43225 | S4 | F90 | 182412 | A173790 | TS | ENGM | 1407.5
47507281 | 0.00691125 | 1382.25 | 50 | 100 | 54.2533 | 0.424675 | S4 | F90 | 182412 | A173790 | TS | ENGM | 1382.25
47507282 | 0.00728256 | 1456.51 | 50 | 100 | 57.1681 | 0.446953 | S4 | F90 | 182412 | A173790 | TS | ENGM | 1457.5

# IfcPlate: Spiler_40 x 20:Spiler_40 x 20 (192)
In: Nivå F
Type - PredefinedType: CURTAIN_PANEL; Material: MDF plate svart, Wood
ePset_LocationTool - Splitting: ORIGINAL
Pset_PlateCommon - Reference: Spiler_40 x 20; IsExternal: no
Pset_QuantityTakeOff - Reference: Spiler_40 x 20
ePset_Simplebim - Assembly Level: Leaf
Name (Spiler_40 x 20:Spiler_40 x 20:...) | Weight, as steel (Simplebim) (kg) | Area, largest surface, net (Simplebim) (m2) | Volume, net (Simplebim) (m3)
66815050 | 32.9323 | 0.1656 | 0.0041952
66815053 | 32.9323 | 0.1656 | 0.0041952
66815055 | 32.9323 | 0.1656 | 0.0041952
66815057 | 32.9323 | 0.1656 | 0.0041952
66815059 | 32.9323 | 0.1656 | 0.0041952
66815061 | 32.9323 | 0.1656 | 0.0041952
66815063 | 32.9323 | 0.1656 | 0.0041952
66815065 | 32.9323 | 0.1656 | 0.0041952
66815067 | 32.9323 | 0.1656 | 0.0041952
66815069 | 32.9323 | 0.1656 | 0.0041952
66815071 | 32.9323 | 0.1656 | 0.0041952
66818346 | 32.9323 | 0.1656 | 0.0041952
66818348 | 32.9323 | 0.1656 | 0.0041952
66818666 | 32.9323 | 0.1656 | 0.0041952
66815983 | 3.10232 | 0.0156 | 0.0003952
66815985 | 3.10232 | 0.0156 | 0.0003952
66815987 | 3.10232 | 0.0156 | 0.0003952
66815989 | 3.10232 | 0.0156 | 0.0003952
66815991 | 3.10232 | 0.0156 | 0.0003952
66815993 | 3.10232 | 0.0156 | 0.0003952
66815995 | 3.10232 | 0.0156 | 0.0003952
66815997 | 3.10232 | 0.0156 | 0.0003952
66815999 | 3.10232 | 0.0156 | 0.0003952
66816001 | 3.10232 | 0.0156 | 0.0003952
66816003 | 3.10232 | 0.0156 | 0.0003952
66816005 | 3.10232 | 0.0156 | 0.0003952
66816007 | 3.10232 | 0.0156 | 0.0003952
66816009 | 3.10232 | 0.0156 | 0.0003952
66816011 | 3.10232 | 0.0156 | 0.0003952
66816013 | 3.10232 | 0.0156 | 0.0003952
66816015 | 3.10232 | 0.0156 | 0.0003952
66816017 | 3.10232 | 0.0156 | 0.0003952
66816019 | 3.10232 | 0.0156 | 0.0003952
66816021 | 3.10232 | 0.0156 | 0.0003952
66816099 | 3.10232 | 0.0156 | 0.0003952
66816101 | 3.10232 | 0.0156 | 0.0003952
66816103 | 3.10232 | 0.0156 | 0.0003952
66816105 | 3.10232 | 0.0156 | 0.0003952
66816107 | 3.10232 | 0.0156 | 0.0003952
66816109 | 3.10232 | 0.0156 | 0.0003952
66816111 | 3.10232 | 0.0156 | 0.0003952
66816113 | 3.10232 | 0.0156 | 0.0003952
66816115 | 3.10232 | 0.0156 | 0.0003952
66816117 | 3.10232 | 0.0156 | 0.0003952
66816119 | 3.10232 | 0.0156 | 0.0003952
66816121 | 3.10232 | 0.0156 | 0.0003952
66816370 | 3.10232 | 0.0156 | 0.0003952
66816372 | 3.10232 | 0.0156 | 0.0003952
66816374 | 3.10232 | 0.0156 | 0.0003952
66816376 | 3.10232 | 0.0156 | 0.0003952
66816378 | 3.10232 | 0.0156 | 0.0003952
66816380 | 3.10232 | 0.0156 | 0.0003952
66818354 | 3.10232 | 0.0156 | 0.0003952
66818356 | 3.10232 | 0.0156 | 0.0003952
66818358 | 3.10232 | 0.0156 | 0.0003952
66818360 | 3.10232 | 0.0156 | 0.0003952
66818362 | 3.10232 | 0.0156 | 0.0003952
66818364 | 3.10232 | 0.0156 | 0.0003952
66818670 | 3.10232 | 0.0156 | 0.0003952
66818672 | 3.10232 | 0.0156 | 0.0003952
66818674 | 3.10232 | 0.0156 | 0.0003952
66818676 | 3.10232 | 0.0156 | 0.0003952
66818678 | 3.10232 | 0.0156 | 0.0003952
66818680 | 3.10232 | 0.0156 | 0.0003952
66823053 | 3.10232 | 0.0156 | 0.0003952
66823055 | 3.10232 | 0.0156 | 0.0003952
66821903 | 32.9323 | 0.1656 | 0.0041952
66823650 | 32.9323 | 0.1656 | 0.0041952
66821917 | 32.9323 | 0.1656 | 0.0041952
66821919 | 32.9323 | 0.1656 | 0.0041952
66821921 | 32.9323 | 0.1656 | 0.0041952
66821923 | 32.9323 | 0.1656 | 0.0041952
66821925 | 32.9323 | 0.1656 | 0.0041952
66821927 | 32.9323 | 0.1656 | 0.0041952
66821929 | 32.9323 | 0.1656 | 0.0041952
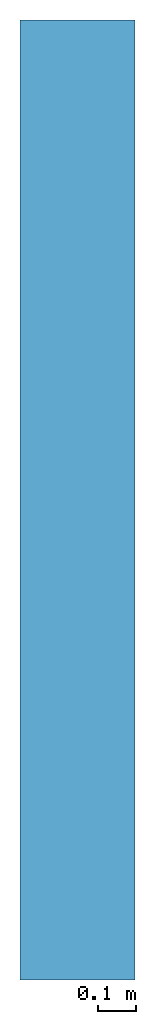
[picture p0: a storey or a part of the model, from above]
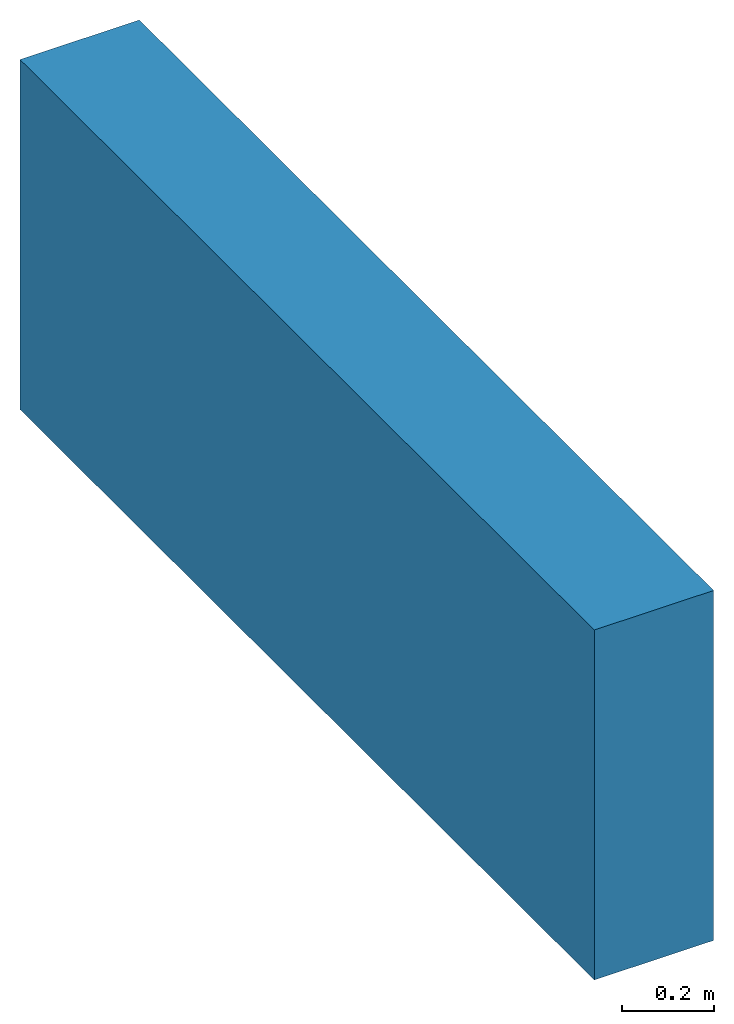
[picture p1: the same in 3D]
Properties of the parts of a building model (IFC2X3), part 3 of 4

# IfcPlate: Spiler_40 x 20:Spiler_40 x 20 (192)
Name (Spiler_40 x 20:Spiler_40 x 20:...) | Weight, as steel (Simplebim) (kg) | Area, largest surface, net (Simplebim) (m2) | Volume, net (Simplebim) (m3)
66823306 | 32.9323 | 0.1656 | 0.0041952
66824037 | 32.9323 | 0.1656 | 0.0041952
66824059 | 32.9323 | 0.1656 | 0.0041952
66824057 | 32.9323 | 0.1656 | 0.0041952
66824055 | 32.9323 | 0.1656 | 0.0041952
66824039 | 32.9323 | 0.1656 | 0.0041952
66824041 | 32.9323 | 0.1656 | 0.0041952
66824043 | 32.9323 | 0.1656 | 0.0041952
66824045 | 32.9323 | 0.1656 | 0.0041952
66824047 | 32.9323 | 0.1656 | 0.0041952
66824049 | 32.9323 | 0.1656 | 0.0041952
66824051 | 32.9323 | 0.1656 | 0.0041952
66835722 | 3.10232 | 0.0156 | 0.0003952
66835724 | 3.10232 | 0.0156 | 0.0003952
66835726 | 3.10232 | 0.0156 | 0.0003952
66835728 | 3.10232 | 0.0156 | 0.0003952
66835730 | 3.10232 | 0.0156 | 0.0003952
66835732 | 3.10232 | 0.0156 | 0.0003952
66835734 | 3.10232 | 0.0156 | 0.0003952
66835736 | 3.10232 | 0.0156 | 0.0003952
66835738 | 3.10232 | 0.0156 | 0.0003952
66835740 | 3.10232 | 0.0156 | 0.0003952
66835742 | 3.10232 | 0.0156 | 0.0003952
66835744 | 3.10232 | 0.0156 | 0.0003952
66835746 | 3.10232 | 0.0156 | 0.0003952
66835748 | 3.10232 | 0.0156 | 0.0003952
66835750 | 3.10232 | 0.0156 | 0.0003952
66835752 | 3.10232 | 0.0156 | 0.0003952
66835754 | 3.10232 | 0.0156 | 0.0003952
66835756 | 3.10232 | 0.0156 | 0.0003952
66835758 | 3.10232 | 0.0156 | 0.0003952
66835760 | 3.10232 | 0.0156 | 0.0003952
66835762 | 3.10232 | 0.0156 | 0.0003952
66835764 | 3.10232 | 0.0156 | 0.0003952
66835766 | 3.10232 | 0.0156 | 0.0003952
66835768 | 3.10232 | 0.0156 | 0.0003952
66835770 | 3.10232 | 0.0156 | 0.0003952
66865761 | 3.10232 | 0.0156 | 0.0003952
66865765 | 3.10232 | 0.0156 | 0.0003952
66838885 | 32.9323 | 0.1656 | 0.0041952
66839041 | 32.9323 | 0.1656 | 0.0041952
66839039 | 32.9323 | 0.1656 | 0.0041952
66839037 | 32.9323 | 0.1656 | 0.0041952
66838887 | 32.9323 | 0.1656 | 0.0041952
66838889 | 32.9323 | 0.1656 | 0.0041952
66838891 | 32.9323 | 0.1656 | 0.0041952
66838893 | 32.9323 | 0.1656 | 0.0041952
66838895 | 32.9323 | 0.1656 | 0.0041952
66838897 | 32.9323 | 0.1656 | 0.0041952
66838899 | 32.9323 | 0.1656 | 0.0041952
66839108 | 32.9323 | 0.1656 | 0.0041952
66839130 | 32.9323 | 0.1656 | 0.0041952
66839128 | 32.9323 | 0.1656 | 0.0041952
66839126 | 32.9323 | 0.1656 | 0.0041952
66839110 | 32.9323 | 0.1656 | 0.0041952
66839112 | 32.9323 | 0.1656 | 0.0041952
66839114 | 32.9323 | 0.1656 | 0.0041952
66839116 | 32.9323 | 0.1656 | 0.0041952
66839118 | 32.9323 | 0.1656 | 0.0041952
66839120 | 32.9323 | 0.1656 | 0.0041952
66839122 | 32.9323 | 0.1656 | 0.0041952
66864435 | 32.9323 | 0.1656 | 0.0041952
66984062 | 32.9323 | 0.1656 | 0.0041952
66984060 | 32.9323 | 0.1656 | 0.0041952
66984058 | 32.9323 | 0.1656 | 0.0041952
66864437 | 32.9323 | 0.1656 | 0.0041952
66864439 | 32.9323 | 0.1656 | 0.0041952
66864441 | 32.9323 | 0.1656 | 0.0041952
66864443 | 32.9323 | 0.1656 | 0.0041952
66864445 | 32.9323 | 0.1656 | 0.0041952
66864447 | 32.9323 | 0.1656 | 0.0041952
66864465 | 32.9323 | 0.1656 | 0.0041952
66864451 | 32.9323 | 0.1656 | 0.0041952
66864453 | 32.9323 | 0.1656 | 0.0041952
66864455 | 32.9323 | 0.1656 | 0.0041952
66864457 | 32.9323 | 0.1656 | 0.0041952
66864459 | 32.9323 | 0.1656 | 0.0041952
66864461 | 32.9323 | 0.1656 | 0.0041952
66864463 | 32.9323 | 0.1656 | 0.0041952
66864467 | 32.9323 | 0.1656 | 0.0041952
66866074 | 32.9323 | 0.1656 | 0.0041952
66866076 | 32.9323 | 0.1656 | 0.0041952
66866078 | 32.9323 | 0.1656 | 0.0041952
66866080 | 32.9323 | 0.1656 | 0.0041952
66866082 | 32.9323 | 0.1656 | 0.0041952
66866084 | 32.9323 | 0.1656 | 0.0041952
66866086 | 32.9323 | 0.1656 | 0.0041952
66866088 | 32.9323 | 0.1656 | 0.0041952
66866491 | 32.9323 | 0.1656 | 0.0041952
66866843 | 32.9323 | 0.1656 | 0.0041952
66866845 | 32.9323 | 0.1656 | 0.0041952
66866847 | 32.9323 | 0.1656 | 0.0041952
66866849 | 32.9323 | 0.1656 | 0.0041952
66866851 | 32.9323 | 0.1656 | 0.0041952
66866853 | 32.9323 | 0.1656 | 0.0041952
66866855 | 32.9323 | 0.1656 | 0.0041952
66866857 | 32.9323 | 0.1656 | 0.0041952
66867980 | 32.9323 | 0.1656 | 0.0041952
66867982 | 32.9323 | 0.1656 | 0.0041952
66867984 | 32.9323 | 0.1656 | 0.0041952
66867986 | 8.82968 | 0.0444 | 0.0011248
66868600 | 8.82968 | 0.0444 | 0.0011248
66868661 | 8.82968 | 0.0444 | 0.0011248
66867992 | 8.82968 | 0.0444 | 0.0011248
66867994 | 8.82968 | 0.0444 | 0.0011248
66867996 | 8.82968 | 0.0444 | 0.0011248
66867998 | 8.82968 | 0.0444 | 0.0011248
66868000 | 8.82968 | 0.0444 | 0.0011248
66868002 | 8.82968 | 0.0444 | 0.0011248
66868004 | 8.82968 | 0.0444 | 0.0011248
66868006 | 8.82968 | 0.0444 | 0.0011248
66868008 | 8.82968 | 0.0444 | 0.0011248
66868010 | 8.82968 | 0.0444 | 0.0011248
66868012 | 8.82968 | 0.0444 | 0.0011248
66868662 | 8.82968 | 0.0444 | 0.0011248
66868601 | 8.82968 | 0.0444 | 0.0011248
66872025 | 32.9323 | 0.1656 | 0.0041952

# IfcPlate: Spiler_40 x 20_enkel:Spiler_40 x 20_enkel (5)
In: Nivå F
Type - PredefinedType: CURTAIN_PANEL; Material: MDF plate svart, Wood
Pset_QuantityTakeOff - Reference: Spiler_40 x 20_enkel
Pset_PlateCommon - Reference: Spiler_40 x 20_enkel; IsExternal: no
ePset_SimplebimBasicQuantities - Weight, as steel (Simplebim): 27.7325 kg; Area, largest surface, net (Simplebim): 0.1104 m2; Volume, net (Simplebim): 0.0035328 m3
ePset_Simplebim - Assembly Level: Leaf
ePset_LocationTool - Splitting: ORIGINAL
Name (Spiler_40 x 20_enkel:Spiler_40 x 20_enkel:...)
66823303
66864449
66866488
66868112
66872023

# IfcPlate: System Panel:A240 - Metallkasett Inv.20mm - Offset 30mm (4)
In: Nivå F
Type - PredefinedType: CURTAIN_PANEL; Material: Metal - Steel
AVINOR - 07_Fase: F90; 08_Status: S1; 03_Ansvar: FDV; 06_Omrade: TS; 01_Lufthavnkode: ENGM
Pset_QuantityTakeOff - Reference: A240 - Metallkasett Inv.20mm - Offset 30mm
ePset_Simplebim - Assembly Level: Leaf
ePset_LocationTool - Splitting: RESULT
Pset_PlateCommon - IsExternal: no; Reference: A240 - Metallkasett Inv.20mm - Offset 30mm
Name (System Panel:A240 - Metallkasett Inv.20mm - Offset 30mm:...) | Weight, as steel (Simplebim) (kg) | Area, largest surface, net (Simplebim) (m2) | Volume, net (Simplebim) (m3)
40491779 | 163.328 | 1.0403 | 0.0208061
40491777 | 165.535 | 1.05436 | 0.0210872
40491775 | 132.428 | 0.84349 | 0.0168698
40491773 | 33.107 | 0.210872 | 0.00421745

# IfcPlate: System Panel:A245 - Glass - 10 mm (7)
In: Nivå F
Type - PredefinedType: CURTAIN_PANEL; Material: Glass(Avinor)
Pset_QuantityTakeOff - Reference: A245 - Glass - 10 mm
ePset_Simplebim - Assembly Level: Leaf
AVINOR - 08_Status: S4; 07_Fase: F90; 03_Ansvar: 182412; 02_Prosjekt: A173790; 06_Omrade: TS; 01_Lufthavnkode: ENGM
Pset_PlateCommon - Reference: A245 - Glass - 10 mm; IsExternal: no
ePset_LocationTool - Splitting: ORIGINAL
Name (System Panel:A245 - Glass - 10 mm:...) | Volume, net (Simplebim) (m3) | Weight, as steel (Simplebim) (kg) | Area, largest surface, net (Simplebim) (m2)
47507137 | 0.00061875 | 4.85719 | 0.061875
47507148 | 0.03088 | 242.408 | 3.088
47507141 | 0.03088 | 242.408 | 3.088
47507139 | 0.03088 | 242.408 | 3.088
47507145 | 0.00061875 | 4.85719 | 0.061875
47507280 | 0.032934 | 258.532 | 3.2934
47507157 | 0.000546 | 4.2861 | 0.0546

# IfcPlate: System Panel:A245 - Glass - 10mm (8)
In: Nivå F
Type - PredefinedType: CURTAIN_PANEL; Material: Glass(Avinor)
ePset_LocationTool - Splitting: ORIGINAL
ePset_Simplebim - Assembly Level: Leaf
Pset_QuantityTakeOff - Reference: A245 - Glass - 10mm
Pset_PlateCommon - Reference: A245 - Glass - 10mm
Name (System Panel:A245 - Glass - 10mm:...) | 07_Fase | 03_Ansvar | 08_Status | 06_Omrade | 01_Lufthavnkode | Area, largest surface, net (Simplebim) (m2) | Volume, net (Simplebim) (m3) | Weight, as steel (Simplebim) (kg) | IsExternal
30360350 | F90 | FDV | S2 | TS | ENGM | 0.780718 | 0.00780718 | 61.2864 | no
30366129 | F90 | FDV | S2 | TS | ENGM | 1.70232 | 0.0170232 | 133.632 | no
30366171 | F90 | FDV | S2 | TS | ENGM | 0.675057 | 0.00675057 | 52.992 | no
46579950 |  | FDV |  |  |  | 0.780718 | 0.00780718 | 61.2864 | no
46579956 |  | FDV |  |  |  | 1.70232 | 0.0170232 | 133.632 | no
46579961 |  | FDV |  |  |  | 0.675057 | 0.00675057 | 52.992 | no
47507296 | F90 | 182412 | S4 | TS | ENGM | 3.366 | 0.03366 | 264.231 | yes | AVINOR - 02_Prosjekt: A173790
47507295 | F90 | 182412 | S4 | TS | ENGM | 3.474 | 0.03474 | 272.709 | yes | AVINOR - 02_Prosjekt: A173790

# IfcPlate: System Panel:A245 - Glass - 20 mm (2)
In: Nivå F
Type - PredefinedType: CURTAIN_PANEL; Material: Glass(Avinor)
Pset_PlateCommon - Reference: A245 - Glass - 20 mm; IsExternal: no
Pset_QuantityTakeOff - Reference: A245 - Glass - 20 mm
ePset_LocationTool - Splitting: ORIGINAL
ePset_Simplebim - Assembly Level: Leaf
Name (System Panel:A245 - Glass - 20 mm:...) | Volume, net (Simplebim) (m3) | Area, largest surface, net (Simplebim) (m2) | Weight, as steel (Simplebim) (kg)
46514075 | 0.0076472 | 0.38236 | 60.0305
46514078 | 0.0170192 | 0.85096 | 133.601

# IfcPlate: System Panel:A245 - KL-M00 - - - skal byttes manuelt (5)
In: Nivå F
Type - PredefinedType: CURTAIN_PANEL; Material: Metal - Preget plate
ePset_LocationTool - Splitting: ORIGINAL
Pset_PlateCommon - Reference: A245 - KL-M00 - - - skal byttes manuelt; IsExternal: no
ePset_Simplebim - Assembly Level: Leaf
Pset_QuantityTakeOff - Reference: A245 - KL-M00 - - - skal byttes manuelt
Name (System Panel:A245 - KL-M00 - - - skal byttes manuelt:...) | Area, largest surface, net (Simplebim) (m2) | Volume, net (Simplebim) (m3) | Weight, as steel (Simplebim) (kg)
46579931 | 4.81 | 0.0962 | 755.17
46579941 | 0.462 | 0.00924 | 72.534
46580013 | 2.17329 | 0.0434658 | 341.206
46580017 | 2.095 | 0.0419 | 328.915
46580019 | 1.9061 | 0.038122 | 299.258

# IfcPlate: System Panel:A245 - KL-M01 - Veggkledning metallplate plan (12)
In: Nivå F
Type - PredefinedType: CURTAIN_PANEL; Material: T2_Metal_Aluminium
Pset_QuantityTakeOff - Reference: A245 - KL-M01 - Veggkledning metallplate plan
ePset_Simplebim - Assembly Level: Leaf
Pset_PlateCommon - Reference: A245 - KL-M01 - Veggkledning metallplate plan; IsExternal: no
ePset_LocationTool - Splitting: ORIGINAL
Name (System Panel:A245 - KL-M01 - Veggkledning metallplate plan:...) | Volume, net (Simplebim) (m3) | Weight, as steel (Simplebim) (kg) | Area, largest surface, net (Simplebim) (m2)
46580056 | 0.0051678 | 40.5672 | 1.7226
46580113 | 0.0013125 | 10.3031 | 0.4375
46580251 | 0.0013125 | 10.3031 | 0.4375
46580255 | 0.0013125 | 10.3031 | 0.4375
46580259 | 0.0013125 | 10.3031 | 0.4375
46580261 | 0.0013125 | 10.3031 | 0.4375
46580263 | 0.0013125 | 10.3031 | 0.4375
46580317 | 0.0013125 | 10.3031 | 0.4375
46580319 | 0.0013125 | 10.3031 | 0.4375
46580323 | 0.0013125 | 10.3031 | 0.4375
46580325 | 0.0013125 | 10.3031 | 0.4375
46580329 | 0.0013125 | 10.3031 | 0.4375

# IfcPlate: System Panel:A245 - KL-S01 - Veggkledning metallplate sokkel - IGK - 10mm (4)
In: Nivå F
Type - PredefinedType: CURTAIN_PANEL; Material: _NSW Stål, rustfritt
Pset_QuantityTakeOff - Reference: A245 - KL-S01 - Veggkledning metallplate sokkel - IGK - 10mm
Pset_PlateCommon - IsExternal: no; Reference: A245 - KL-S01 - Veggkledning metallplate sokkel - IGK - 10mm
ePset_Simplebim - Assembly Level: Leaf
ePset_LocationTool - Splitting: ORIGINAL
Name (System Panel:A245 - KL-S01 - Veggkledning metallplate sokkel - IGK - 10mm:...) | Weight, as steel (Simplebim) (kg) | Area, largest surface, net (Simplebim) (m2) | Volume, net (Simplebim) (m3)
67054708 | 5.28305 | 0.0673 | 0.000673
67054710 | 0.942 | 0.012 | 0.00012
67054712 | 5.28305 | 0.0673 | 0.000673
67072279 | 28.067 | 0.357542 | 0.00357542

# IfcPlate: System Panel:A245 - Metallkasett Inv.20mm - Offset 30mm (7)
In: Nivå F
Type - PredefinedType: CURTAIN_PANEL; Material: Metal - Steel
Pset_PlateCommon - IsExternal: no; Reference: A245 - Metallkasett Inv.20mm - Offset 30mm
ePset_LocationTool - Splitting: RESULT
Pset_QuantityTakeOff - Reference: A245 - Metallkasett Inv.20mm - Offset 30mm
ePset_Simplebim - Assembly Level: Leaf
AVINOR - 07_Fase: F90; 03_Ansvar: FDV; 08_Status: S2; 06_Omrade: TS; 01_Lufthavnkode: ENGM
Name (System Panel:A245 - Metallkasett Inv.20mm - Offset 30mm:...) | Area, largest surface, net (Simplebim) (m2) | Weight, as steel (Simplebim) (kg) | Volume, net (Simplebim) (m3)
30365267 | 0.573357 | 90.017 | 0.0114671
30365173 | 0.581105 | 91.2334 | 0.0116221
30365171 | 0.581105 | 91.2334 | 0.0116221
30365169 | 0.581105 | 91.2334 | 0.0116221
30365167 | 0.581105 | 91.2334 | 0.0116221
30365165 | 0.46476 | 72.9673 | 0.0092952
30365163 | 0.11619 | 18.2418 | 0.0023238

# IfcRailing: Railing:A247 Fendring - FE-S01 - Avviser, montert m. brakett mot dekke, 1 rør Ø=49 mm (3)
In: Nivå F
Material: <Unnamed>
ePset_LocationTool - Splitting: ORIGINAL
Pset_RailingCommon - Height: 1219.2 mm; Reference: A247 Fendring - FE-S01 - Avviser, montert m. brakett mot dekke, 1 rør Ø=49 mm; IsExternal: no
ePset_Simplebim - Assembly Level: Leaf
AVINOR - 07_Fase: F90; 06_Omrade: TS; 01_Lufthavnkode: ENGM
Pset_QuantityTakeOff - Reference: A247 Fendring - FE-S01 - Avviser, montert m. brakett mot dekke, 1 rør Ø=49 mm
Name (Railing:A247 Fendring - FE-S01 - Avviser, montert m. brakett mot dekke, 1 rør Ø=49 mm:...) | 03_Ansvar | 08_Status | Height (mm) | Length (mm) | Width (mm) | 02_Prosjekt
30361097 | FDV | S2 | 50 | 3106.83 | 50
46580032 | 182412 | S4 | 43.3013 | 4233 | 3809.82 | A161568 | AVINOR - 04_Kontrakt: 182251
47507171 | 182412 | S4 | 43.3013 | 4352.5 | 3860 | A173790 | AVINOR - 05_ID-nummer: +TS=254.014-IY0001

# IfcRoof: Basic Roof:A261 - stålplate - 1,5 (2)
Material: NO_Stål 1.5 mm
AVINOR - 08_Status: S4; 07_Fase: F90; 02_Prosjekt: A161568; 03_Ansvar: 182412; 04_Kontrakt: 182251; 06_Omrade: TS; 01_Lufthavnkode: ENGM
ePset_Simplebim - Assembly Level: Topmost
ePset_SimplebimBasicQuantities - Width: 185 mm; Height: 1.5 mm
Pset_QuantityTakeOff - Reference: A261 - stålplate - 1,5
Pset_RoofCommon - IsExternal: yes; Reference: A261 - stålplate - 1,5
Name (Basic Roof:A261 - stålplate - 1,5:...) | In | Volume, net (Simplebim) (m3) | Length (mm) | TotalArea (m2) = ProjectedArea (m2)
46579925 | Nivå F | 0.00273596 | 9859.31 | 1.82397
46579934 | Nivå F - 0,7 m | 0.0026731 | 9632.81 | 1.78207

# IfcRoof: Basic Roof:A261 - stålplate - 10 mm (5)
Material: NO_Stål 10 mm
AVINOR - 08_Status: S4; 07_Fase: F90; 02_Prosjekt: A161568; 03_Ansvar: 182412; 04_Kontrakt: 182251; 06_Omrade: TS; 01_Lufthavnkode: ENGM
Pset_QuantityTakeOff - Reference: A261 - stålplate - 10 mm
ePset_SimplebimBasicQuantities - Height: 10 mm
ePset_Simplebim - Assembly Level: Topmost
Pset_RoofCommon - Reference: A261 - stålplate - 10 mm; IsExternal: yes
Name (Basic Roof:A261 - stålplate - 10 mm:...) | In | Width (mm) | Length (mm) | Volume, net (Simplebim) (m3) | ProjectedArea (m2) = TotalArea (m2)
46580022 | Nivå F - 0,7 m | 75 | 4125 | 0.00309375 | 0.309375
46580073 | Nivå F - 0,7 m | 50 | 4431.5 | 0.00221575 | 0.221575
46580080 | Nivå F - 0,7 m | 50 | 4431.5 | 0.00221575 | 0.221575
46580087 | Nivå F - 0,7 m | 75 | 4125 | 0.00309375 | 0.309375
46580094 | Nivå F | 1923 | 17137 | 0.0284929 | 2.84929

# IfcSlab: 150*27787, PÅSTØP
In: F
Description: 150*27787; PredefinedType: FLOOR
AVINOR - 07_Fase: F90; 02_Prosjekt: T1; 03_Ansvar: FDV; 04_Kontrakt: FDV; 08_Status: S2; 06_Omrade: TS; 01_Lufthavnkode: ENGM
Pset_SlabCommon - LoadBearing: no; Reference: DSB-12794(?)
ePset_SimplebimBasicQuantities - Volume, net (Simplebim): 26.9138 m3; Perimeter (Simplebim): 58012 mm; Area, largest surface, net (Simplebim): 179.425 m2; Area, top, net (Simplebim): 179.425 m2; Thickness (Simplebim): 150 mm; Area, sides, net (Simplebim): 8.7018 m2
ePset_LocationTool - Splitting: RESULT
ePset_Simplebim - Assembly Level: Leaf
Tekla Common - Name: PÅSTØP; Top elevation: +210.830; Assembly mark: SB-7505(?); Grade: C30/37; Profile: 150*27787; Part mark: DSB-12794(?); Class: 262; Bottom elevation: +210.680

# IfcSlab: 150*45267 (2)
In: F
Description: 150*45267; PredefinedType: FLOOR
ePset_SimplebimBasicQuantities - Volume, net (Simplebim): 22.7333 m3; Thickness (Simplebim): 150 mm; Area, top, net (Simplebim): 151.555 m2; Area, largest surface, net (Simplebim): 151.555 m2; Perimeter (Simplebim): 50759.9 mm; Area, sides, net (Simplebim): 7.61399 m2
ePset_LocationTool - Splitting: RESULT
Pset_SlabCommon - Reference: DSS-5285(?); LoadBearing: no
AVINOR - 08_Status: S2; 06_Omrade: TS; 01_Lufthavnkode: ENGM
Tekla Common - Part mark: DSS-5285(?); Name: PÅSTØP; Profile: 150*45267; Assembly mark: SB-14775(?); Top elevation: +210.830; Grade: C30/37; Class: 262; Bottom elevation: +210.680
ePset_Simplebim - Assembly Level: Leaf
Name | 07_Fase | 02_Prosjekt | 03_Ansvar
PÅSTØP | F20 | A181143 | 187259
PÅSTØP | F90 | T1 | FDV | AVINOR - 04_Kontrakt: FDV

# IfcSlab: Basic Roof:A261 - stålplate - 1,5 (2)
PredefinedType: ROOF; Material: NO_Stål 1.5 mm
ePset_SimplebimBasicQuantities - Thickness (Simplebim): 1.5 mm
AVINOR - 08_Status: S4; 07_Fase: F90; 02_Prosjekt: A161568; 03_Ansvar: 182412; 04_Kontrakt: 182251; 06_Omrade: TS; 01_Lufthavnkode: ENGM
ePset_LocationTool - Splitting: ORIGINAL
ePset_Simplebim - Assembly Level: Leaf
Pset_QuantityTakeOff - Reference: A261 - stålplate - 1,5; sets with these values: 2
Pset_SlabCommon - IsExternal: yes; PitchAngle: 0 deg; Reference: A261 - stålplate - 1,5
Name (Basic Roof:A261 - stålplate - 1,5:...) | In | Area, sides, net (Simplebim) (m2) | Volume, net (Simplebim) (m3) | Area, largest surface, net (Simplebim) (m2) = Area, top, net (Simplebim) (m2) | Perimeter (Simplebim) (mm)
46579925 | Nivå F | 0.030133 | 0.00273596 | 1.82397 | 20088.7
46579934 | Nivå F - 0,7 m | 0.0294535 | 0.0026731 | 1.78207 | 19635.7

# IfcSlab: Basic Roof:A261 - stålplate - 10 mm (5)
PredefinedType: ROOF; Material: NO_Stål 10 mm
AVINOR - 08_Status: S4; 07_Fase: F90; 02_Prosjekt: A161568; 03_Ansvar: 182412; 04_Kontrakt: 182251; 06_Omrade: TS; 01_Lufthavnkode: ENGM
Pset_QuantityTakeOff - Reference: A261 - stålplate - 10 mm; sets with these values: 2
Pset_SlabCommon - Reference: A261 - stålplate - 10 mm; IsExternal: yes; PitchAngle: 0 deg
ePset_Simplebim - Assembly Level: Leaf
ePset_LocationTool - Splitting: ORIGINAL
ePset_SimplebimBasicQuantities - Thickness (Simplebim): 10 mm
Name (Basic Roof:A261 - stålplate - 10 mm:...) | In | Area, largest surface, net (Simplebim) (m2) = Area, top, net (Simplebim) (m2) | Area, sides, net (Simplebim) (m2) | Perimeter (Simplebim) (mm) | Volume, net (Simplebim) (m3)
46580022 | Nivå F - 0,7 m | 0.309375 | 0.084 | 8400 | 0.00309375
46580073 | Nivå F - 0,7 m | 0.221575 | 0.08963 | 8963 | 0.00221575
46580080 | Nivå F - 0,7 m | 0.221575 | 0.08963 | 8963 | 0.00221575
46580087 | Nivå F - 0,7 m | 0.309375 | 0.084 | 8400 | 0.00309375
46580094 | Nivå F | 2.84929 | 0.3812 | 38120 | 0.0284929

# IfcSlab: Floor:A251 - Innvendig lettak WHS, Floor:A251 - Innvendig lettak WHS:66999924
In: Nivå F
Type - PredefinedType: FLOOR; Material: T2_Gips Standard 12.5 mm, T2 - Kryssfiner 12 mm, Default 148 mm
ePset_LocationTool - Splitting: ORIGINAL
Pset_QuantityTakeOff - Reference: A251 - Innvendig lettak WHS; sets with these values: 2
ePset_SimplebimBasicQuantities - Perimeter (Simplebim): 22350.7 mm; Volume, net (Simplebim): 1.68461 m3; Area, sides, net (Simplebim): 3.8555 m2; Thickness (Simplebim): 172.5 mm; Area, top, net (Simplebim): 9.76583 m2; Area, largest surface, net (Simplebim): 9.76583 m2
ePset_Simplebim - Assembly Level: Leaf
AVINOR - 08_Status: S4; 07_Fase: F90; 03_Ansvar: 188110; 02_Prosjekt: 10004394; 06_Omrade: TS; 09_Arbeidspakke: SELV ARBEIDER; 01_Lufthavnkode: ENGM
Pset_SlabCommon - Reference: A251 - Innvendig lettak WHS; IsExternal: no; PitchAngle: 0 deg; LoadBearing: no

# IfcSlab: Floor:A254 - GU-B01 - Banebelegg 22 (3)
In: Nivå F
Type - PredefinedType: FLOOR; Material: _NSW Gulv (Generell) 4 mm, T2_Mørtel 18 mm
AVINOR - 08_Status: S4; 07_Fase: F90; 03_Ansvar: 182412; 02_Prosjekt: A173790; 05_ID-nummer: +TS=254.073; 06_Omrade: TS; 01_Lufthavnkode: ENGM
ePset_LocationTool - Splitting: ORIGINAL
ePset_Simplebim - Assembly Level: Leaf
Pset_ReinforcementBarPitchOfSlab - Reference: A254 - GU-B01 - Banebelegg 22; sets with these values: 2
Pset_SlabCommon - Reference: A254 - GU-B01 - Banebelegg 22; IsExternal: no; PitchAngle: 0 deg; LoadBearing: no
ePset_SimplebimBasicQuantities - Thickness (Simplebim): 22 mm
Name (Floor:A254 - GU-B01 - Banebelegg 22:...) | Area, top, net (Simplebim) (m2) = Area, largest surface, net (Simplebim) (m2) | Area, sides, net (Simplebim) (m2) | Perimeter (Simplebim) (mm) | Volume, net (Simplebim) (m3)
47507127 | 19.5327 | 0.438268 | 19921.3 | 0.429719
47507234 | 10.1799 | 0.342253 | 15557 | 0.223957
47507244 | 2.68823 | 0.150985 | 6862.96 | 0.0591404

# IfcSlab: Floor:A254 - GU-N05 - Naturstein inkl. lim 2, Floor:A254 - GU-N05 - Naturstein inkl. lim 2:72636332
In: Nivå F
Type - PredefinedType: FLOOR; Material: T2_Naturstein - Skiffer 20 mm, T2 - Dekke uten skravur 5 mm
ePset_LocationTool - Splitting: RESULT
ePset_Simplebim - Assembly Level: Leaf
ePset_SimplebimBasicQuantities - Perimeter (Simplebim): 74048 mm; Area, top, net (Simplebim): 332.759 m2; Area, largest surface, net (Simplebim): 332.759 m2; Volume, net (Simplebim): 8.31898 m3; Area, sides, net (Simplebim): 1.8512 m2; Thickness (Simplebim): 25 mm
Pset_ReinforcementBarPitchOfSlab - Reference: A254 - GU-N05 - Naturstein inkl. lim 2; sets with these values: 2
Pset_SlabCommon - IsExternal: no; LoadBearing: no; Reference: A254 - GU-N05 - Naturstein inkl. lim 2
AVINOR - 07_Fase: F90; 08_Status: S1; 03_Ansvar: FDV; 06_Omrade: TS; 01_Lufthavnkode: ENGM

# IfcSlab: Floor:A254 - Naturstein gulv Tilfeldig mønster (2)
In: Nivå F
Type - PredefinedType: FLOOR; Material: T2_Naturstein - Skiffer- Tilfeldig mønster2 20 mm
Type - Pset_ReinforcementBarPitchOfSlab - Description: eksisterende steingulv
Pset_SlabCommon - Reference: A254 - Naturstein gulv Tilfeldig mønster; IsExternal: no; PitchAngle: 0 deg; LoadBearing: no
Pset_QuantityTakeOff - Reference: A254 - Naturstein gulv Tilfeldig mønster; sets with these values: 2
AVINOR - 08_Status: S4; 07_Fase: F90; 03_Ansvar: 05.214; 02_Prosjekt: A173790; 06_Omrade: TS; 01_Lufthavnkode: ENGM
ePset_Simplebim - Assembly Level: Leaf
ePset_LocationTool - Splitting: ORIGINAL
ePset_SimplebimBasicQuantities - Thickness (Simplebim): 20 mm
Name (Floor:A254 - Naturstein gulv Tilfeldig mønster:...) | Volume, net (Simplebim) (m3) | Perimeter (Simplebim) (mm) | Area, top, net (Simplebim) (m2) = Area, largest surface, net (Simplebim) (m2) | Area, sides, net (Simplebim) (m2)
47507185 | 3.51711 | 57263.4 | 175.856 | 1.14527
47507257 | 1.32681 | 57652.1 | 66.3406 | 1.15304

# IfcSlab: TT800*2094-125-70-1200-0.04-0-0 (6)
In: F
Description: TT800*2094-125-70-1200-0.04-0-0; PredefinedType: FLOOR
Pset_SlabCommon - LoadBearing: no
AVINOR - 07_Fase: F90; 02_Prosjekt: T1; 03_Ansvar: FDV; 04_Kontrakt: FDV; 08_Status: S2; 06_Omrade: TS; 01_Lufthavnkode: ENGM
Tekla Common - Name: DT; Grade: C45/55; Bottom elevation: +209.880; Profile: TT800*2094-125-70-1200-0.04-0-0; Class: 164; Top elevation: +210.680
ePset_Simplebim - Assembly Level: Leaf
Name | Reference = Part mark | Splitting | Assembly mark | Area, largest surface, net (Simplebim) (m2) = Area, top, net (Simplebim) (m2) | Volume, net (Simplebim) (m3) | Area, sides, net (Simplebim) (m2) | Thickness (Simplebim) (mm) | Perimeter (Simplebim) (mm)
DT | Concrete-9276 | ORIGINAL | DT-340 | 14.5742 | 2.58712 | 22.0573 | 800 | 27571.6 | Material: CONCRETE/C45/55; Tekla Quantity - WEIGTH_NET: 6209.08 kg; WEIGTH_GROSS: 6209.08 kg; VOLUME_NET: 2.58712 m3; VOLUME_GROSS: 2.58712 m3; AREA_NET: 50.3928 m2; AREA_GROSS: 50.3928 m2; Heigth: 800 mm; Width: 2094 mm; Length: 6960 mm
DT | Concrete-5676 | ORIGINAL | DT-263 | 13.946 | 2.4756 | 21.1386 | 800 | 26423.2 | Material: CONCRETE/C45/55; Tekla Quantity - WEIGTH_NET: 5941.45 kg; WEIGTH_GROSS: 5941.45 kg; VOLUME_NET: 2.4756 m3; VOLUME_GROSS: 2.4756 m3; AREA_NET: 48.2528 m2; AREA_GROSS: 48.2528 m2; Heigth: 800 mm; Width: 2094 mm; Length: 6660.01 mm
2 x DT | Concrete-5836 | RESULT | DT-123 | 17.2441 | 3.01961 | 25.2924 | 780 | 32426.2
DT | Concrete-5836 | RESULT | DT-123 | 5.94565 | 1.32246 | 13.1772 | 780 | 16893.8
DT | Concrete-9276 | RESULT | DT-340 | 5.02509 | 1.1177 | 11.1867 | 780 | 14341.9

# IfcSlab: TT800*2394-125-70-1200-0.04-0-0 (14)
In: F
Description: TT800*2394-125-70-1200-0.04-0-0; PredefinedType: FLOOR
Pset_SlabCommon - LoadBearing: no
Tekla Common - Name: DT; Grade: C45/55; Bottom elevation: +209.880; Profile: TT800*2394-125-70-1200-0.04-0-0; Class: 164; Top elevation: +210.680
AVINOR - 07_Fase: F90; 02_Prosjekt: T1; 03_Ansvar: FDV; 04_Kontrakt: FDV; 08_Status: S2; 06_Omrade: TS; 01_Lufthavnkode: ENGM
ePset_Simplebim - Assembly Level: Leaf
Name | Reference = Part mark | Assembly mark | Volume, net (Simplebim) (m3) | Area, largest surface, net (Simplebim) (m2) = Area, top, net (Simplebim) (m2) | Thickness (Simplebim) (mm) | Perimeter (Simplebim) (mm) | Area, sides, net (Simplebim) (m2) | Splitting
DT | Concrete-728 | DT-122 | 2.73328 | 16.6622 | 800 | 27624.1 | 22.0993 | ORIGINAL | Material: CONCRETE/C45/55; Tekla Quantity - VOLUME_NET: 2.73328 m3; VOLUME_GROSS: 2.73328 m3; AREA_GROSS: 54.6108 m2; AREA_NET: 54.6108 m2; WEIGTH_GROSS: 6559.86 kg; WEIGTH_NET: 6559.86 kg; Heigth: 800 mm; Width: 2394 mm; Length: 6960 mm
DT | Concrete-4322 | DT-170 | 2.72824 | 16.5902 | 800 | 27624.1 | 22.0993 | ORIGINAL | Material: CONCRETE/C45/55; Tekla Quantity - VOLUME_NET: 2.72824 m3; VOLUME_GROSS: 2.73328 m3; AREA_GROSS: 54.6108 m2; AREA_NET: 54.4668 m2; WEIGTH_GROSS: 6559.86 kg; WEIGTH_NET: 6547.77 kg; Heigth: 800 mm; Width: 2394 mm; Length: 6960 mm
DT | Concrete-731 | DT-124 | 2.3953 | 14.7984 | 780 | 32225.8 | 25.1361 | RESULT
DT | Concrete-9409 | DT-352 | 2.06076 | 12.6946 | 780 | 28023.5 | 21.8583 | RESULT
6 x DT | Concrete-731 | DT-124 | 3.19255 | 19.7146 | 780 | 32480 | 25.3344 | RESULT
DT | Concrete-9404 | DT-347 | 2.74614 | 16.9046 | 780 | 28186.6 | 21.9856 | RESULT
DT | Concrete-731 | DT-124 | 2.75272 | 16.9986 | 780 | 28142.3 | 21.951 | RESULT
DT | Concrete-9421 | DT-364 | 2.74515 | 16.8905 | 780 | 28142.3 | 21.951 | RESULT
DT | Concrete-9403 | DT-346 | 2.74082 | 16.8285 | 780 | 28222.5 | 22.0136 | RESULT

# IfcSystem (33)
Name | Description
+TQ=360.010 T | +TQ=360.010 T
+TQ=360.010 A | +TQ=360.010 A
+TQ=360.020 A | +TQ=360.020 A
+TQ=360.020 T | +TQ=360.020 T
36= Tilluft 48 | 36= Tilluft 48
36= Tilluft 363 | 36= Tilluft 363
36= Tilluft 405 | 36= Tilluft 405
36= Tilluft 406 | 36= Tilluft 406
36= Tilluft 407 | 36= Tilluft 407
36= Tilluft 408 | 36= Tilluft 408
36= Tilluft 410 | 36= Tilluft 410
36= Tilluft 411 | 36= Tilluft 411
+TS=652.001 2 | +TS=652.001 2
Mechanical +TU=360.032Avt 1 | Mechanical +TU=360.032Avt 1
Mechanical +TU=360.032Avt 2 | Mechanical +TU=360.032Avt 2
+TQ=332.001 | +TQ=332.001
+TS=332.007 - 1 (1) | +TS=332.007 - 1 (1)
33= Våt Kopi 32 | 33= Våt Kopi 32
33= Våt Kopi 1 | 33= Våt Kopi 1
- | 574 | AVINOR - 08_Status: S4; 07_Fase: F90; 04_Kontrakt: 72512; 02_Prosjekt: 72101; 01_Lufthavnkode: ENGM; 05_ID-nummer: +TS=574.006-WD0276; MagiCAD Pset_System - Code: 574
Spredenett | 574 | AVINOR - 08_Status: S4; 07_Fase: F90; 04_Kontrakt: A173806; 02_Prosjekt: A173806; 01_Lufthavnkode: ENGM; 05_ID-nummer: +TQ=574.001-WD1140; MagiCAD Pset_System - Code: 574; Description: Spredenett
Brannalarm | 542 | AVINOR - 08_Status: S2; 07_Fase: F90; 04_Kontrakt: FDV; 02_Prosjekt: 72101; 01_Lufthavnkode: ENGM; 05_ID-nummer: +TO=542.024; MagiCAD Pset_System - Code: 542; Description: Brannalarm
7
2
1
8
Adgangskontroll, Innbruddsalarm | 543 | AVINOR - 08_Status: S4; 07_Fase: F90; 04_Kontrakt: 72561; 02_Prosjekt: 72101; 01_Lufthavnkode: ENGM; 05_ID-nummer: +TS=543.003-QG6301; 03_Ansvar: T20100; MagiCAD Pset_System - Code: 543; Description: Adgangskontroll, Innbruddsalarm
Brannspjeld | 542-DI | MagiCAD Pset_System - Code: 542-DI; Description: Brannspjeld
Bæresystem generelt | 4119 | MagiCAD Pset_System - Code: 4119; Description: Bæresystem generelt
Bæresystem for elkraft | 4111 | MagiCAD Pset_System - Code: 4111; Description: Bæresystem for elkraft
Bæresytem for tele- og automasjon | 5111 | MagiCAD Pset_System - Code: 5111; Description: Bæresytem for tele- og automasjon
Trekkerør for elkraft | 4114 | MagiCAD Pset_System - Code: 4114; Description: Trekkerør for elkraft
Trekkerør for tele- og automasjon | 5113 | MagiCAD Pset_System - Code: 5113; Description: Trekkerør for tele- og automasjon

# IfcWall: 1450*300, PLASSTØPTVEGG
In: D
Description: 1450*300
Tekla Common - Bottom elevation: +209.380; Assembly mark: PLV-2654; Name: PLASSTØPTVEGG; Top elevation: +210.830; Profile: 1450*300; Class: 250; Grade: C35/45; Part mark: Concrete-9139
AVINOR - 07_Fase: F90; 02_Prosjekt: T1; 03_Ansvar: FDV; 04_Kontrakt: FDV; 08_Status: S2; 06_Omrade: TS; 01_Lufthavnkode: ENGM
ePset_SimplebimBasicQuantities - Area, side, gross, AABB (Simplebim): 2.325 m2; Volume, net (Simplebim): 0.697499 m3; Thickness (Simplebim): 300 mm; Height (Simplebim): 930 mm; Length (Simplebim): 2500 mm; Area, side, net, larger (Simplebim): 2.325 m2; Area, side, gross, smaller (Simplebim): 2.325 m2; Area, side, gross, average (Simplebim): 2.325 m2; Area, side, net, average (Simplebim): 2.325 m2; Area, side, gross, larger (Simplebim): 2.325 m2; Area, largest surface, net (Simplebim): 2.325 m2; Area, side, net, smaller (Simplebim): 2.325 m2
Pset_WallCommon - LoadBearing: no; Reference: Concrete-9139
ePset_LocationTool - Splitting: RESULT
ePset_Simplebim - Assembly Level: Leaf

# IfcWall: Basic Wall:A231 - KL-K03 Metro Flis 10mm, Basic Wall:A231 - KL-K03 Metro Flis 10mm:66812352
In: Nivå F
Type - PredefinedType: STANDARD; Material: T2 - Flisvegg 200x100 10 mm
Pset_QuantityTakeOff - Reference: A231 - KL-K03 Metro Flis 10mm; sets with these values: 2
ePset_LocationTool - Splitting: ORIGINAL
Pset_WallCommon - IsExternal: yes; ExtendToStructure: no; LoadBearing: no; Reference: A231 - KL-K03 Metro Flis 10mm
ePset_SimplebimBasicQuantities - Area, side, gross, AABB (Simplebim): 5.75715 m2; Area, side, net, larger (Simplebim): 1.46755 m2; Area, side, gross, larger (Simplebim): 1.46755 m2; Area, largest surface, net (Simplebim): 1.46755 m2; Area, side, gross, smaller (Simplebim): 1.45964 m2; Area, side, net, smaller (Simplebim): 1.45964 m2; Area, side, net, average (Simplebim): 1.4636 m2; Area, side, gross, average (Simplebim): 1.4636 m2; Length (Simplebim): 2085.92 mm; Volume, net (Simplebim): 0.014636 m3; Thickness (Simplebim): 10 mm; Height (Simplebim): 2760 mm
AVINOR - 08_Status: S4; 07_Fase: F90; 03_Ansvar: 188110; 02_Prosjekt: 10004394; 06_Omrade: TS; 09_Arbeidspakke: SELV ARBEIDER; 01_Lufthavnkode: ENGM
ePset_Simplebim - Assembly Level: Leaf

# IfcWall: Basic Wall:A231 - KL-K06, Basic Wall:A231 - KL-K06:66961441
In: Nivå F
Type - PredefinedType: STANDARD; Material: T2_baderomspanel 2.5 mm
Pset_WallCommon - Reference: A231 - KL-K06; IsExternal: yes; ExtendToStructure: no; LoadBearing: no
ePset_SimplebimBasicQuantities - Area, largest surface, net (Simplebim): 7.21657 m2; Area, side, gross, average (Simplebim): 7.65442 m2; Area, side, net, average (Simplebim): 7.65442 m2; Area, side, net, larger (Simplebim): 7.65442 m2; Area, side, gross, smaller (Simplebim): 7.65442 m2; Area, side, gross, larger (Simplebim): 7.65442 m2; Area, side, net, smaller (Simplebim): 7.65442 m2; Length (Simplebim): 4713.53 mm; Volume, net (Simplebim): 0.019136 m3; Area, side, gross, AABB (Simplebim): 9.89842 m2; Thickness (Simplebim): 2.5 mm; Height (Simplebim): 2100 mm
AVINOR - 08_Status: S4; 07_Fase: F90; 09_Arbeidspakke: SELV ARBEIDER; 01_Lufthavnkode: ENGM
Pset_QuantityTakeOff - Reference: A231 - KL-K06; sets with these values: 2
ePset_Simplebim - Assembly Level: Leaf
ePset_LocationTool - Splitting: ORIGINAL

# IfcWall: Basic Wall:A231 - KL-K08, Basic Wall:A231 - KL-K08:67068896
In: Nivå F
Type - PredefinedType: STANDARD; Material: MDF plate grå 12 mm
ePset_LocationTool - Splitting: ORIGINAL
Pset_WallCommon - Reference: A231 - KL-K08; IsExternal: yes; ExtendToStructure: no; LoadBearing: no
AVINOR - 08_Status: S4; 07_Fase: F90; 01_Lufthavnkode: ENGM
Pset_QuantityTakeOff - Reference: A231 - KL-K08; sets with these values: 2
ePset_SimplebimBasicQuantities - Area, side, gross, AABB (Simplebim): 5.70082 m2; Thickness (Simplebim): 12 mm; Volume, net (Simplebim): 0.0641073 m3; Length (Simplebim): 3585.42 mm; Area, largest surface, net (Simplebim): 2.1154 m2; Height (Simplebim): 1590 mm; Area, side, net, smaller (Simplebim): 5.34227 m2; Area, side, gross, smaller (Simplebim): 5.34227 m2; Area, side, net, larger (Simplebim): 5.34227 m2; Area, side, net, average (Simplebim): 5.34227 m2; Area, side, gross, average (Simplebim): 5.34227 m2; Area, side, gross, larger (Simplebim): 5.34227 m2
ePset_Simplebim - Assembly Level: Leaf

# IfcWall: Basic Wall:A241 - FVF-100 (100/100 p-p), Basic Wall:A241 - FVF-100 (100/100 p-p):4890422
In: Nivå E
Type - PredefinedType: STANDARD; Material: T2_Gips Protect F 15 mm, _NSW Stålstender, uisolert 100 mm, T2_Gips Protect F 15 mm
Type - Pset_ReinforcementBarPitchOfWall - Description: Tilsvarende: T2 - IVEGG-150 - Forprosjekt
ePset_SimplebimBasicQuantities - Volume, net (Simplebim): 0.0663007 m3; Area, side, gross, AABB (Simplebim): 0.51 m2; Thickness (Simplebim): 130 mm; Height (Simplebim): 300 mm; Length (Simplebim): 1700 mm; Area, side, net, smaller (Simplebim): 0.510006 m2; Area, side, gross, larger (Simplebim): 0.510006 m2; Area, side, net, average (Simplebim): 0.510006 m2; Area, side, gross, average (Simplebim): 0.510006 m2; Area, side, gross, smaller (Simplebim): 0.510006 m2; Area, side, net, larger (Simplebim): 0.510006 m2; Area, largest surface, net (Simplebim): 0.510006 m2
Pset_WallCommon - Reference: A241 - FVF-100 (100/100 p-p); IsExternal: no; ExtendToStructure: no; LoadBearing: no
AVINOR - 07_Fase: F90; 03_Ansvar: FDV; 08_Status: S2; 06_Omrade: TS; 01_Lufthavnkode: ENGM
ePset_Simplebim - Assembly Level: Leaf
Pset_ReinforcementBarPitchOfWall - Reference: A241 - FVF-100 (100/100 p-p); sets with these values: 2
ePset_LocationTool - Splitting: RESULT
Identity Data - CQFireRequirement: E 30

# IfcWall: Basic Wall:A241 - GRVR-20 (100/100 r-r) (2)
Type - PredefinedType: STANDARD; Material: Plate - Gips 12.5 mm, _NSW Stålstender, uisolert 100 mm, Plate - Gips 12.5 mm
Pset_QuantityTakeOff - Reference: A241 - GRVR-20 (100/100 r-r); sets with these values: 2
Pset_WallCommon - IsExternal: no; ExtendToStructure: no; LoadBearing: no; Reference: A241 - GRVR-20 (100/100 r-r)
AVINOR - 07_Fase: F90; 03_Ansvar: FDV; 08_Status: S2; 06_Omrade: TS; 01_Lufthavnkode: ENGM
ePset_Simplebim - Assembly Level: Leaf
ePset_LocationTool - Splitting: RESULT
ePset_SimplebimBasicQuantities - Length (Simplebim): 1374 mm
Name (Basic Wall:A241 - GRVR-20 (100/100 r-r):...) | In | Area, side, gross, AABB (Simplebim) (m2) | Area, side, net, smaller (Simplebim) (m2) = Area, largest surface, net (Simplebim) (m2) = Area, side, net, average (Simplebim) (m2) = Area, side, net, larger (Simplebim) (m2) | Area, side, gross, average (Simplebim) (m2) = Area, side, gross, smaller (Simplebim) (m2) = Area, side, gross, larger (Simplebim) (m2) | Thickness (Simplebim) (mm) | Height (Simplebim) (mm) | Volume, net (Simplebim) (m3)
40491755 | Nivå G - 2,0m | 2.3358 | 2.33495 | 2.33495 | 125 | 1700 | 0.291869
40491755 | Nivå F | 3.8472 | 1.65699 | 4.86619 | 126 | 2800 | 0.207124

# IfcWall: Basic Wall:A241 - GSVS-30 (100/100 gg-gg) (3)
Type - PredefinedType: STANDARD; Material: Plate - Gips 12.5 mm, Plate - Gips 12.5 mm, _NSW Stålstender, uisolert 100 mm, Plate - Gips 12.5 mm, Plate - Gips 12.5 mm
ePset_SimplebimBasicQuantities - Thickness (Simplebim): 150 mm
Pset_ReinforcementBarPitchOfWall - Reference: A241 - GSVS-30 (100/100 gg-gg); sets with these values: 2
ePset_Simplebim - Assembly Level: Leaf
AVINOR - 07_Fase: F90; 06_Omrade: TS; 01_Lufthavnkode: ENGM
Pset_WallCommon - Reference: A241 - GSVS-30 (100/100 gg-gg); IsExternal: no; ExtendToStructure: no; LoadBearing: no
Name (Basic Wall:A241 - GSVS-30 (100/100 gg-gg):...) | In | Area, side, gross, AABB (Simplebim) (m2) | Area, largest surface, net (Simplebim) (m2) = Area, side, net, average (Simplebim) (m2) = Area, side, gross, average (Simplebim) (m2) = Area, side, gross, smaller (Simplebim) (m2) = Area, side, net, larger (Simplebim) (m2) = Area, side, gross, larger (Simplebim) (m2) = Area, side, net, smaller (Simplebim) (m2) | Volume, net (Simplebim) (m3) | Height (Simplebim) (mm) | Length (Simplebim) (mm) | Splitting | 08_Status | 03_Ansvar
46579948 | Nivå F | 10.5995 | 10.514 | 1.5771 | 2900 | 3655 | ORIGINAL | S4 | 182412 | AVINOR - 02_Prosjekt: A161568; 04_Kontrakt: 182251
40491768 | Nivå G - 2,0m | 2.3358 | 2.33495 | 0.350243 | 1700 | 1374 | RESULT | S2 | FDV
40491768 | Nivå F | 3.8472 | 3.8458 | 0.57687 | 2800 | 1374 | RESULT | S2 | FDV

# IfcWall: Basic Wall:A241 - GSVS-50 (100/100x2 gg-gg) (2)
Type - PredefinedType: STANDARD; Material: Plate - Gips 12.5 mm, Plate - Gips 12.5 mm, _NSW Stålstender, uisolert 200 mm, Plate - Gips 12.5 mm, Plate - Gips 12.5 mm
ePset_LocationTool - Splitting: RESULT
Pset_QuantityTakeOff - Reference: A241 - GSVS-50 (100/100x2 gg-gg); sets with these values: 2
ePset_SimplebimBasicQuantities - Thickness (Simplebim): 250 mm; Length (Simplebim): 1624 mm
AVINOR - 07_Fase: F90; 03_Ansvar: FDV; 08_Status: S2; 06_Omrade: TS; 01_Lufthavnkode: ENGM
ePset_Simplebim - Assembly Level: Leaf
Pset_WallCommon - Reference: A241 - GSVS-50 (100/100x2 gg-gg); IsExternal: no; ExtendToStructure: no; LoadBearing: no
Name (Basic Wall:A241 - GSVS-50 (100/100x2 gg-gg):...) | In | Volume, net (Simplebim) (m3) | Area, largest surface, net (Simplebim) (m2) = Area, side, gross, average (Simplebim) (m2) = Area, side, net, average (Simplebim) (m2) = Area, side, net, larger (Simplebim) (m2) = Area, side, gross, smaller (Simplebim) (m2) = Area, side, gross, larger (Simplebim) (m2) = Area, side, net, smaller (Simplebim) (m2) | Area, side, gross, AABB (Simplebim) (m2) | Height (Simplebim) (mm)
40491766 | Nivå G - 2,0m | 0.689988 | 2.75995 | 2.7608 | 1700
40491766 | Nivå F | 1.13645 | 4.5458 | 4.5472 | 2800

# IfcWall: Basic Wall:A241 - RXVXR-100, Basic Wall:A241 - RXVXR-100:46493957
In: Nivå F
Type - PredefinedType: STANDARD; Material: T2_Gips Fibergips 13 mm, T2 - Kryssfiner 15 mm, _NSW Stålstender, uisolert 100 mm, T2 - Kryssfiner 15 mm, T2_Gips Fibergips 13 mm
Type - Pset_ReinforcementBarPitchOfWall - Description: Tilsvarende: T2 - IVEGG-150 - Forprosjekt
ePset_SimplebimBasicQuantities - Area, largest surface, net (Simplebim): 0.7965 m2; Area, side, gross, larger (Simplebim): 0.7965 m2; Area, side, gross, AABB (Simplebim): 0.7965 m2; Area, side, net, average (Simplebim): 0.7965 m2; Area, side, gross, average (Simplebim): 0.7965 m2; Area, side, gross, smaller (Simplebim): 0.7965 m2; Area, side, net, larger (Simplebim): 0.7965 m2; Area, side, net, smaller (Simplebim): 0.7965 m2; Volume, net (Simplebim): 0.124254 m3; Thickness (Simplebim): 156 mm; Length (Simplebim): 354 mm; Height (Simplebim): 2250 mm
Pset_ReinforcementBarPitchOfWall - Reference: A241 - RXVXR-100; sets with these values: 2
ePset_LocationTool - Splitting: RESULT
Pset_WallCommon - Reference: A241 - RXVXR-100; IsExternal: no; ExtendToStructure: no; LoadBearing: no
ePset_Simplebim - Assembly Level: Leaf
AVINOR - 08_Status: S4; 07_Fase: F90; 06_Omrade: TS; 03_Ansvar: OSL; 01_Lufthavnkode: ENGM; 02_Prosjekt: AO205066

# IfcWall: Basic Wall:A241 - SSVXR-150, Basic Wall:A241 - SSVXR-150:46493178
In: Nivå F
Type - PredefinedType: STANDARD; Material: Plate - Gips 12.5 mm, Plate - Gips 12.5 mm, _NSW Stålstender, uisolert 148 mm, T2 - Kryssfiner 15 mm, T2_Gips Robust 12.5 mm
Type - Pset_ReinforcementBarPitchOfWall - Description: Tilsvarende: T2 - IVEGG-150 - Forprosjekt
Pset_QuantityTakeOff - Reference: A241 - SSVXR-150; sets with these values: 2
Pset_WallCommon - IsExternal: no; ExtendToStructure: no; LoadBearing: no; Reference: A241 - SSVXR-150
ePset_SimplebimBasicQuantities - Volume, net (Simplebim): 1.17072 m3; Thickness (Simplebim): 200.5 mm; Height (Simplebim): 2760 mm; Length (Simplebim): 2138.5 mm; Area, side, gross, AABB (Simplebim): 5.90226 m2; Area, side, net, larger (Simplebim): 5.83902 m2; Area, side, gross, smaller (Simplebim): 5.83902 m2; Area, side, gross, average (Simplebim): 5.83902 m2; Area, side, net, average (Simplebim): 5.83902 m2; Area, side, gross, larger (Simplebim): 5.83902 m2; Area, largest surface, net (Simplebim): 5.83902 m2; Area, side, net, smaller (Simplebim): 5.83902 m2
ePset_Simplebim - Assembly Level: Leaf
AVINOR - 08_Status: S4; 07_Fase: F90; 06_Omrade: TS; 03_Ansvar: OSL; 01_Lufthavnkode: ENGM; 02_Prosjekt: AO205066
ePset_LocationTool - Splitting: ORIGINAL

# IfcWall: Basic Wall:A241 - SXVS-100 (3)
Type - PredefinedType: STANDARD; Material: Plate - Gips 12.5 mm, _NSW X-finer 15 mm, _NSW Stålstender, uisolert 100 mm, Plate - Gips 12.5 mm
Type - Pset_ReinforcementBarPitchOfWall - Description: 12,5mm Gipsplatter - 15mm X-finer - Stendervegg 100mm
ePset_LocationTool - Splitting: ORIGINAL
Pset_ReinforcementBarPitchOfWall - Reference: A241 - SXVS-100; sets with these values: 2
Pset_WallCommon - Reference: A241 - SXVS-100; IsExternal: no; ExtendToStructure: no; LoadBearing: no
ePset_SimplebimBasicQuantities - Thickness (Simplebim): 140 mm
AVINOR - 08_Status: S4; 07_Fase: F90; 05_ID-nummer: +TS=241.059; 03_Ansvar: 182412; 02_Prosjekt: A173790; 06_Omrade: TS; 01_Lufthavnkode: ENGM
ePset_Simplebim - Assembly Level: Leaf
Name (Basic Wall:A241 - SXVS-100:...) | In | Volume, net (Simplebim) (m3) | Area, side, gross, AABB (Simplebim) (m2) | Area, side, net, smaller (Simplebim) (m2) = Area, side, net, average (Simplebim) (m2) = Area, side, net, larger (Simplebim) (m2) = Area, largest surface, net (Simplebim) (m2) | Area, side, gross, smaller (Simplebim) (m2) = Area, side, gross, larger (Simplebim) (m2) = Area, side, gross, average (Simplebim) (m2) | Height (Simplebim) (mm) | Length (Simplebim) (mm)
47507175 | Nivå F | 6.35721 | 48.575 | 45.4087 | 48.1728 | 2900 | 16750
47507176 | Nivå F | 0.674939 | 4.92123 | 4.82099 | 4.82099 | 2778 | 1771.5
47507176 | Nivå G - 2,0m | 0.0629945 | 0.449961 | 0.449961 | 0.449961 | 254 | 1771.5

# IfcWall: Basic Wall:A241 - V4, Basic Wall:A241 - V4:46579946
In: Nivå F
Type - PredefinedType: STANDARD; Material: T2_Fibersement 15 mm, T2_X-finer 12 mm, _NSW Stålstender, uisolert 100 mm, T2_svartorfinert X-finer 12 mm
Type - Pset_ReinforcementBarPitchOfWall - Description: økt toalettkapasitet i pir øst nivå F - 72101-A127372
ePset_LocationTool - Splitting: ORIGINAL
ePset_SimplebimBasicQuantities - Area, largest surface, net (Simplebim): 4.71898 m2; Area, side, net, larger (Simplebim): 4.71898 m2; Area, side, gross, smaller (Simplebim): 4.71898 m2; Area, side, gross, average (Simplebim): 4.71898 m2; Area, side, net, average (Simplebim): 4.71898 m2; Area, side, gross, larger (Simplebim): 4.71898 m2; Area, side, net, smaller (Simplebim): 4.71898 m2; Volume, net (Simplebim): 0.655938 m3; Length (Simplebim): 1721.5 mm; Area, side, gross, AABB (Simplebim): 4.8202 m2; Thickness (Simplebim): 139 mm; Height (Simplebim): 2800 mm
ePset_Simplebim - Assembly Level: Leaf
Pset_QuantityTakeOff - Reference: A241 - V4; sets with these values: 2
AVINOR - 08_Status: S4; 07_Fase: F90; 02_Prosjekt: A161568; 03_Ansvar: 182412; 04_Kontrakt: 182251; 06_Omrade: TS; 01_Lufthavnkode: ENGM
Pset_WallCommon - IsExternal: no; ExtendToStructure: no; LoadBearing: no; Reference: A241 - V4

# IfcWallStandardCase: Basic Wall:A200 - Branngips 15 mm, Basic Wall:A200 - Branngips 15 mm:67445220
In: Nivå F
Type - PredefinedType: STANDARD; Material: T2_Gips Protect F 15 mm
Pset_WallCommon - Reference: A200 - Branngips 15 mm; IsExternal: no; ExtendToStructure: no; LoadBearing: no
ePset_LocationTool - Splitting: ORIGINAL
ePset_SimplebimBasicQuantities - Area, side, net, larger (Simplebim): 11.2115 m2; Area, side, net, average (Simplebim): 11.2115 m2; Area, largest surface, net (Simplebim): 11.2115 m2; Area, side, net, smaller (Simplebim): 11.2115 m2; Volume, net (Simplebim): 0.168172 m3; Thickness (Simplebim): 15 mm; Length (Simplebim): 4694.78 mm; Area, side, gross, average (Simplebim): 13.3426 m2; Area, side, gross, smaller (Simplebim): 13.3426 m2; Area, side, gross, larger (Simplebim): 13.3426 m2; Area, side, gross, AABB (Simplebim): 13.3426 m2; Height (Simplebim): 2842 mm
AVINOR - 08_Status: S4; 07_Fase: F90; 03_Ansvar: 188110; 02_Prosjekt: 10004394; 06_Omrade: TS; 09_Arbeidspakke: SELV ARBEIDER; 01_Lufthavnkode: ENGM
ePset_Simplebim - Assembly Level: Leaf
Pset_QuantityTakeOff - Reference: A200 - Branngips 15 mm; sets with these values: 2

# IfcWallStandardCase: Basic Wall:A231 - KL-K03 Metro Flis 10mm (2)
In: Nivå F
Type - PredefinedType: STANDARD; Material: T2 - Flisvegg 200x100 10 mm
Pset_QuantityTakeOff - Reference: A231 - KL-K03 Metro Flis 10mm; sets with these values: 2
ePset_LocationTool - Splitting: ORIGINAL
ePset_SimplebimBasicQuantities - Thickness (Simplebim): 10 mm
Pset_WallCommon - IsExternal: yes; ExtendToStructure: no; LoadBearing: no; Reference: A231 - KL-K03 Metro Flis 10mm
AVINOR - 08_Status: S4; 07_Fase: F90; 03_Ansvar: 188110; 02_Prosjekt: 10004394; 06_Omrade: TS; 09_Arbeidspakke: SELV ARBEIDER; 01_Lufthavnkode: ENGM
ePset_Simplebim - Assembly Level: Leaf
Name (Basic Wall:A231 - KL-K03 Metro Flis 10mm:...) | Area, side, gross, larger (Simplebim) (m2) = Area, side, gross, smaller (Simplebim) (m2) = Area, side, net, larger (Simplebim) (m2) = Area, side, net, average (Simplebim) (m2) = Area, side, gross, average (Simplebim) (m2) = Area, largest surface, net (Simplebim) (m2) = Area, side, net, smaller (Simplebim) (m2) | Area, side, gross, AABB (Simplebim) (m2) | Volume, net (Simplebim) (m3) | Height (Simplebim) (mm) | Length (Simplebim) (mm)
66810771 | 1.19334 | 1.20126 | 0.0119334 | 600.729 | 1999.67
66812414 | 2.37343 | 2.37343 | 0.0237343 | 2760 | 859.939

# IfcWallStandardCase: Basic Wall:A231 - KL-K04 Tegl Flis 20mm, Basic Wall:A231 - KL-K04 Tegl Flis 20mm:66860686
In: Nivå F
Type - PredefinedType: STANDARD; Material: T2 - Flisvegg Tegl 260x65 20 mm, T2_Mørtel 7 mm
ePset_SimplebimBasicQuantities - Area, side, net, smaller (Simplebim): 5.20248 m2; Area, side, net, larger (Simplebim): 5.20248 m2; Area, side, net, average (Simplebim): 5.20248 m2; Area, largest surface, net (Simplebim): 5.20248 m2; Area, side, gross, smaller (Simplebim): 7.33358 m2; Area, side, gross, average (Simplebim): 7.33358 m2; Area, side, gross, larger (Simplebim): 7.33358 m2; Area, side, gross, AABB (Simplebim): 7.33358 m2; Thickness (Simplebim): 27 mm; Length (Simplebim): 3273.92 mm; Volume, net (Simplebim): 0.140467 m3; Height (Simplebim): 2240 mm
AVINOR - 08_Status: S4; 07_Fase: F90; 03_Ansvar: 188110; 02_Prosjekt: 10004394; 06_Omrade: TS; 09_Arbeidspakke: SELV ARBEIDER; 01_Lufthavnkode: ENGM
ePset_Simplebim - Assembly Level: Leaf
Pset_ReinforcementBarPitchOfWall - Reference: A231 - KL-K04 Tegl Flis 20mm; sets with these values: 2
Pset_WallCommon - Reference: A231 - KL-K04 Tegl Flis 20mm; IsExternal: yes; ExtendToStructure: no; LoadBearing: no
ePset_LocationTool - Splitting: ORIGINAL

# IfcWallStandardCase: Basic Wall:A231 - KL-K06 (3)
In: Nivå F
Type - PredefinedType: STANDARD; Material: T2_baderomspanel 2.5 mm
ePset_LocationTool - Splitting: ORIGINAL
Pset_WallCommon - Reference: A231 - KL-K06; IsExternal: yes; ExtendToStructure: no; LoadBearing: no
AVINOR - 08_Status: S4; 07_Fase: F90; 09_Arbeidspakke: SELV ARBEIDER; 01_Lufthavnkode: ENGM
Pset_QuantityTakeOff - Reference: A231 - KL-K06; sets with these values: 2
ePset_SimplebimBasicQuantities - Thickness (Simplebim): 2.5 mm; Height (Simplebim): 1200 mm
ePset_Simplebim - Assembly Level: Leaf
Name (Basic Wall:A231 - KL-K06:...) | Area, side, gross, AABB (Simplebim) (m2) = Area, largest surface, net (Simplebim) (m2) = Area, side, gross, average (Simplebim) (m2) = Area, side, net, average (Simplebim) (m2) = Area, side, net, larger (Simplebim) (m2) = Area, side, gross, smaller (Simplebim) (m2) = Area, side, gross, larger (Simplebim) (m2) = Area, side, net, smaller (Simplebim) (m2) | Volume, net (Simplebim) (m3) | Length (Simplebim) (mm)
66963154 | 0.861275 | 0.00215319 | 717.729
66963175 | 0.123 | 0.0003075 | 102.5
66963194 | 0.861275 | 0.00215319 | 717.729

# IfcWallStandardCase: Basic Wall:A241 - FVF-100 (100/100 p-p) (3)
Type - PredefinedType: STANDARD; Material: T2_Gips Protect F 15 mm, _NSW Stålstender, uisolert 100 mm, T2_Gips Protect F 15 mm
Type - Pset_ReinforcementBarPitchOfWall - Description: Tilsvarende: T2 - IVEGG-150 - Forprosjekt
ePset_SimplebimBasicQuantities - Thickness (Simplebim): 130 mm
ePset_LocationTool - Splitting: ORIGINAL
Pset_WallCommon - Reference: A241 - FVF-100 (100/100 p-p); IsExternal: no; ExtendToStructure: no; LoadBearing: no
AVINOR - 07_Fase: F90; 03_Ansvar: FDV; 08_Status: S2; 06_Omrade: TS; 01_Lufthavnkode: ENGM
ePset_Simplebim - Assembly Level: Leaf
Pset_ReinforcementBarPitchOfWall - Reference: A241 - FVF-100 (100/100 p-p); sets with these values: 2
Name (Basic Wall:A241 - FVF-100 (100/100 p-p):...) | In | Volume, net (Simplebim) (m3) | Height (Simplebim) (mm) | Length (Simplebim) (mm) | Area, side, gross, AABB (Simplebim) (m2) = Area, side, gross, larger (Simplebim) (m2) = Area, side, gross, smaller (Simplebim) (m2) = Area, side, gross, average (Simplebim) (m2) | Area, side, net, larger (Simplebim) (m2) = Area, side, net, average (Simplebim) (m2) = Area, largest surface, net (Simplebim) (m2) = Area, side, net, smaller (Simplebim) (m2) | CQFireRequirement
3113292 | Nivå F | 0.460642 | 2800 | 2000 | 5.6 | 3.5434 | EI 60/ A2-s1,d0
3113292 | Nivå G - 2,0m | 0.442 | 1700 | 2000 | 3.4 | 3.4 | EI 60/ A2-s1,d0
4890422 | Nivå F - 0,7 m | 0.154702 | 700 | 1700.02 | 1.19001 | 1.19001 | E 30

# IfcWallStandardCase: Basic Wall:A241 - FVF-170 (170/170 p-p) (4)
Type - PredefinedType: STANDARD; Material: _NSW Gips-Lydplate 15 mm, _NSW Stålstender, uisolert 170 mm, _NSW Gips-Lydplate 15 mm
Pset_QuantityTakeOff - Reference: A241 - FVF-170 (170/170 p-p); sets with these values: 2
ePset_SimplebimBasicQuantities - Length (Simplebim): 200 mm
AVINOR - 07_Fase: F90; 03_Ansvar: FDV; 08_Status: S2; 06_Omrade: TS; 01_Lufthavnkode: ENGM
Identity Data - CQFireRequirement: EI 60/ A2-s1,d0
ePset_Simplebim - Assembly Level: Leaf
ePset_LocationTool - Splitting: ORIGINAL
Pset_WallCommon - Reference: A241 - FVF-170 (170/170 p-p); IsExternal: no; ExtendToStructure: no; LoadBearing: no
Name (Basic Wall:A241 - FVF-170 (170/170 p-p):...) | In | Area, side, net, larger (Simplebim) (m2) = Area, side, gross, smaller (Simplebim) (m2) = Area, side, gross, average (Simplebim) (m2) = Area, side, net, average (Simplebim) (m2) = Area, side, gross, larger (Simplebim) (m2) = Area, side, net, smaller (Simplebim) (m2) | Height (Simplebim) (mm) | Volume, net (Simplebim) (m3) | Area, side, gross, AABB (Simplebim) (m2) = Area, largest surface, net (Simplebim) (m2) | Thickness (Simplebim) (mm)
3113290 | Nivå F | 0.49658 | 2800 | 0.099316 | 0.56 | 177.35
3113290 | Nivå G - 2,0m | 0.301495 | 1700 | 0.060299 | 0.34 | 177.35
3113291 | Nivå F | 0.449225 | 2800 | 0.089845 | 0.56 | 160.438
3113291 | Nivå G - 2,0m | 0.272744 | 1700 | 0.0545487 | 0.34 | 160.438

# IfcWallStandardCase: Basic Wall:A241 - GRVR-20 (100/100 r-r) (2)
Type - PredefinedType: STANDARD; Material: Plate - Gips 12.5 mm, _NSW Stålstender, uisolert 100 mm, Plate - Gips 12.5 mm
Pset_QuantityTakeOff - Reference: A241 - GRVR-20 (100/100 r-r); sets with these values: 2
Pset_WallCommon - IsExternal: no; ExtendToStructure: no; LoadBearing: no; Reference: A241 - GRVR-20 (100/100 r-r)
ePset_LocationTool - Splitting: ORIGINAL
AVINOR - 07_Fase: F90; 03_Ansvar: FDV; 08_Status: S2; 06_Omrade: TS; 01_Lufthavnkode: ENGM
ePset_SimplebimBasicQuantities - Thickness (Simplebim): 125 mm; Length (Simplebim): 1520.5 mm
ePset_Simplebim - Assembly Level: Leaf
Name (Basic Wall:A241 - GRVR-20 (100/100 r-r):...) | In | Area, side, gross, AABB (Simplebim) (m2) = Area, largest surface, net (Simplebim) (m2) = Area, side, gross, average (Simplebim) (m2) = Area, side, net, average (Simplebim) (m2) = Area, side, net, larger (Simplebim) (m2) = Area, side, gross, smaller (Simplebim) (m2) = Area, side, gross, larger (Simplebim) (m2) = Area, side, net, smaller (Simplebim) (m2) | Height (Simplebim) (mm) | Volume, net (Simplebim) (m3)
40491756 | Nivå F | 4.2574 | 2800 | 0.532175
40491756 | Nivå G - 2,0m | 2.58485 | 1700 | 0.323106

# IfcWallStandardCase: Basic Wall:A241 - GSVS-50 (100/100x2 gg-gg) (5)
Type - PredefinedType: STANDARD; Material: Plate - Gips 12.5 mm, Plate - Gips 12.5 mm, _NSW Stålstender, uisolert 200 mm, Plate - Gips 12.5 mm, Plate - Gips 12.5 mm
Pset_QuantityTakeOff - Reference: A241 - GSVS-50 (100/100x2 gg-gg); sets with these values: 2
ePset_LocationTool - Splitting: ORIGINAL
ePset_SimplebimBasicQuantities - Thickness (Simplebim): 250 mm
ePset_Simplebim - Assembly Level: Leaf
AVINOR - 07_Fase: F90; 06_Omrade: TS; 01_Lufthavnkode: ENGM
Pset_WallCommon - Reference: A241 - GSVS-50 (100/100x2 gg-gg); IsExternal: no; ExtendToStructure: no; LoadBearing: no
Name (Basic Wall:A241 - GSVS-50 (100/100x2 gg-gg):...) | In | Height (Simplebim) (mm) | Volume, net (Simplebim) (m3) | Area, side, gross, AABB (Simplebim) (m2) = Area, side, gross, larger (Simplebim) (m2) = Area, side, gross, average (Simplebim) (m2) = Area, side, net, average (Simplebim) (m2) = Area, side, net, larger (Simplebim) (m2) = Area, side, gross, smaller (Simplebim) (m2) = Area, largest surface, net (Simplebim) (m2) = Area, side, net, smaller (Simplebim) (m2) | Length (Simplebim) (mm) | 08_Status | 03_Ansvar | 02_Prosjekt
40487483 | Nivå F | 2900 | 7.45988 | 29.8395 | 10289.5 | S4 | OSL | AO205066
40491767 | Nivå F | 2800 | 3.0569 | 12.2276 | 4367 | S2 | FDV
40491767 | Nivå G - 2,0m | 1700 | 1.85597 | 7.4239 | 4367 | S2 | FDV
46579947 | Nivå F | 2900 | 1.52975 | 6.119 | 2110 | S4 | 182412 | A161568 | AVINOR - 04_Kontrakt: 182251
46580029 | Nivå F | 2800 | 8.67475 | 34.699 | 12392.5 | S4 | 182412 | A161568 | AVINOR - 04_Kontrakt: 182251

# IfcWallStandardCase: Basic Wall:A241 - KJØLEVEGG-100MM (6)
In: Nivå F
Type - PredefinedType: STANDARD; Material: Kjølevegg 100 mm
Pset_WallCommon - Reference: A241 - KJØLEVEGG-100MM; IsExternal: no; ExtendToStructure: no; LoadBearing: no
ePset_LocationTool - Splitting: ORIGINAL
Pset_QuantityTakeOff - Reference: A241 - KJØLEVEGG-100MM; sets with these values: 2
ePset_SimplebimBasicQuantities - Thickness (Simplebim): 100 mm; Height (Simplebim): 2400 mm
AVINOR - 08_Status: S4; 07_Fase: F90; 03_Ansvar: 05.214; 02_Prosjekt: A173790; 06_Omrade: TS; 01_Lufthavnkode: ENGM
ePset_Simplebim - Assembly Level: Leaf
Name (Basic Wall:A241 - KJØLEVEGG-100MM:...) | Length (Simplebim) (mm) | Area, side, gross, AABB (Simplebim) (m2) = Area, side, gross, larger (Simplebim) (m2) = Area, side, gross, average (Simplebim) (m2) = Area, side, gross, smaller (Simplebim) (m2) | Area, side, net, smaller (Simplebim) (m2) = Area, largest surface, net (Simplebim) (m2) = Area, side, net, average (Simplebim) (m2) = Area, side, net, larger (Simplebim) (m2) | Volume, net (Simplebim) (m3)
67393515 | 5352.29 | 12.8455 | 12.8455 | 1.28455
67393516 | 1365 | 3.276 | 1.1449 | 0.11449
67393517 | 3229.29 | 7.75029 | 7.75029 | 0.775029
67393518 | 2625.5 | 6.3012 | 6.3012 | 0.63012
67393520 | 2223 | 5.3352 | 5.3352 | 0.53352
67393521 | 1160.5 | 2.7852 | 2.7852 | 0.27852

# IfcWallStandardCase: Basic Wall:A241 - RV-75 (8)
In: Nivå F
Type - PredefinedType: STANDARD; Material: Plate - Gips 12.5 mm, _NSW Stålstender, uisolert 75 mm
Type - Pset_ConcreteElementGeneral - FireRating: EI30
Type - Pset_WallCommon - FireRating: EI30; AcousticRating: 37dB
Pset_ReinforcementBarPitchOfWall - Reference: A241 - RV-75; sets with these values: 2
ePset_SimplebimBasicQuantities - Thickness (Simplebim): 87.5 mm
AVINOR - 08_Status: S4; 07_Fase: F90; 03_Ansvar: 188110; 02_Prosjekt: 10004394; 06_Omrade: TS; 09_Arbeidspakke: SELV ARBEIDER; 01_Lufthavnkode: ENGM
ePset_LocationTool - Splitting: ORIGINAL
Pset_WallCommon - Reference: A241 - RV-75; IsExternal: no; ExtendToStructure: no; LoadBearing: no
ePset_Simplebim - Assembly Level: Leaf
Name (Basic Wall:A241 - RV-75:...) | Height (Simplebim) (mm) | Volume, net (Simplebim) (m3) | Length (Simplebim) (mm) | Area, side, gross, AABB (Simplebim) (m2) = Area, side, gross, larger (Simplebim) (m2) = Area, side, net, larger (Simplebim) (m2) = Area, largest surface, net (Simplebim) (m2) | Area, side, gross, average (Simplebim) (m2) = Area, side, net, average (Simplebim) (m2) | Area, side, gross, smaller (Simplebim) (m2) = Area, side, net, smaller (Simplebim) (m2)
66772833 | 2900 | 0.175473 | 691.519 | 2.0054 | 2.0054 | 2.0054 | AVINOR - 04_Kontrakt: 187110
66773115 | 2900 | 0.132711 | 523 | 1.5167 | 1.5167 | 1.5167
66773116 | 2900 | 0.153397 | 604.519 | 1.7531 | 1.7531 | 1.7531
66774611 | 2847.5 | 0.218915 | 878.626 | 2.50189 | 2.50189 | 2.50189
66774885 | 2847.5 | 0.177683 | 804.011 | 2.28942 | 2.03066 | 1.7719
66775216 | 2847.5 | 0.205308 | 881.713 | 2.51068 | 2.34637 | 2.18207
66775341 | 2847.5 | 0.175137 | 760.622 | 2.16587 | 2.00157 | 1.83726
66863518 | 2900 | 0.110508 | 435.5 | 1.26295 | 1.26295 | 1.26295 | AVINOR - 04_Kontrakt: 187110

# IfcWallStandardCase: Basic Wall:A241 - RVR-100 (2)
Type - PredefinedType: STANDARD; Material: Plate - Gips 12.5 mm, _NSW Stålstender, uisolert 100 mm, Plate - Gips 12.5 mm
Type - Pset_ReinforcementBarPitchOfWall - Description: Tilsvarende: T2 - IVEGG-150 - Forprosjekt
Pset_WallCommon - IsExternal: no; ExtendToStructure: no; LoadBearing: no; Reference: A241 - RVR-100
ePset_SimplebimBasicQuantities - Thickness (Simplebim): 125 mm; Length (Simplebim): 3156.29 mm
Pset_ReinforcementBarPitchOfWall - Reference: A241 - RVR-100; sets with these values: 2
AVINOR - 07_Fase: F90; 03_Ansvar: FDV; 08_Status: S2; 06_Omrade: TS; 01_Lufthavnkode: ENGM
ePset_Simplebim - Assembly Level: Leaf
ePset_LocationTool - Splitting: ORIGINAL
Name (Basic Wall:A241 - RVR-100:...) | In | Volume, net (Simplebim) (m3) | Height (Simplebim) (mm) | Area, side, gross, larger (Simplebim) (m2) = Area, side, gross, average (Simplebim) (m2) = Area, side, net, average (Simplebim) (m2) = Area, side, net, larger (Simplebim) (m2) = Area, side, gross, smaller (Simplebim) (m2) = Area, largest surface, net (Simplebim) (m2) = Area, side, net, smaller (Simplebim) (m2) = Area, side, gross, AABB (Simplebim) (m2)
31014779 | Nivå F | 1.10076 | 2790 | 8.80604
31014779 | Nivå G - 2,0m | 0.193323 | 490 | 1.54658

# IfcWallStandardCase: Basic Wall:A241 - RVR-75.1 (4)
Type - PredefinedType: STANDARD; Material: Plate - Gips 12.5 mm, _NSW Stålstender, uisolert 75 mm, Plate - Gips 12.5 mm
Type - Pset_ConcreteElementGeneral - FireRating: EI30
Type - Pset_WallCommon - FireRating: EI30
Pset_ReinforcementBarPitchOfWall - Reference: A241 - RVR-75.1; sets with these values: 2
Pset_WallCommon - IsExternal: no; ExtendToStructure: no; LoadBearing: no; Reference: A241 - RVR-75.1
ePset_SimplebimBasicQuantities - Thickness (Simplebim): 100 mm
ePset_Simplebim - Assembly Level: Leaf
ePset_LocationTool - Splitting: ORIGINAL
Name (Basic Wall:A241 - RVR-75.1:...) | In | 08_Status | 07_Fase | 03_Ansvar | 02_Prosjekt | 06_Omrade | 01_Lufthavnkode | Area, side, gross, larger (Simplebim) (m2) = Area, side, gross, AABB (Simplebim) (m2) = Area, side, gross, average (Simplebim) (m2) = Area, side, gross, smaller (Simplebim) (m2) | Height (Simplebim) (mm) | Area, side, net, smaller (Simplebim) (m2) = Area, side, net, larger (Simplebim) (m2) = Area, side, net, average (Simplebim) (m2) = Area, largest surface, net (Simplebim) (m2) | Volume, net (Simplebim) (m3) | Length (Simplebim) (mm)
66782194 | Nivå F | S4 | F90 | 188110 | 10004394 | TS | ENGM | 7.6608 | 2800 | 5.5297 | 0.55297 | 2736 | Identity Data - CQFireRequirement: EI30; AVINOR - 04_Kontrakt: 187110; 05_ID-nummer: +TS=241.543
66782194 | Nivå G - 2,0m | S4 | F90 | 188110 | 10004394 | TS | ENGM | 0.5472 | 200 | 0.5472 | 0.05472 | 2736 | Identity Data - CQFireRequirement: EI30; AVINOR - 04_Kontrakt: 187110; 05_ID-nummer: +TS=241.543
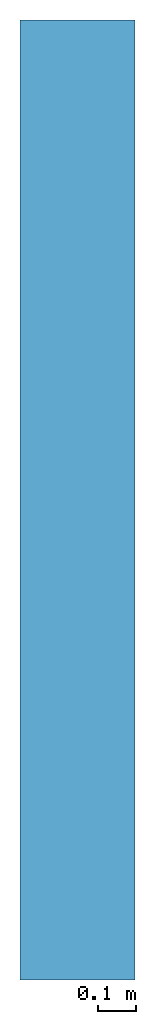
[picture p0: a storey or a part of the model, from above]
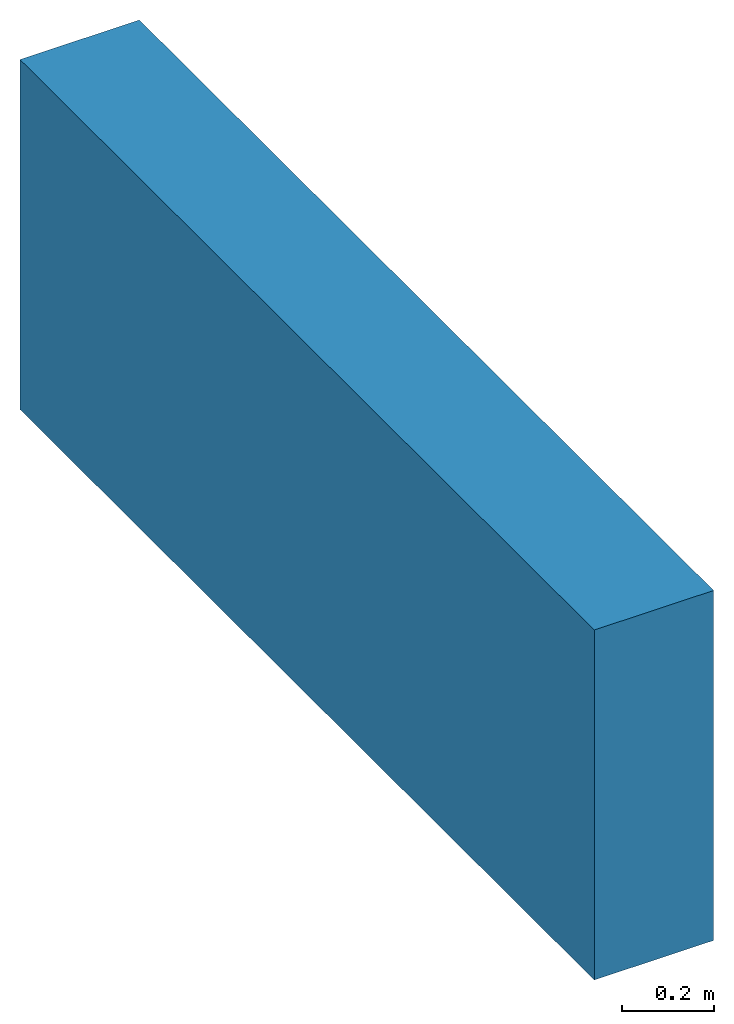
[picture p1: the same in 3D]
Properties of the parts of a building model (IFC2X3), part 4 of 4

# IfcWallStandardCase: Basic Wall:A241 - RVR-75.1 (4)
Name (Basic Wall:A241 - RVR-75.1:...) | In | 08_Status | 07_Fase | 03_Ansvar | 02_Prosjekt | 06_Omrade | 01_Lufthavnkode | Area, side, gross, larger (Simplebim) (m2) = Area, side, gross, AABB (Simplebim) (m2) = Area, side, gross, average (Simplebim) (m2) = Area, side, gross, smaller (Simplebim) (m2) | Height (Simplebim) (mm) | Area, side, net, smaller (Simplebim) (m2) = Area, side, net, larger (Simplebim) (m2) = Area, side, net, average (Simplebim) (m2) = Area, largest surface, net (Simplebim) (m2) | Volume, net (Simplebim) (m3) | Length (Simplebim) (mm)
66805208 | Nivå F | S4 | F90 | 188110 | 10004394 | TS | ENGM | 0.879275 | 1200 | 0.879275 | 0.0879275 | 732.729 | AVINOR - 09_Arbeidspakke: SELV ARBEIDER
66984557 | Nivå F |  |  |  |  |  |  | 9.51925 | 2900 | 9.51925 | 0.951925 | 3282.5 | AVINOR - 09_Arbeidspakke: SELV ARBEIDER

# IfcWallStandardCase: Basic Wall:A241 - RVR-75.2 (7)
Type - PredefinedType: STANDARD; Material: Plate - Gips 12.5 mm, _NSW Stålstender, uisolert 75 mm, Plate - Gips 12.5 mm
ePset_SimplebimBasicQuantities - Thickness (Simplebim): 100 mm
Pset_ReinforcementBarPitchOfWall - Reference: A241 - RVR-75.2; sets with these values: 2
AVINOR - 08_Status: S4; 07_Fase: F90; 03_Ansvar: 188110; 02_Prosjekt: 10004394; 06_Omrade: TS; 09_Arbeidspakke: SELV ARBEIDER; 01_Lufthavnkode: ENGM
ePset_Simplebim - Assembly Level: Leaf
Pset_WallCommon - IsExternal: no; ExtendToStructure: no; LoadBearing: no; Reference: A241 - RVR-75.2
ePset_LocationTool - Splitting: ORIGINAL
Name (Basic Wall:A241 - RVR-75.2:...) | In | Area, side, gross, AABB (Simplebim) (m2) = Area, side, net, smaller (Simplebim) (m2) = Area, largest surface, net (Simplebim) (m2) = Area, side, gross, larger (Simplebim) (m2) = Area, side, gross, smaller (Simplebim) (m2) = Area, side, net, larger (Simplebim) (m2) = Area, side, net, average (Simplebim) (m2) = Area, side, gross, average (Simplebim) (m2) | Height (Simplebim) (mm) | Length (Simplebim) (mm) | Volume, net (Simplebim) (m3)
66777142 | Nivå F | 2.51287 | 2860 | 878.626 | 0.251287
66807749 | Nivå F | 2.57383 | 2860 | 899.939 | 0.257383
66861823 | Nivå F | 1.8844 | 2800 | 673 | 0.18844 | AVINOR - 04_Kontrakt: 187110
66861823 | Nivå G - 2,0m | 0.1346 | 200 | 673 | 0.01346 | AVINOR - 04_Kontrakt: 187110
66870368 | Nivå F | 1.4442 | 2900 | 498 | 0.14442 | AVINOR - 04_Kontrakt: 187110
66958814 | Nivå F | 1.42428 | 2860 | 498 | 0.142428
66965243 | Nivå F | 1.9467 | 2860 | 680.664 | 0.19467

# IfcWallStandardCase: Basic Wall:A241 - RXV-75 (5)
In: Nivå F
Type - PredefinedType: STANDARD; Material: T2_Gips Fibergips 13 mm, T2 - Kryssfiner 12 mm, _NSW Isolasjon 75 mm
ePset_LocationTool - Splitting: ORIGINAL
Pset_WallCommon - IsExternal: no; ExtendToStructure: no; LoadBearing: no; Reference: A241 - RXV-75
Pset_QuantityTakeOff - Reference: A241 - RXV-75; sets with these values: 2
AVINOR - 03_Ansvar: 188110; 02_Prosjekt: 10004394; 09_Arbeidspakke: SELV ARBEIDER; 01_Lufthavnkode: ENGM
ePset_Simplebim - Assembly Level: Leaf
ePset_SimplebimBasicQuantities - Thickness (Simplebim): 100 mm
Name (Basic Wall:A241 - RXV-75:...) | 08_Status | 07_Fase | 06_Omrade | Height (Simplebim) (mm) | Area, side, gross, AABB (Simplebim) (m2) | Area, side, net, smaller (Simplebim) (m2) = Area, side, gross, smaller (Simplebim) (m2) | Area, largest surface, net (Simplebim) (m2) = Area, side, gross, larger (Simplebim) (m2) = Area, side, net, larger (Simplebim) (m2) | Area, side, gross, average (Simplebim) (m2) = Area, side, net, average (Simplebim) (m2) | Length (Simplebim) (mm) | Volume, net (Simplebim) (m3)
66810390 | S4 | F90 | TS | 587.5 | 1.17678 | 1.17678 | 1.17678 | 1.17678 | 2003.03 | 0.117678
66811929 | S4 | F90 | TS | 587.5 | 1.16762 | 1.16762 | 1.16762 | 1.16762 | 1987.45 | 0.116762
66815713 | S2 |  | TS | 2860 | 11.2687 | 10.8915 | 11.2687 | 11.0801 | 3940.1 | 1.10801
66826869 | S2 |  | TS | 2860 | 5.26002 | 4.88281 | 4.88281 | 4.88281 | 1839.17 | 0.488281
67387644 | S4 | F90 |  | 2860 | 15.9601 | 15.9601 | 15.9601 | 15.9601 | 5580.44 | 1.59601

# IfcWallStandardCase: Basic Wall:A241 - RXVXR-100 (4)
Type - PredefinedType: STANDARD; Material: T2_Gips Fibergips 13 mm, T2 - Kryssfiner 15 mm, _NSW Stålstender, uisolert 100 mm, T2 - Kryssfiner 15 mm, T2_Gips Fibergips 13 mm
Type - Pset_ReinforcementBarPitchOfWall - Description: Tilsvarende: T2 - IVEGG-150 - Forprosjekt
Pset_ReinforcementBarPitchOfWall - Reference: A241 - RXVXR-100; sets with these values: 2
ePset_SimplebimBasicQuantities - Thickness (Simplebim): 156 mm
Pset_WallCommon - Reference: A241 - RXVXR-100; IsExternal: no; ExtendToStructure: no; LoadBearing: no
ePset_Simplebim - Assembly Level: Leaf
AVINOR - 08_Status: S4; 07_Fase: F90; 06_Omrade: TS; 01_Lufthavnkode: ENGM
ePset_LocationTool - Splitting: ORIGINAL
Name (Basic Wall:A241 - RXVXR-100:...) | In | Area, side, net, smaller (Simplebim) (m2) = Area, side, net, larger (Simplebim) (m2) = Area, side, net, average (Simplebim) (m2) | Area, side, gross, AABB (Simplebim) (m2) | Area, side, gross, smaller (Simplebim) (m2) = Area, side, gross, average (Simplebim) (m2) = Area, side, gross, larger (Simplebim) (m2) | Area, largest surface, net (Simplebim) (m2) | Length (Simplebim) (mm) | Height (Simplebim) (mm) | Volume, net (Simplebim) (m3) | 03_Ansvar | 02_Prosjekt
46493956 | Nivå F | 2.53912 | 4.81163 | 4.82172 | 2.33663 | 2138.5 | 2250 | 0.396104 | OSL | AO205066
46493958 | Nivå F | 1.60425 | 1.60425 | 1.60425 | 1.60425 | 713 | 2250 | 0.250263 | OSL | AO205066
66776640 | Nivå F | 6.21785 | 6.21785 | 6.21785 | 6.21785 | 2220.66 | 2800 | 0.969984 | 188110 | 10004394 | AVINOR - 04_Kontrakt: 187110; 05_ID-nummer: +TS=241.544
66776640 | Nivå G - 2,0m | 0.444132 | 0.444132 | 0.444132 | 0.444132 | 2220.66 | 200 | 0.0692846 | 188110 | 10004394 | AVINOR - 04_Kontrakt: 187110; 05_ID-nummer: +TS=241.544

# IfcWallStandardCase: Basic Wall:A241 - RXVXR-75 (2)
Type - PredefinedType: STANDARD; Material: T2_Gips Robust 12.5 mm, T2 - Kryssfiner 12 mm, _NSW Isolasjon 75 mm, T2 - Kryssfiner 12 mm, T2_Gips Robust 12.5 mm
Pset_QuantityTakeOff - Reference: A241 - RXVXR-75; sets with these values: 2
Pset_WallCommon - IsExternal: no; ExtendToStructure: no; LoadBearing: no; Reference: A241 - RXVXR-75
ePset_LocationTool - Splitting: ORIGINAL
AVINOR - 08_Status: S4; 07_Fase: F90; 03_Ansvar: 188110; 04_Kontrakt: 187110; 02_Prosjekt: 10004394; 05_ID-nummer: +TS=241.545; 06_Omrade: TS; 01_Lufthavnkode: ENGM
ePset_Simplebim - Assembly Level: Leaf
ePset_SimplebimBasicQuantities - Length (Simplebim): 877.433 mm; Thickness (Simplebim): 124 mm
Name (Basic Wall:A241 - RXVXR-75:...) | In | Area, side, gross, AABB (Simplebim) (m2) | Height (Simplebim) (mm) | Area, side, gross, smaller (Simplebim) (m2) = Area, side, net, larger (Simplebim) (m2) = Area, side, net, average (Simplebim) (m2) = Area, side, gross, average (Simplebim) (m2) = Area, side, gross, larger (Simplebim) (m2) = Area, largest surface, net (Simplebim) (m2) = Area, side, net, smaller (Simplebim) (m2) | Volume, net (Simplebim) (m3)
66805199 | Nivå F | 2.45681 | 2800 | 2.08471 | 0.258505
66805199 | Nivå G - 2,0m | 0.175487 | 200 | 0.175487 | 0.0217604

# IfcWallStandardCase: Basic Wall:A241 - SSVR-100, Basic Wall:A241 - SSVR-100:46493175
In: Nivå F
Type - PredefinedType: STANDARD; Material: Plate - Gips 12.5 mm, Plate - Gips 12.5 mm, _NSW Stålstender, uisolert 100 mm, T2_Gips Robust 12.5 mm
Type - Pset_ReinforcementBarPitchOfWall - Description: Tilsvarende: T2 - IVEGG-150 - Forprosjekt
Pset_QuantityTakeOff - Reference: A241 - SSVR-100; sets with these values: 2
ePset_LocationTool - Splitting: ORIGINAL
ePset_Simplebim - Assembly Level: Leaf
AVINOR - 08_Status: S4; 07_Fase: F90; 06_Omrade: TS; 03_Ansvar: OSL; 01_Lufthavnkode: ENGM; 02_Prosjekt: AO205066
Pset_WallCommon - Reference: A241 - SSVR-100; IsExternal: no; ExtendToStructure: no; LoadBearing: no
ePset_SimplebimBasicQuantities - Area, largest surface, net (Simplebim): 8.83338 m2; Area, side, gross, larger (Simplebim): 8.83338 m2; Area, side, net, average (Simplebim): 8.83338 m2; Area, side, gross, average (Simplebim): 8.83338 m2; Area, side, gross, smaller (Simplebim): 8.83338 m2; Area, side, net, larger (Simplebim): 8.83338 m2; Area, side, net, smaller (Simplebim): 8.83338 m2; Area, side, gross, AABB (Simplebim): 8.83338 m2; Volume, net (Simplebim): 1.21459 m3; Thickness (Simplebim): 137.5 mm; Height (Simplebim): 2760 mm; Length (Simplebim): 3200.5 mm

# IfcWallStandardCase: Basic Wall:A241 - SVS-101 (2)
Type - PredefinedType: STANDARD; Material: Plate - Gips 12.5 mm, Plate - Gips 12.5 mm, _NSW Stålstender, uisolert 100 mm, Plate - Gips 12.5 mm, Plate - Gips 12.5 mm
Type - Pset_ReinforcementBarPitchOfWall - Description: Stendervegg: 2x12.5mm Gipsplater - 100mm Stålstender - 2x12.5mm Gipsplater
Pset_ReinforcementBarPitchOfWall - Reference: A241 - SVS-101; sets with these values: 2
ePset_SimplebimBasicQuantities - Thickness (Simplebim): 150 mm; Length (Simplebim): 1350.24 mm
ePset_LocationTool - Splitting: ORIGINAL
AVINOR - 08_Status: S4; 07_Fase: F90; 05_ID-nummer: +TS=241.051; 03_Ansvar: 182412; 02_Prosjekt: A173790; 06_Omrade: TS; 01_Lufthavnkode: ENGM
ePset_Simplebim - Assembly Level: Leaf
Pset_WallCommon - IsExternal: no; ExtendToStructure: no; LoadBearing: no; Reference: A241 - SVS-101
Name (Basic Wall:A241 - SVS-101:...) | In | Height (Simplebim) (mm) | Volume, net (Simplebim) (m3) | Area, side, gross, larger (Simplebim) (m2) = Area, side, gross, smaller (Simplebim) (m2) = Area, side, gross, average (Simplebim) (m2) | Area, largest surface, net (Simplebim) (m2) | Area, side, net, smaller (Simplebim) (m2) = Area, side, net, average (Simplebim) (m2) = Area, side, net, larger (Simplebim) (m2) | Area, side, gross, AABB (Simplebim) (m2)
47507217 | Nivå F | 2778 | 0.031763 | 3.89365 | 0.4167 | 0.211753 | 3.75096
47507217 | Nivå G - 2,0m | 254 | 0.0323339 | 3.89746 | 0.215559 | 0.215559 | 0.34296

# IfcWallStandardCase: Basic Wall:A241 - SXV-100, Basic Wall:A241 - SXV-100:46514050
In: Nivå F
Type - PredefinedType: STANDARD; Material: Plate - Gips 12.5 mm, _NSW X-finer 12 mm, _NSW Stålstender, uisolert 100 mm
Type - Pset_ReinforcementBarPitchOfWall - Description: 12,5mm Gipsplatter - 15mm X-finer - Stendervegg 100mm
Pset_WallCommon - IsExternal: no; ExtendToStructure: no; LoadBearing: no; Reference: A241 - SXV-100
ePset_SimplebimBasicQuantities - Volume, net (Simplebim): 0.796675 m3; Length (Simplebim): 2844 mm; Thickness (Simplebim): 124.5 mm; Area, side, gross, AABB (Simplebim): 6.399 m2; Area, side, net, smaller (Simplebim): 6.399 m2; Area, largest surface, net (Simplebim): 6.399 m2; Area, side, gross, larger (Simplebim): 6.399 m2; Area, side, gross, average (Simplebim): 6.399 m2; Area, side, net, average (Simplebim): 6.399 m2; Area, side, net, larger (Simplebim): 6.399 m2; Area, side, gross, smaller (Simplebim): 6.399 m2; Height (Simplebim): 2250 mm
ePset_LocationTool - Splitting: ORIGINAL
ePset_Simplebim - Assembly Level: Leaf
AVINOR - 08_Status: S4; 07_Fase: F90; 06_Omrade: TS; 03_Ansvar: OSL; 01_Lufthavnkode: ENGM; 02_Prosjekt: AO205066
Pset_QuantityTakeOff - Reference: A241 - SXV-100; sets with these values: 2

# IfcWallStandardCase: Basic Wall:A241 - SXVS-100 (5)
Type - PredefinedType: STANDARD; Material: Plate - Gips 12.5 mm, _NSW X-finer 15 mm, _NSW Stålstender, uisolert 100 mm, Plate - Gips 12.5 mm
Type - Pset_ReinforcementBarPitchOfWall - Description: 12,5mm Gipsplatter - 15mm X-finer - Stendervegg 100mm
ePset_LocationTool - Splitting: ORIGINAL
Pset_ReinforcementBarPitchOfWall - Reference: A241 - SXVS-100; sets with these values: 2
ePset_SimplebimBasicQuantities - Thickness (Simplebim): 140 mm
Pset_WallCommon - Reference: A241 - SXVS-100; IsExternal: no; ExtendToStructure: no; LoadBearing: no
ePset_Simplebim - Assembly Level: Leaf
Name (Basic Wall:A241 - SXVS-100:...) | In | Volume, net (Simplebim) (m3) | Height (Simplebim) (mm) | Length (Simplebim) (mm) | Area, side, net, smaller (Simplebim) (m2) = Area, side, gross, larger (Simplebim) (m2) = Area, side, net, larger (Simplebim) (m2) = Area, side, gross, smaller (Simplebim) (m2) = Area, side, gross, average (Simplebim) (m2) = Area, side, net, average (Simplebim) (m2) | Area, largest surface, net (Simplebim) (m2) | Area, side, gross, AABB (Simplebim) (m2) | 08_Status | 07_Fase | 05_ID-nummer | 03_Ansvar | 02_Prosjekt | 06_Omrade | 01_Lufthavnkode
47507272 | Nivå F | 1.13683 | 2821 | 2878.5 | 8.12025 | 8.12025 | 8.12025 | S4 | F90 | +TS=241.059 | 182412 | A173790 | TS | ENGM
66776914 | Nivå F | 0.599038 | 2778 | 1540.26 | 4.27884 | 4.27884 | 4.27884 | S4 | F90 | +TS=241.546 | 188110 | 10004394 | TS | ENGM
66776914 | Nivå G - 2,0m | 0.0263076 | 122 | 1540.26 | 0.187912 | 0.215636 | 0.187912 | S4 | F90 | +TS=241.546 | 188110 | 10004394 | TS | ENGM
66987759 | Nivå F | 0.0557917 | 57 | 6991.44 | 0.398512 | 0.978802 | 0.398512
66988626 | Nivå F | 0.0326104 | 79 | 2948.5 | 0.232932 | 0.41279 | 0.232931 | S4 | F90 | +TS=241.059 | 182412 | A173790 | TS | ENGM

# IfcWallStandardCase: Basic Wall:A241 - SXVXS-100 (7)
In: Nivå F
Type - PredefinedType: STANDARD; Material: Plate - Gips 12.5 mm, _NSW X-finer 15 mm, _NSW Stålstender, isolert UTEN SKRAVUR 100 mm, _NSW X-finer 15 mm, Plate - Gips 12.5 mm
Type - Pset_ReinforcementBarPitchOfWall - Description: Tilsvarende: T2 - IVEGG-125 - Forprosjekt
Pset_QuantityTakeOff - Reference: A241 - SXVXS-100; sets with these values: 2
ePset_SimplebimBasicQuantities - Thickness (Simplebim): 155 mm
ePset_LocationTool - Splitting: ORIGINAL
Pset_WallCommon - IsExternal: no; ExtendToStructure: no; LoadBearing: no; Reference: A241 - SXVXS-100
ePset_Simplebim - Assembly Level: Leaf
Name (Basic Wall:A241 - SXVXS-100:...) | Length (Simplebim) (mm) | Height (Simplebim) (mm) | Area, side, gross, larger (Simplebim) (m2) = Area, side, gross, smaller (Simplebim) (m2) = Area, side, gross, average (Simplebim) (m2) = Area, side, gross, AABB (Simplebim) (m2) | Area, side, net, larger (Simplebim) (m2) = Area, side, net, average (Simplebim) (m2) = Area, side, net, smaller (Simplebim) (m2) | Area, largest surface, net (Simplebim) (m2) | Volume, net (Simplebim) (m3) | 08_Status | 07_Fase | 03_Ansvar | 02_Prosjekt | 05_ID-nummer | 06_Omrade | 01_Lufthavnkode
47507109 | 10358 | 2900 | 30.0383 | 30.0383 | 30.0383 | 4.65594 | S4 | F90 | 182412 | A173790 | +TS=241.047 | TS | ENGM
47507111 | 3614.5 | 2900 | 10.482 | 8.56195 | 8.56195 | 1.3271 | S4 | F90 | 182412 | A173790 | +TS=241.047 | TS | ENGM
47507132 | 10952.3 | 2900 | 31.7618 | 27.4996 | 27.4996 | 4.26244 | S4 | F90 | 182412 | A173790 | +TS=241.047 | TS | ENGM
47507133 | 685 | 2900 | 1.9865 | 0.2063 | 0.4495 | 0.0319765 | S4 | F90 | 182412 | A173790 | +TS=241.047 | TS | ENGM
47507135 | 890 | 2900 | 2.581 | 2.581 | 2.581 | 0.400055 | S4 | F90 | 182412 | A173790 | +TS=241.047 | TS | ENGM
66771269 | 2096.34 | 2900 | 6.07938 | 6.07938 | 6.07938 | 0.942303
66988290 | 4658.28 | 57 | 0.265522 | 0.265522 | 0.722034 | 0.0411559 | S4 | F90 | 182412 | A173790 | +TS=241.047 | TS | ENGM

# IfcWallStandardCase: Basic Wall:A241 - V2 (2)
Type - PredefinedType: STANDARD; Material: T2_Fibersement 15 mm, _NSW Stålstender, uisolert 100 mm, T2_X-finer 12 mm, T2_Fibersement 15 mm
Type - Pset_ReinforcementBarPitchOfWall - Description: økt toalettkapasitet i pir øst nivå F - 72101-A127372
ePset_LocationTool - Splitting: ORIGINAL
ePset_SimplebimBasicQuantities - Thickness (Simplebim): 142 mm; Length (Simplebim): 360.2 mm
ePset_Simplebim - Assembly Level: Leaf
Pset_QuantityTakeOff - Reference: A241 - V2; sets with these values: 2
AVINOR - 08_Status: S4; 07_Fase: F90; 02_Prosjekt: A161568; 03_Ansvar: 182412; 04_Kontrakt: 182251; 06_Omrade: TS; 01_Lufthavnkode: ENGM
Pset_WallCommon - IsExternal: no; ExtendToStructure: no; LoadBearing: no; Reference: A241 - V2
Name (Basic Wall:A241 - V2:...) | In | Height (Simplebim) (mm) | Area, largest surface, net (Simplebim) (m2) = Area, side, gross, smaller (Simplebim) (m2) = Area, side, net, larger (Simplebim) (m2) = Area, side, net, average (Simplebim) (m2) = Area, side, gross, average (Simplebim) (m2) = Area, side, gross, larger (Simplebim) (m2) = Area, side, net, smaller (Simplebim) (m2) = Area, side, gross, AABB (Simplebim) (m2) | Volume, net (Simplebim) (m3)
46579895 | Nivå F | 2800 | 1.00856 | 0.143216
46579895 | Nivå G - 2,0m | 200 | 0.07204 | 0.0102297
